VERSION 5.8 ;
BUSBITCHARS "[]" ;
DIVIDERCHAR "/" ;
UNITS
    DATABASE MICRONS 1000 ;
END UNITS

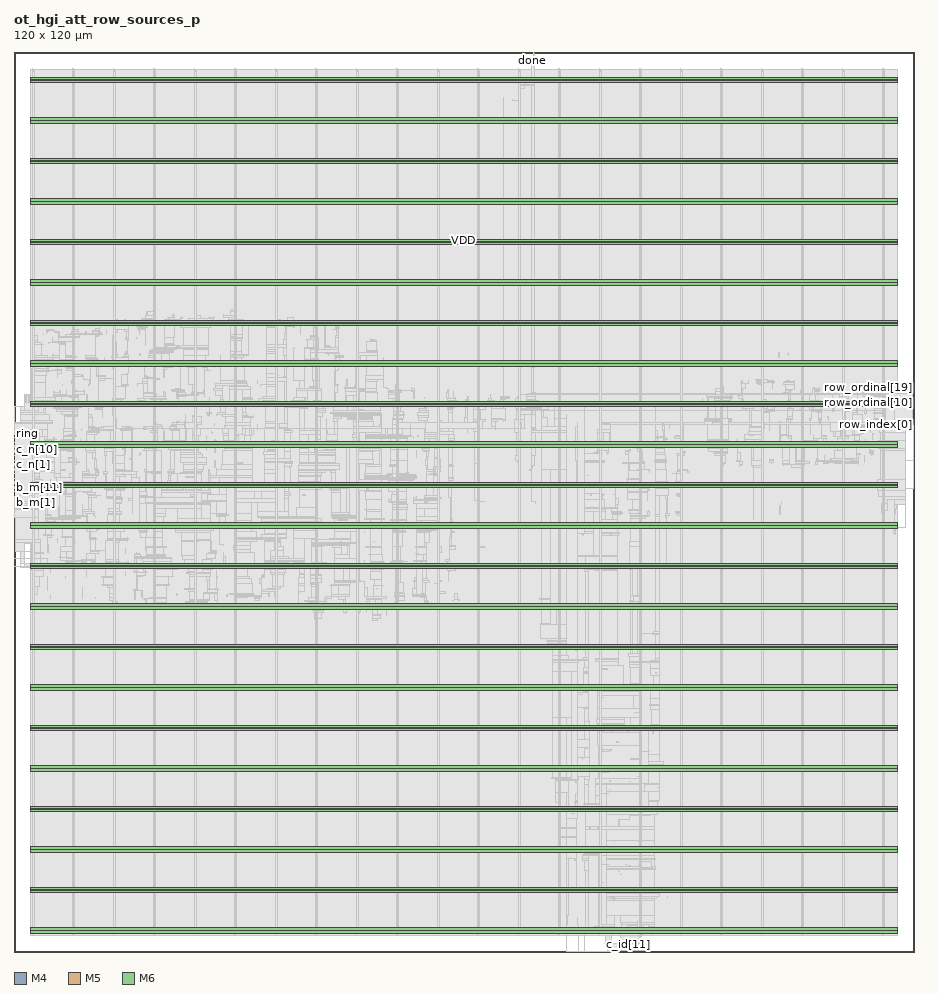
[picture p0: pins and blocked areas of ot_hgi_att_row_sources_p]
MACRO ot_hgi_att_row_sources_p
  FOREIGN ot_hgi_att_row_sources_p 0 0 ;
  CLASS BLOCK ;
  SIZE 120 BY 120 ;
  PIN b_m[0]
    DIRECTION INPUT ;
    USE SIGNAL ;
    PORT
      LAYER M4 ;
        RECT  0 60.912 0.084 60.936 ;
    END
  END b_m[0]
  PIN b_m[10]
    DIRECTION INPUT ;
    USE SIGNAL ;
    PORT
      LAYER M4 ;
        RECT  0 61.872 0.084 61.896 ;
    END
  END b_m[10]
  PIN b_m[11]
    DIRECTION INPUT ;
    USE SIGNAL ;
    PORT
      LAYER M4 ;
        RECT  0 61.968 0.084 61.992 ;
    END
  END b_m[11]
  PIN b_m[12]
    DIRECTION INPUT ;
    USE SIGNAL ;
    PORT
      LAYER M4 ;
        RECT  0 62.064 0.084 62.088 ;
    END
  END b_m[12]
  PIN b_m[13]
    DIRECTION INPUT ;
    USE SIGNAL ;
    PORT
      LAYER M4 ;
        RECT  0 62.16 0.084 62.184 ;
    END
  END b_m[13]
  PIN b_m[14]
    DIRECTION INPUT ;
    USE SIGNAL ;
    PORT
      LAYER M4 ;
        RECT  0 62.256 0.084 62.28 ;
    END
  END b_m[14]
  PIN b_m[15]
    DIRECTION INPUT ;
    USE SIGNAL ;
    PORT
      LAYER M4 ;
        RECT  0 62.352 0.084 62.376 ;
    END
  END b_m[15]
  PIN b_m[16]
    DIRECTION INPUT ;
    USE SIGNAL ;
    PORT
      LAYER M4 ;
        RECT  0 62.448 0.084 62.472 ;
    END
  END b_m[16]
  PIN b_m[17]
    DIRECTION INPUT ;
    USE SIGNAL ;
    PORT
      LAYER M4 ;
        RECT  0 62.544 0.084 62.568 ;
    END
  END b_m[17]
  PIN b_m[18]
    DIRECTION INPUT ;
    USE SIGNAL ;
    PORT
      LAYER M4 ;
        RECT  0 62.64 0.084 62.664 ;
    END
  END b_m[18]
  PIN b_m[19]
    DIRECTION INPUT ;
    USE SIGNAL ;
    PORT
      LAYER M4 ;
        RECT  0 62.736 0.084 62.76 ;
    END
  END b_m[19]
  PIN b_m[1]
    DIRECTION INPUT ;
    USE SIGNAL ;
    PORT
      LAYER M4 ;
        RECT  0 61.008 0.084 61.032 ;
    END
  END b_m[1]
  PIN b_m[20]
    DIRECTION INPUT ;
    USE SIGNAL ;
    PORT
      LAYER M4 ;
        RECT  0 62.832 0.084 62.856 ;
    END
  END b_m[20]
  PIN b_m[2]
    DIRECTION INPUT ;
    USE SIGNAL ;
    PORT
      LAYER M4 ;
        RECT  0 61.104 0.084 61.128 ;
    END
  END b_m[2]
  PIN b_m[3]
    DIRECTION INPUT ;
    USE SIGNAL ;
    PORT
      LAYER M4 ;
        RECT  0 61.2 0.084 61.224 ;
    END
  END b_m[3]
  PIN b_m[4]
    DIRECTION INPUT ;
    USE SIGNAL ;
    PORT
      LAYER M4 ;
        RECT  0 61.296 0.084 61.32 ;
    END
  END b_m[4]
  PIN b_m[5]
    DIRECTION INPUT ;
    USE SIGNAL ;
    PORT
      LAYER M4 ;
        RECT  0 61.392 0.084 61.416 ;
    END
  END b_m[5]
  PIN b_m[6]
    DIRECTION INPUT ;
    USE SIGNAL ;
    PORT
      LAYER M4 ;
        RECT  0 61.488 0.084 61.512 ;
    END
  END b_m[6]
  PIN b_m[7]
    DIRECTION INPUT ;
    USE SIGNAL ;
    PORT
      LAYER M4 ;
        RECT  0 61.584 0.084 61.608 ;
    END
  END b_m[7]
  PIN b_m[8]
    DIRECTION INPUT ;
    USE SIGNAL ;
    PORT
      LAYER M4 ;
        RECT  0 61.68 0.084 61.704 ;
    END
  END b_m[8]
  PIN b_m[9]
    DIRECTION INPUT ;
    USE SIGNAL ;
    PORT
      LAYER M4 ;
        RECT  0 61.776 0.084 61.8 ;
    END
  END b_m[9]
  PIN b_n[0]
    DIRECTION INPUT ;
    USE SIGNAL ;
    PORT
      LAYER M4 ;
        RECT  0 62.928 0.084 62.952 ;
    END
  END b_n[0]
  PIN b_n[10]
    DIRECTION INPUT ;
    USE SIGNAL ;
    PORT
      LAYER M4 ;
        RECT  0 63.888 0.084 63.912 ;
    END
  END b_n[10]
  PIN b_n[11]
    DIRECTION INPUT ;
    USE SIGNAL ;
    PORT
      LAYER M4 ;
        RECT  0 63.984 0.084 64.008 ;
    END
  END b_n[11]
  PIN b_n[12]
    DIRECTION INPUT ;
    USE SIGNAL ;
    PORT
      LAYER M4 ;
        RECT  0 64.08 0.084 64.104 ;
    END
  END b_n[12]
  PIN b_n[13]
    DIRECTION INPUT ;
    USE SIGNAL ;
    PORT
      LAYER M4 ;
        RECT  0 64.176 0.084 64.2 ;
    END
  END b_n[13]
  PIN b_n[14]
    DIRECTION INPUT ;
    USE SIGNAL ;
    PORT
      LAYER M4 ;
        RECT  0 64.272 0.084 64.296 ;
    END
  END b_n[14]
  PIN b_n[15]
    DIRECTION INPUT ;
    USE SIGNAL ;
    PORT
      LAYER M4 ;
        RECT  0 64.368 0.084 64.392 ;
    END
  END b_n[15]
  PIN b_n[16]
    DIRECTION INPUT ;
    USE SIGNAL ;
    PORT
      LAYER M4 ;
        RECT  0 64.464 0.084 64.488 ;
    END
  END b_n[16]
  PIN b_n[17]
    DIRECTION INPUT ;
    USE SIGNAL ;
    PORT
      LAYER M4 ;
        RECT  0 64.56 0.084 64.584 ;
    END
  END b_n[17]
  PIN b_n[18]
    DIRECTION INPUT ;
    USE SIGNAL ;
    PORT
      LAYER M4 ;
        RECT  0 64.656 0.084 64.68 ;
    END
  END b_n[18]
  PIN b_n[19]
    DIRECTION INPUT ;
    USE SIGNAL ;
    PORT
      LAYER M4 ;
        RECT  0 64.752 0.084 64.776 ;
    END
  END b_n[19]
  PIN b_n[1]
    DIRECTION INPUT ;
    USE SIGNAL ;
    PORT
      LAYER M4 ;
        RECT  0 63.024 0.084 63.048 ;
    END
  END b_n[1]
  PIN b_n[20]
    DIRECTION INPUT ;
    USE SIGNAL ;
    PORT
      LAYER M4 ;
        RECT  0 64.848 0.084 64.872 ;
    END
  END b_n[20]
  PIN b_n[2]
    DIRECTION INPUT ;
    USE SIGNAL ;
    PORT
      LAYER M4 ;
        RECT  0 63.12 0.084 63.144 ;
    END
  END b_n[2]
  PIN b_n[3]
    DIRECTION INPUT ;
    USE SIGNAL ;
    PORT
      LAYER M4 ;
        RECT  0 63.216 0.084 63.24 ;
    END
  END b_n[3]
  PIN b_n[4]
    DIRECTION INPUT ;
    USE SIGNAL ;
    PORT
      LAYER M4 ;
        RECT  0 63.312 0.084 63.336 ;
    END
  END b_n[4]
  PIN b_n[5]
    DIRECTION INPUT ;
    USE SIGNAL ;
    PORT
      LAYER M4 ;
        RECT  0 63.408 0.084 63.432 ;
    END
  END b_n[5]
  PIN b_n[6]
    DIRECTION INPUT ;
    USE SIGNAL ;
    PORT
      LAYER M4 ;
        RECT  0 63.504 0.084 63.528 ;
    END
  END b_n[6]
  PIN b_n[7]
    DIRECTION INPUT ;
    USE SIGNAL ;
    PORT
      LAYER M4 ;
        RECT  0 63.6 0.084 63.624 ;
    END
  END b_n[7]
  PIN b_n[8]
    DIRECTION INPUT ;
    USE SIGNAL ;
    PORT
      LAYER M4 ;
        RECT  0 63.696 0.084 63.72 ;
    END
  END b_n[8]
  PIN b_n[9]
    DIRECTION INPUT ;
    USE SIGNAL ;
    PORT
      LAYER M4 ;
        RECT  0 63.792 0.084 63.816 ;
    END
  END b_n[9]
  PIN busy
    DIRECTION OUTPUT ;
    USE SIGNAL ;
    PORT
      LAYER M5 ;
        RECT  68.976 119.916 69 120 ;
    END
  END busy
  PIN c_id[0]
    DIRECTION INPUT ;
    USE SIGNAL ;
    PORT
      LAYER M5 ;
        RECT  80.88 0 80.904 0.084 ;
    END
  END c_id[0]
  PIN c_id[10]
    DIRECTION INPUT ;
    USE SIGNAL ;
    PORT
      LAYER M5 ;
        RECT  81.84 0 81.864 0.084 ;
    END
  END c_id[10]
  PIN c_id[11]
    DIRECTION INPUT ;
    USE SIGNAL ;
    PORT
      LAYER M5 ;
        RECT  81.936 0 81.96 0.084 ;
    END
  END c_id[11]
  PIN c_id[12]
    DIRECTION INPUT ;
    USE SIGNAL ;
    PORT
      LAYER M5 ;
        RECT  82.032 0 82.056 0.084 ;
    END
  END c_id[12]
  PIN c_id[13]
    DIRECTION INPUT ;
    USE SIGNAL ;
    PORT
      LAYER M5 ;
        RECT  82.128 0 82.152 0.084 ;
    END
  END c_id[13]
  PIN c_id[14]
    DIRECTION INPUT ;
    USE SIGNAL ;
    PORT
      LAYER M5 ;
        RECT  82.224 0 82.248 0.084 ;
    END
  END c_id[14]
  PIN c_id[15]
    DIRECTION INPUT ;
    USE SIGNAL ;
    PORT
      LAYER M5 ;
        RECT  82.32 0 82.344 0.084 ;
    END
  END c_id[15]
  PIN c_id[16]
    DIRECTION INPUT ;
    USE SIGNAL ;
    PORT
      LAYER M5 ;
        RECT  82.416 0 82.44 0.084 ;
    END
  END c_id[16]
  PIN c_id[17]
    DIRECTION INPUT ;
    USE SIGNAL ;
    PORT
      LAYER M5 ;
        RECT  82.512 0 82.536 0.084 ;
    END
  END c_id[17]
  PIN c_id[18]
    DIRECTION INPUT ;
    USE SIGNAL ;
    PORT
      LAYER M5 ;
        RECT  82.608 0 82.632 0.084 ;
    END
  END c_id[18]
  PIN c_id[19]
    DIRECTION INPUT ;
    USE SIGNAL ;
    PORT
      LAYER M5 ;
        RECT  82.704 0 82.728 0.084 ;
    END
  END c_id[19]
  PIN c_id[1]
    DIRECTION INPUT ;
    USE SIGNAL ;
    PORT
      LAYER M5 ;
        RECT  80.976 0 81 0.084 ;
    END
  END c_id[1]
  PIN c_id[20]
    DIRECTION INPUT ;
    USE SIGNAL ;
    PORT
      LAYER M5 ;
        RECT  82.8 0 82.824 0.084 ;
    END
  END c_id[20]
  PIN c_id[21]
    DIRECTION INPUT ;
    USE SIGNAL ;
    PORT
      LAYER M5 ;
        RECT  82.896 0 82.92 0.084 ;
    END
  END c_id[21]
  PIN c_id[22]
    DIRECTION INPUT ;
    USE SIGNAL ;
    PORT
      LAYER M5 ;
        RECT  82.992 0 83.016 0.084 ;
    END
  END c_id[22]
  PIN c_id[23]
    DIRECTION INPUT ;
    USE SIGNAL ;
    PORT
      LAYER M5 ;
        RECT  83.088 0 83.112 0.084 ;
    END
  END c_id[23]
  PIN c_id[24]
    DIRECTION INPUT ;
    USE SIGNAL ;
    PORT
      LAYER M5 ;
        RECT  83.184 0 83.208 0.084 ;
    END
  END c_id[24]
  PIN c_id[25]
    DIRECTION INPUT ;
    USE SIGNAL ;
    PORT
      LAYER M5 ;
        RECT  83.28 0 83.304 0.084 ;
    END
  END c_id[25]
  PIN c_id[26]
    DIRECTION INPUT ;
    USE SIGNAL ;
    PORT
      LAYER M5 ;
        RECT  83.376 0 83.4 0.084 ;
    END
  END c_id[26]
  PIN c_id[27]
    DIRECTION INPUT ;
    USE SIGNAL ;
    PORT
      LAYER M5 ;
        RECT  83.472 0 83.496 0.084 ;
    END
  END c_id[27]
  PIN c_id[28]
    DIRECTION INPUT ;
    USE SIGNAL ;
    PORT
      LAYER M5 ;
        RECT  83.568 0 83.592 0.084 ;
    END
  END c_id[28]
  PIN c_id[29]
    DIRECTION INPUT ;
    USE SIGNAL ;
    PORT
      LAYER M5 ;
        RECT  83.664 0 83.688 0.084 ;
    END
  END c_id[29]
  PIN c_id[2]
    DIRECTION INPUT ;
    USE SIGNAL ;
    PORT
      LAYER M5 ;
        RECT  81.072 0 81.096 0.084 ;
    END
  END c_id[2]
  PIN c_id[30]
    DIRECTION INPUT ;
    USE SIGNAL ;
    PORT
      LAYER M5 ;
        RECT  83.76 0 83.784 0.084 ;
    END
  END c_id[30]
  PIN c_id[31]
    DIRECTION INPUT ;
    USE SIGNAL ;
    PORT
      LAYER M5 ;
        RECT  83.856 0 83.88 0.084 ;
    END
  END c_id[31]
  PIN c_id[3]
    DIRECTION INPUT ;
    USE SIGNAL ;
    PORT
      LAYER M5 ;
        RECT  81.168 0 81.192 0.084 ;
    END
  END c_id[3]
  PIN c_id[4]
    DIRECTION INPUT ;
    USE SIGNAL ;
    PORT
      LAYER M5 ;
        RECT  81.264 0 81.288 0.084 ;
    END
  END c_id[4]
  PIN c_id[5]
    DIRECTION INPUT ;
    USE SIGNAL ;
    PORT
      LAYER M5 ;
        RECT  81.36 0 81.384 0.084 ;
    END
  END c_id[5]
  PIN c_id[6]
    DIRECTION INPUT ;
    USE SIGNAL ;
    PORT
      LAYER M5 ;
        RECT  81.456 0 81.48 0.084 ;
    END
  END c_id[6]
  PIN c_id[7]
    DIRECTION INPUT ;
    USE SIGNAL ;
    PORT
      LAYER M5 ;
        RECT  81.552 0 81.576 0.084 ;
    END
  END c_id[7]
  PIN c_id[8]
    DIRECTION INPUT ;
    USE SIGNAL ;
    PORT
      LAYER M5 ;
        RECT  81.648 0 81.672 0.084 ;
    END
  END c_id[8]
  PIN c_id[9]
    DIRECTION INPUT ;
    USE SIGNAL ;
    PORT
      LAYER M5 ;
        RECT  81.744 0 81.768 0.084 ;
    END
  END c_id[9]
  PIN c_id_r
    DIRECTION OUTPUT ;
    USE SIGNAL ;
    PORT
      LAYER M5 ;
        RECT  83.952 0 83.976 0.084 ;
    END
  END c_id_r
  PIN c_id_v
    DIRECTION INPUT ;
    USE SIGNAL ;
    PORT
      LAYER M5 ;
        RECT  84.048 0 84.072 0.084 ;
    END
  END c_id_v
  PIN c_n[0]
    DIRECTION INPUT ;
    USE SIGNAL ;
    PORT
      LAYER M4 ;
        RECT  0 64.944 0.084 64.968 ;
    END
  END c_n[0]
  PIN c_n[10]
    DIRECTION INPUT ;
    USE SIGNAL ;
    PORT
      LAYER M4 ;
        RECT  0 65.904 0.084 65.928 ;
    END
  END c_n[10]
  PIN c_n[11]
    DIRECTION INPUT ;
    USE SIGNAL ;
    PORT
      LAYER M4 ;
        RECT  0 66 0.084 66.024 ;
    END
  END c_n[11]
  PIN c_n[12]
    DIRECTION INPUT ;
    USE SIGNAL ;
    PORT
      LAYER M4 ;
        RECT  0 66.096 0.084 66.12 ;
    END
  END c_n[12]
  PIN c_n[13]
    DIRECTION INPUT ;
    USE SIGNAL ;
    PORT
      LAYER M4 ;
        RECT  0 66.192 0.084 66.216 ;
    END
  END c_n[13]
  PIN c_n[14]
    DIRECTION INPUT ;
    USE SIGNAL ;
    PORT
      LAYER M4 ;
        RECT  0 66.288 0.084 66.312 ;
    END
  END c_n[14]
  PIN c_n[15]
    DIRECTION INPUT ;
    USE SIGNAL ;
    PORT
      LAYER M4 ;
        RECT  0 66.384 0.084 66.408 ;
    END
  END c_n[15]
  PIN c_n[16]
    DIRECTION INPUT ;
    USE SIGNAL ;
    PORT
      LAYER M4 ;
        RECT  0 66.48 0.084 66.504 ;
    END
  END c_n[16]
  PIN c_n[17]
    DIRECTION INPUT ;
    USE SIGNAL ;
    PORT
      LAYER M4 ;
        RECT  0 66.576 0.084 66.6 ;
    END
  END c_n[17]
  PIN c_n[18]
    DIRECTION INPUT ;
    USE SIGNAL ;
    PORT
      LAYER M4 ;
        RECT  0 66.672 0.084 66.696 ;
    END
  END c_n[18]
  PIN c_n[19]
    DIRECTION INPUT ;
    USE SIGNAL ;
    PORT
      LAYER M4 ;
        RECT  0 66.768 0.084 66.792 ;
    END
  END c_n[19]
  PIN c_n[1]
    DIRECTION INPUT ;
    USE SIGNAL ;
    PORT
      LAYER M4 ;
        RECT  0 65.04 0.084 65.064 ;
    END
  END c_n[1]
  PIN c_n[20]
    DIRECTION INPUT ;
    USE SIGNAL ;
    PORT
      LAYER M4 ;
        RECT  0 66.864 0.084 66.888 ;
    END
  END c_n[20]
  PIN c_n[2]
    DIRECTION INPUT ;
    USE SIGNAL ;
    PORT
      LAYER M4 ;
        RECT  0 65.136 0.084 65.16 ;
    END
  END c_n[2]
  PIN c_n[3]
    DIRECTION INPUT ;
    USE SIGNAL ;
    PORT
      LAYER M4 ;
        RECT  0 65.232 0.084 65.256 ;
    END
  END c_n[3]
  PIN c_n[4]
    DIRECTION INPUT ;
    USE SIGNAL ;
    PORT
      LAYER M4 ;
        RECT  0 65.328 0.084 65.352 ;
    END
  END c_n[4]
  PIN c_n[5]
    DIRECTION INPUT ;
    USE SIGNAL ;
    PORT
      LAYER M4 ;
        RECT  0 65.424 0.084 65.448 ;
    END
  END c_n[5]
  PIN c_n[6]
    DIRECTION INPUT ;
    USE SIGNAL ;
    PORT
      LAYER M4 ;
        RECT  0 65.52 0.084 65.544 ;
    END
  END c_n[6]
  PIN c_n[7]
    DIRECTION INPUT ;
    USE SIGNAL ;
    PORT
      LAYER M4 ;
        RECT  0 65.616 0.084 65.64 ;
    END
  END c_n[7]
  PIN c_n[8]
    DIRECTION INPUT ;
    USE SIGNAL ;
    PORT
      LAYER M4 ;
        RECT  0 65.712 0.084 65.736 ;
    END
  END c_n[8]
  PIN c_n[9]
    DIRECTION INPUT ;
    USE SIGNAL ;
    PORT
      LAYER M4 ;
        RECT  0 65.808 0.084 65.832 ;
    END
  END c_n[9]
  PIN clk
    DIRECTION INPUT ;
    USE SIGNAL ;
    PORT
      LAYER M5 ;
        RECT  69.072 119.916 69.096 120 ;
    END
  END clk
  PIN cmd_r
    DIRECTION OUTPUT ;
    USE SIGNAL ;
    PORT
      LAYER M4 ;
        RECT  0 66.96 0.084 66.984 ;
    END
  END cmd_r
  PIN cmd_v
    DIRECTION INPUT ;
    USE SIGNAL ;
    PORT
      LAYER M4 ;
        RECT  0 67.056 0.084 67.08 ;
    END
  END cmd_v
  PIN done
    DIRECTION OUTPUT ;
    USE SIGNAL ;
    PORT
      LAYER M5 ;
        RECT  69.168 119.916 69.192 120 ;
    END
  END done
  PIN fault
    DIRECTION OUTPUT ;
    USE SIGNAL ;
    PORT
      LAYER M5 ;
        RECT  69.264 119.916 69.288 120 ;
    END
  END fault
  PIN pos1[0]
    DIRECTION INPUT ;
    USE SIGNAL ;
    PORT
      LAYER M4 ;
        RECT  0 67.152 0.084 67.176 ;
    END
  END pos1[0]
  PIN pos1[10]
    DIRECTION INPUT ;
    USE SIGNAL ;
    PORT
      LAYER M4 ;
        RECT  0 68.112 0.084 68.136 ;
    END
  END pos1[10]
  PIN pos1[11]
    DIRECTION INPUT ;
    USE SIGNAL ;
    PORT
      LAYER M4 ;
        RECT  0 68.208 0.084 68.232 ;
    END
  END pos1[11]
  PIN pos1[12]
    DIRECTION INPUT ;
    USE SIGNAL ;
    PORT
      LAYER M4 ;
        RECT  0 68.304 0.084 68.328 ;
    END
  END pos1[12]
  PIN pos1[13]
    DIRECTION INPUT ;
    USE SIGNAL ;
    PORT
      LAYER M4 ;
        RECT  0 68.4 0.084 68.424 ;
    END
  END pos1[13]
  PIN pos1[14]
    DIRECTION INPUT ;
    USE SIGNAL ;
    PORT
      LAYER M4 ;
        RECT  0 68.496 0.084 68.52 ;
    END
  END pos1[14]
  PIN pos1[15]
    DIRECTION INPUT ;
    USE SIGNAL ;
    PORT
      LAYER M4 ;
        RECT  0 68.592 0.084 68.616 ;
    END
  END pos1[15]
  PIN pos1[16]
    DIRECTION INPUT ;
    USE SIGNAL ;
    PORT
      LAYER M4 ;
        RECT  0 68.688 0.084 68.712 ;
    END
  END pos1[16]
  PIN pos1[17]
    DIRECTION INPUT ;
    USE SIGNAL ;
    PORT
      LAYER M4 ;
        RECT  0 68.784 0.084 68.808 ;
    END
  END pos1[17]
  PIN pos1[18]
    DIRECTION INPUT ;
    USE SIGNAL ;
    PORT
      LAYER M4 ;
        RECT  0 68.88 0.084 68.904 ;
    END
  END pos1[18]
  PIN pos1[19]
    DIRECTION INPUT ;
    USE SIGNAL ;
    PORT
      LAYER M4 ;
        RECT  0 68.976 0.084 69 ;
    END
  END pos1[19]
  PIN pos1[1]
    DIRECTION INPUT ;
    USE SIGNAL ;
    PORT
      LAYER M4 ;
        RECT  0 67.248 0.084 67.272 ;
    END
  END pos1[1]
  PIN pos1[20]
    DIRECTION INPUT ;
    USE SIGNAL ;
    PORT
      LAYER M4 ;
        RECT  0 69.072 0.084 69.096 ;
    END
  END pos1[20]
  PIN pos1[2]
    DIRECTION INPUT ;
    USE SIGNAL ;
    PORT
      LAYER M4 ;
        RECT  0 67.344 0.084 67.368 ;
    END
  END pos1[2]
  PIN pos1[3]
    DIRECTION INPUT ;
    USE SIGNAL ;
    PORT
      LAYER M4 ;
        RECT  0 67.44 0.084 67.464 ;
    END
  END pos1[3]
  PIN pos1[4]
    DIRECTION INPUT ;
    USE SIGNAL ;
    PORT
      LAYER M4 ;
        RECT  0 67.536 0.084 67.56 ;
    END
  END pos1[4]
  PIN pos1[5]
    DIRECTION INPUT ;
    USE SIGNAL ;
    PORT
      LAYER M4 ;
        RECT  0 67.632 0.084 67.656 ;
    END
  END pos1[5]
  PIN pos1[6]
    DIRECTION INPUT ;
    USE SIGNAL ;
    PORT
      LAYER M4 ;
        RECT  0 67.728 0.084 67.752 ;
    END
  END pos1[6]
  PIN pos1[7]
    DIRECTION INPUT ;
    USE SIGNAL ;
    PORT
      LAYER M4 ;
        RECT  0 67.824 0.084 67.848 ;
    END
  END pos1[7]
  PIN pos1[8]
    DIRECTION INPUT ;
    USE SIGNAL ;
    PORT
      LAYER M4 ;
        RECT  0 67.92 0.084 67.944 ;
    END
  END pos1[8]
  PIN pos1[9]
    DIRECTION INPUT ;
    USE SIGNAL ;
    PORT
      LAYER M4 ;
        RECT  0 68.016 0.084 68.04 ;
    END
  END pos1[9]
  PIN ring
    DIRECTION INPUT ;
    USE SIGNAL ;
    PORT
      LAYER M4 ;
        RECT  0 69.168 0.084 69.192 ;
    END
  END ring
  PIN row_index[0]
    DIRECTION OUTPUT ;
    USE SIGNAL ;
    PORT
      LAYER M4 ;
        RECT  119.916 70.32 120 70.344 ;
    END
  END row_index[0]
  PIN row_index[10]
    DIRECTION OUTPUT ;
    USE SIGNAL ;
    PORT
      LAYER M4 ;
        RECT  119.916 71.28 120 71.304 ;
    END
  END row_index[10]
  PIN row_index[11]
    DIRECTION OUTPUT ;
    USE SIGNAL ;
    PORT
      LAYER M4 ;
        RECT  119.916 71.376 120 71.4 ;
    END
  END row_index[11]
  PIN row_index[12]
    DIRECTION OUTPUT ;
    USE SIGNAL ;
    PORT
      LAYER M4 ;
        RECT  119.916 71.472 120 71.496 ;
    END
  END row_index[12]
  PIN row_index[13]
    DIRECTION OUTPUT ;
    USE SIGNAL ;
    PORT
      LAYER M4 ;
        RECT  119.916 71.568 120 71.592 ;
    END
  END row_index[13]
  PIN row_index[14]
    DIRECTION OUTPUT ;
    USE SIGNAL ;
    PORT
      LAYER M4 ;
        RECT  119.916 71.664 120 71.688 ;
    END
  END row_index[14]
  PIN row_index[15]
    DIRECTION OUTPUT ;
    USE SIGNAL ;
    PORT
      LAYER M4 ;
        RECT  119.916 71.76 120 71.784 ;
    END
  END row_index[15]
  PIN row_index[16]
    DIRECTION OUTPUT ;
    USE SIGNAL ;
    PORT
      LAYER M4 ;
        RECT  119.916 71.856 120 71.88 ;
    END
  END row_index[16]
  PIN row_index[17]
    DIRECTION OUTPUT ;
    USE SIGNAL ;
    PORT
      LAYER M4 ;
        RECT  119.916 71.952 120 71.976 ;
    END
  END row_index[17]
  PIN row_index[18]
    DIRECTION OUTPUT ;
    USE SIGNAL ;
    PORT
      LAYER M4 ;
        RECT  119.916 72.048 120 72.072 ;
    END
  END row_index[18]
  PIN row_index[19]
    DIRECTION OUTPUT ;
    USE SIGNAL ;
    PORT
      LAYER M4 ;
        RECT  119.916 72.144 120 72.168 ;
    END
  END row_index[19]
  PIN row_index[1]
    DIRECTION OUTPUT ;
    USE SIGNAL ;
    PORT
      LAYER M4 ;
        RECT  119.916 70.416 120 70.44 ;
    END
  END row_index[1]
  PIN row_index[2]
    DIRECTION OUTPUT ;
    USE SIGNAL ;
    PORT
      LAYER M4 ;
        RECT  119.916 70.512 120 70.536 ;
    END
  END row_index[2]
  PIN row_index[3]
    DIRECTION OUTPUT ;
    USE SIGNAL ;
    PORT
      LAYER M4 ;
        RECT  119.916 70.608 120 70.632 ;
    END
  END row_index[3]
  PIN row_index[4]
    DIRECTION OUTPUT ;
    USE SIGNAL ;
    PORT
      LAYER M4 ;
        RECT  119.916 70.704 120 70.728 ;
    END
  END row_index[4]
  PIN row_index[5]
    DIRECTION OUTPUT ;
    USE SIGNAL ;
    PORT
      LAYER M4 ;
        RECT  119.916 70.8 120 70.824 ;
    END
  END row_index[5]
  PIN row_index[6]
    DIRECTION OUTPUT ;
    USE SIGNAL ;
    PORT
      LAYER M4 ;
        RECT  119.916 70.896 120 70.92 ;
    END
  END row_index[6]
  PIN row_index[7]
    DIRECTION OUTPUT ;
    USE SIGNAL ;
    PORT
      LAYER M4 ;
        RECT  119.916 70.992 120 71.016 ;
    END
  END row_index[7]
  PIN row_index[8]
    DIRECTION OUTPUT ;
    USE SIGNAL ;
    PORT
      LAYER M4 ;
        RECT  119.916 71.088 120 71.112 ;
    END
  END row_index[8]
  PIN row_index[9]
    DIRECTION OUTPUT ;
    USE SIGNAL ;
    PORT
      LAYER M4 ;
        RECT  119.916 71.184 120 71.208 ;
    END
  END row_index[9]
  PIN row_last
    DIRECTION OUTPUT ;
    USE SIGNAL ;
    PORT
      LAYER M4 ;
        RECT  119.916 72.24 120 72.264 ;
    END
  END row_last
  PIN row_ordinal[0]
    DIRECTION OUTPUT ;
    USE SIGNAL ;
    PORT
      LAYER M4 ;
        RECT  119.916 72.336 120 72.36 ;
    END
  END row_ordinal[0]
  PIN row_ordinal[10]
    DIRECTION OUTPUT ;
    USE SIGNAL ;
    PORT
      LAYER M4 ;
        RECT  119.916 73.296 120 73.32 ;
    END
  END row_ordinal[10]
  PIN row_ordinal[11]
    DIRECTION OUTPUT ;
    USE SIGNAL ;
    PORT
      LAYER M4 ;
        RECT  119.916 73.392 120 73.416 ;
    END
  END row_ordinal[11]
  PIN row_ordinal[12]
    DIRECTION OUTPUT ;
    USE SIGNAL ;
    PORT
      LAYER M4 ;
        RECT  119.916 73.488 120 73.512 ;
    END
  END row_ordinal[12]
  PIN row_ordinal[13]
    DIRECTION OUTPUT ;
    USE SIGNAL ;
    PORT
      LAYER M4 ;
        RECT  119.916 73.584 120 73.608 ;
    END
  END row_ordinal[13]
  PIN row_ordinal[14]
    DIRECTION OUTPUT ;
    USE SIGNAL ;
    PORT
      LAYER M4 ;
        RECT  119.916 73.68 120 73.704 ;
    END
  END row_ordinal[14]
  PIN row_ordinal[15]
    DIRECTION OUTPUT ;
    USE SIGNAL ;
    PORT
      LAYER M4 ;
        RECT  119.916 73.776 120 73.8 ;
    END
  END row_ordinal[15]
  PIN row_ordinal[16]
    DIRECTION OUTPUT ;
    USE SIGNAL ;
    PORT
      LAYER M4 ;
        RECT  119.916 73.872 120 73.896 ;
    END
  END row_ordinal[16]
  PIN row_ordinal[17]
    DIRECTION OUTPUT ;
    USE SIGNAL ;
    PORT
      LAYER M4 ;
        RECT  119.916 73.968 120 73.992 ;
    END
  END row_ordinal[17]
  PIN row_ordinal[18]
    DIRECTION OUTPUT ;
    USE SIGNAL ;
    PORT
      LAYER M4 ;
        RECT  119.916 74.064 120 74.088 ;
    END
  END row_ordinal[18]
  PIN row_ordinal[19]
    DIRECTION OUTPUT ;
    USE SIGNAL ;
    PORT
      LAYER M4 ;
        RECT  119.916 74.16 120 74.184 ;
    END
  END row_ordinal[19]
  PIN row_ordinal[1]
    DIRECTION OUTPUT ;
    USE SIGNAL ;
    PORT
      LAYER M4 ;
        RECT  119.916 72.432 120 72.456 ;
    END
  END row_ordinal[1]
  PIN row_ordinal[20]
    DIRECTION OUTPUT ;
    USE SIGNAL ;
    PORT
      LAYER M4 ;
        RECT  119.916 74.256 120 74.28 ;
    END
  END row_ordinal[20]
  PIN row_ordinal[2]
    DIRECTION OUTPUT ;
    USE SIGNAL ;
    PORT
      LAYER M4 ;
        RECT  119.916 72.528 120 72.552 ;
    END
  END row_ordinal[2]
  PIN row_ordinal[3]
    DIRECTION OUTPUT ;
    USE SIGNAL ;
    PORT
      LAYER M4 ;
        RECT  119.916 72.624 120 72.648 ;
    END
  END row_ordinal[3]
  PIN row_ordinal[4]
    DIRECTION OUTPUT ;
    USE SIGNAL ;
    PORT
      LAYER M4 ;
        RECT  119.916 72.72 120 72.744 ;
    END
  END row_ordinal[4]
  PIN row_ordinal[5]
    DIRECTION OUTPUT ;
    USE SIGNAL ;
    PORT
      LAYER M4 ;
        RECT  119.916 72.816 120 72.84 ;
    END
  END row_ordinal[5]
  PIN row_ordinal[6]
    DIRECTION OUTPUT ;
    USE SIGNAL ;
    PORT
      LAYER M4 ;
        RECT  119.916 72.912 120 72.936 ;
    END
  END row_ordinal[6]
  PIN row_ordinal[7]
    DIRECTION OUTPUT ;
    USE SIGNAL ;
    PORT
      LAYER M4 ;
        RECT  119.916 73.008 120 73.032 ;
    END
  END row_ordinal[7]
  PIN row_ordinal[8]
    DIRECTION OUTPUT ;
    USE SIGNAL ;
    PORT
      LAYER M4 ;
        RECT  119.916 73.104 120 73.128 ;
    END
  END row_ordinal[8]
  PIN row_ordinal[9]
    DIRECTION OUTPUT ;
    USE SIGNAL ;
    PORT
      LAYER M4 ;
        RECT  119.916 73.2 120 73.224 ;
    END
  END row_ordinal[9]
  PIN row_r
    DIRECTION INPUT ;
    USE SIGNAL ;
    PORT
      LAYER M4 ;
        RECT  119.916 74.352 120 74.376 ;
    END
  END row_r
  PIN row_source
    DIRECTION OUTPUT ;
    USE SIGNAL ;
    PORT
      LAYER M4 ;
        RECT  119.916 74.448 120 74.472 ;
    END
  END row_source
  PIN row_v
    DIRECTION OUTPUT ;
    USE SIGNAL ;
    PORT
      LAYER M4 ;
        RECT  119.916 74.544 120 74.568 ;
    END
  END row_v
  PIN rst_n
    DIRECTION INPUT ;
    USE SIGNAL ;
    PORT
      LAYER M5 ;
        RECT  69.36 119.916 69.384 120 ;
    END
  END rst_n
  PIN VDD
    DIRECTION INOUT ;
    USE POWER ;
    PORT
      LAYER M6 ;
        RECT  2.16 116.313 117.828 116.601 ;
        RECT  2.16 110.913 117.828 111.201 ;
        RECT  2.16 105.513 117.828 105.801 ;
        RECT  2.16 100.113 117.828 100.401 ;
        RECT  2.16 94.713 117.828 95.001 ;
        RECT  2.16 89.313 117.828 89.601 ;
        RECT  2.16 83.913 117.828 84.201 ;
        RECT  2.16 78.513 117.828 78.801 ;
        RECT  2.16 73.113 117.828 73.401 ;
        RECT  2.16 67.713 117.828 68.001 ;
        RECT  2.16 62.313 117.828 62.601 ;
        RECT  2.16 56.913 117.828 57.201 ;
        RECT  2.16 51.513 117.828 51.801 ;
        RECT  2.16 46.113 117.828 46.401 ;
        RECT  2.16 40.713 117.828 41.001 ;
        RECT  2.16 35.313 117.828 35.601 ;
        RECT  2.16 29.913 117.828 30.201 ;
        RECT  2.16 24.513 117.828 24.801 ;
        RECT  2.16 19.113 117.828 19.401 ;
        RECT  2.16 13.713 117.828 14.001 ;
        RECT  2.16 8.313 117.828 8.601 ;
        RECT  2.16 2.913 117.828 3.201 ;
    END
  END VDD
  PIN VSS
    DIRECTION INOUT ;
    USE GROUND ;
    PORT
      LAYER M6 ;
        RECT  2.16 115.929 117.828 116.217 ;
        RECT  2.16 110.529 117.828 110.817 ;
        RECT  2.16 105.129 117.828 105.417 ;
        RECT  2.16 99.729 117.828 100.017 ;
        RECT  2.16 94.329 117.828 94.617 ;
        RECT  2.16 88.929 117.828 89.217 ;
        RECT  2.16 83.529 117.828 83.817 ;
        RECT  2.16 78.129 117.828 78.417 ;
        RECT  2.16 72.729 117.828 73.017 ;
        RECT  2.16 67.329 117.828 67.617 ;
        RECT  2.16 61.929 117.828 62.217 ;
        RECT  2.16 56.529 117.828 56.817 ;
        RECT  2.16 51.129 117.828 51.417 ;
        RECT  2.16 45.729 117.828 46.017 ;
        RECT  2.16 40.329 117.828 40.617 ;
        RECT  2.16 34.929 117.828 35.217 ;
        RECT  2.16 29.529 117.828 29.817 ;
        RECT  2.16 24.129 117.828 24.417 ;
        RECT  2.16 18.729 117.828 19.017 ;
        RECT  2.16 13.329 117.828 13.617 ;
        RECT  2.16 7.929 117.828 8.217 ;
        RECT  2.16 2.529 117.828 2.817 ;
    END
  END VSS
  OBS
    LAYER RVTN ;
     RECT  2.16 2.16 117.828 2.295 ;
     RECT  2.16 2.565 117.828 2.835 ;
     RECT  2.16 3.105 117.828 3.375 ;
     RECT  2.16 3.645 117.828 3.915 ;
     RECT  2.16 4.185 117.828 4.455 ;
     RECT  2.16 4.725 117.828 4.995 ;
     RECT  2.16 5.265 117.828 5.535 ;
     RECT  2.16 5.805 117.828 6.075 ;
     RECT  2.16 6.345 117.828 6.615 ;
     RECT  2.16 6.885 117.828 7.155 ;
     RECT  2.16 7.425 117.828 7.695 ;
     RECT  2.16 7.965 117.828 8.235 ;
     RECT  2.16 8.505 117.828 8.775 ;
     RECT  2.16 9.045 117.828 9.315 ;
     RECT  2.16 9.585 117.828 9.855 ;
     RECT  2.16 10.125 117.828 10.395 ;
     RECT  2.16 10.665 117.828 10.935 ;
     RECT  2.16 11.205 117.828 11.475 ;
     RECT  2.16 11.745 117.828 12.015 ;
     RECT  2.16 12.285 117.828 12.555 ;
     RECT  2.16 12.825 117.828 13.095 ;
     RECT  2.16 13.365 117.828 13.635 ;
     RECT  2.16 13.905 117.828 14.175 ;
     RECT  2.16 14.445 117.828 14.715 ;
     RECT  2.16 14.985 117.828 15.255 ;
     RECT  2.16 15.525 117.828 15.795 ;
     RECT  2.16 16.065 117.828 16.335 ;
     RECT  2.16 16.605 117.828 16.875 ;
     RECT  2.16 17.145 117.828 17.415 ;
     RECT  2.16 17.685 117.828 17.955 ;
     RECT  2.16 18.225 117.828 18.495 ;
     RECT  2.16 18.765 117.828 19.035 ;
     RECT  2.16 19.305 117.828 19.575 ;
     RECT  2.16 19.845 117.828 20.115 ;
     RECT  2.16 20.385 117.828 20.655 ;
     RECT  2.16 20.925 117.828 21.195 ;
     RECT  2.16 21.465 117.828 21.735 ;
     RECT  2.16 22.005 117.828 22.275 ;
     RECT  2.16 22.545 117.828 22.815 ;
     RECT  2.16 23.085 117.828 23.355 ;
     RECT  2.16 23.625 117.828 23.895 ;
     RECT  2.16 24.165 117.828 24.435 ;
     RECT  2.16 24.705 117.828 24.975 ;
     RECT  2.16 25.245 117.828 25.515 ;
     RECT  2.16 25.785 117.828 26.055 ;
     RECT  2.16 26.325 117.828 26.595 ;
     RECT  2.16 26.865 117.828 27.135 ;
     RECT  2.16 27.405 117.828 27.675 ;
     RECT  2.16 27.945 117.828 28.215 ;
     RECT  2.16 28.485 117.828 28.755 ;
     RECT  2.16 29.025 117.828 29.295 ;
     RECT  2.16 29.565 117.828 29.835 ;
     RECT  2.16 30.105 117.828 30.375 ;
     RECT  2.16 30.645 117.828 30.915 ;
     RECT  2.16 31.185 117.828 31.455 ;
     RECT  2.16 31.725 117.828 31.995 ;
     RECT  2.16 32.265 117.828 32.535 ;
     RECT  2.16 32.805 117.828 33.075 ;
     RECT  2.16 33.345 117.828 33.615 ;
     RECT  2.16 33.885 117.828 34.155 ;
     RECT  2.16 34.425 117.828 34.695 ;
     RECT  2.16 34.965 117.828 35.235 ;
     RECT  2.16 35.505 117.828 35.775 ;
     RECT  2.16 36.045 117.828 36.315 ;
     RECT  2.16 36.585 117.828 36.855 ;
     RECT  2.16 37.125 117.828 37.395 ;
     RECT  2.16 37.665 117.828 37.935 ;
     RECT  2.16 38.205 117.828 38.475 ;
     RECT  2.16 38.745 117.828 39.015 ;
     RECT  2.16 39.285 117.828 39.555 ;
     RECT  2.16 39.825 117.828 40.095 ;
     RECT  2.16 40.365 117.828 40.635 ;
     RECT  2.16 40.905 117.828 41.175 ;
     RECT  2.16 41.445 117.828 41.715 ;
     RECT  2.16 41.985 117.828 42.255 ;
     RECT  2.16 42.525 117.828 42.795 ;
     RECT  2.16 43.065 117.828 43.335 ;
     RECT  2.16 43.605 117.828 43.875 ;
     RECT  2.16 44.145 117.828 44.415 ;
     RECT  2.16 44.685 117.828 44.955 ;
     RECT  2.16 45.225 117.828 45.495 ;
     RECT  2.16 45.765 117.828 46.035 ;
     RECT  2.16 46.305 117.828 46.575 ;
     RECT  2.16 46.845 117.828 47.115 ;
     RECT  2.16 47.385 117.828 47.655 ;
     RECT  2.16 47.925 117.828 48.195 ;
     RECT  2.16 48.465 117.828 48.735 ;
     RECT  2.16 49.005 117.828 49.275 ;
     RECT  2.16 49.545 117.828 49.815 ;
     RECT  2.16 50.085 117.828 50.355 ;
     RECT  2.16 50.625 117.828 50.895 ;
     RECT  2.16 51.165 117.828 51.435 ;
     RECT  2.16 51.705 117.828 51.975 ;
     RECT  2.16 52.245 117.828 52.515 ;
     RECT  2.16 52.785 117.828 53.055 ;
     RECT  2.16 53.325 117.828 53.595 ;
     RECT  2.16 53.865 117.828 54.135 ;
     RECT  2.16 54.405 117.828 54.675 ;
     RECT  2.16 54.945 117.828 55.215 ;
     RECT  2.16 55.485 117.828 55.755 ;
     RECT  2.16 56.025 117.828 56.295 ;
     RECT  2.16 56.565 117.828 56.835 ;
     RECT  2.16 57.105 117.828 57.375 ;
     RECT  2.16 57.645 117.828 57.915 ;
     RECT  2.16 58.185 117.828 58.455 ;
     RECT  2.16 58.725 117.828 58.995 ;
     RECT  2.16 59.265 117.828 59.535 ;
     RECT  2.16 59.805 117.828 60.075 ;
     RECT  2.16 60.345 117.828 60.615 ;
     RECT  2.16 60.885 117.828 61.155 ;
     RECT  2.16 61.425 117.828 61.695 ;
     RECT  2.16 61.965 117.828 62.235 ;
     RECT  2.16 62.505 117.828 62.775 ;
     RECT  2.16 63.045 117.828 63.315 ;
     RECT  2.16 63.585 117.828 63.855 ;
     RECT  2.16 64.125 117.828 64.395 ;
     RECT  2.16 64.665 117.828 64.935 ;
     RECT  2.16 65.205 117.828 65.475 ;
     RECT  2.16 65.745 117.828 66.015 ;
     RECT  2.16 66.285 117.828 66.555 ;
     RECT  2.16 66.825 117.828 67.095 ;
     RECT  2.16 67.365 117.828 67.635 ;
     RECT  2.16 67.905 117.828 68.175 ;
     RECT  2.16 68.445 117.828 68.715 ;
     RECT  2.16 68.985 117.828 69.255 ;
     RECT  2.16 69.525 117.828 69.795 ;
     RECT  2.16 70.065 117.828 70.335 ;
     RECT  2.16 70.605 117.828 70.875 ;
     RECT  2.16 71.145 117.828 71.415 ;
     RECT  2.16 71.685 117.828 71.955 ;
     RECT  2.16 72.225 117.828 72.495 ;
     RECT  2.16 72.765 117.828 73.035 ;
     RECT  2.16 73.305 117.828 73.575 ;
     RECT  2.16 73.845 117.828 74.115 ;
     RECT  2.16 74.385 117.828 74.655 ;
     RECT  2.16 74.925 117.828 75.195 ;
     RECT  2.16 75.465 117.828 75.735 ;
     RECT  2.16 76.005 117.828 76.275 ;
     RECT  2.16 76.545 117.828 76.815 ;
     RECT  2.16 77.085 117.828 77.355 ;
     RECT  2.16 77.625 117.828 77.895 ;
     RECT  2.16 78.165 117.828 78.435 ;
     RECT  2.16 78.705 117.828 78.975 ;
     RECT  2.16 79.245 117.828 79.515 ;
     RECT  2.16 79.785 117.828 80.055 ;
     RECT  2.16 80.325 117.828 80.595 ;
     RECT  2.16 80.865 117.828 81.135 ;
     RECT  2.16 81.405 117.828 81.675 ;
     RECT  2.16 81.945 117.828 82.215 ;
     RECT  2.16 82.485 117.828 82.755 ;
     RECT  2.16 83.025 117.828 83.295 ;
     RECT  2.16 83.565 117.828 83.835 ;
     RECT  2.16 84.105 117.828 84.375 ;
     RECT  2.16 84.645 117.828 84.915 ;
     RECT  2.16 85.185 117.828 85.455 ;
     RECT  2.16 85.725 117.828 85.995 ;
     RECT  2.16 86.265 117.828 86.535 ;
     RECT  2.16 86.805 117.828 87.075 ;
     RECT  2.16 87.345 117.828 87.615 ;
     RECT  2.16 87.885 117.828 88.155 ;
     RECT  2.16 88.425 117.828 88.695 ;
     RECT  2.16 88.965 117.828 89.235 ;
     RECT  2.16 89.505 117.828 89.775 ;
     RECT  2.16 90.045 117.828 90.315 ;
     RECT  2.16 90.585 117.828 90.855 ;
     RECT  2.16 91.125 117.828 91.395 ;
     RECT  2.16 91.665 117.828 91.935 ;
     RECT  2.16 92.205 117.828 92.475 ;
     RECT  2.16 92.745 117.828 93.015 ;
     RECT  2.16 93.285 117.828 93.555 ;
     RECT  2.16 93.825 117.828 94.095 ;
     RECT  2.16 94.365 117.828 94.635 ;
     RECT  2.16 94.905 117.828 95.175 ;
     RECT  2.16 95.445 117.828 95.715 ;
     RECT  2.16 95.985 117.828 96.255 ;
     RECT  2.16 96.525 117.828 96.795 ;
     RECT  2.16 97.065 117.828 97.335 ;
     RECT  2.16 97.605 117.828 97.875 ;
     RECT  2.16 98.145 117.828 98.415 ;
     RECT  2.16 98.685 117.828 98.955 ;
     RECT  2.16 99.225 117.828 99.495 ;
     RECT  2.16 99.765 117.828 100.035 ;
     RECT  2.16 100.305 117.828 100.575 ;
     RECT  2.16 100.845 117.828 101.115 ;
     RECT  2.16 101.385 117.828 101.655 ;
     RECT  2.16 101.925 117.828 102.195 ;
     RECT  2.16 102.465 117.828 102.735 ;
     RECT  2.16 103.005 117.828 103.275 ;
     RECT  2.16 103.545 117.828 103.815 ;
     RECT  2.16 104.085 117.828 104.355 ;
     RECT  2.16 104.625 117.828 104.895 ;
     RECT  2.16 105.165 117.828 105.435 ;
     RECT  2.16 105.705 117.828 105.975 ;
     RECT  2.16 106.245 117.828 106.515 ;
     RECT  2.16 106.785 117.828 107.055 ;
     RECT  2.16 107.325 117.828 107.595 ;
     RECT  2.16 107.865 117.828 108.135 ;
     RECT  2.16 108.405 117.828 108.675 ;
     RECT  2.16 108.945 117.828 109.215 ;
     RECT  2.16 109.485 117.828 109.755 ;
     RECT  2.16 110.025 117.828 110.295 ;
     RECT  2.16 110.565 117.828 110.835 ;
     RECT  2.16 111.105 117.828 111.375 ;
     RECT  2.16 111.645 117.828 111.915 ;
     RECT  2.16 112.185 117.828 112.455 ;
     RECT  2.16 112.725 117.828 112.995 ;
     RECT  2.16 113.265 117.828 113.535 ;
     RECT  2.16 113.805 117.828 114.075 ;
     RECT  2.16 114.345 117.828 114.615 ;
     RECT  2.16 114.885 117.828 115.155 ;
     RECT  2.16 115.425 117.828 115.695 ;
     RECT  2.16 115.965 117.828 116.235 ;
     RECT  2.16 116.505 117.828 116.775 ;
     RECT  2.16 117.045 117.828 117.315 ;
     RECT  2.16 117.585 117.828 117.72 ;
    LAYER RVTP ;
     RECT  2.16 2.295 117.828 2.565 ;
     RECT  2.16 2.835 117.828 3.105 ;
     RECT  2.16 3.375 117.828 3.645 ;
     RECT  2.16 3.915 117.828 4.185 ;
     RECT  2.16 4.455 117.828 4.725 ;
     RECT  2.16 4.995 117.828 5.265 ;
     RECT  2.16 5.535 117.828 5.805 ;
     RECT  2.16 6.075 117.828 6.345 ;
     RECT  2.16 6.615 117.828 6.885 ;
     RECT  2.16 7.155 117.828 7.425 ;
     RECT  2.16 7.695 117.828 7.965 ;
     RECT  2.16 8.235 117.828 8.505 ;
     RECT  2.16 8.775 117.828 9.045 ;
     RECT  2.16 9.315 117.828 9.585 ;
     RECT  2.16 9.855 117.828 10.125 ;
     RECT  2.16 10.395 117.828 10.665 ;
     RECT  2.16 10.935 117.828 11.205 ;
     RECT  2.16 11.475 117.828 11.745 ;
     RECT  2.16 12.015 117.828 12.285 ;
     RECT  2.16 12.555 117.828 12.825 ;
     RECT  2.16 13.095 117.828 13.365 ;
     RECT  2.16 13.635 117.828 13.905 ;
     RECT  2.16 14.175 117.828 14.445 ;
     RECT  2.16 14.715 117.828 14.985 ;
     RECT  2.16 15.255 117.828 15.525 ;
     RECT  2.16 15.795 117.828 16.065 ;
     RECT  2.16 16.335 117.828 16.605 ;
     RECT  2.16 16.875 117.828 17.145 ;
     RECT  2.16 17.415 117.828 17.685 ;
     RECT  2.16 17.955 117.828 18.225 ;
     RECT  2.16 18.495 117.828 18.765 ;
     RECT  2.16 19.035 117.828 19.305 ;
     RECT  2.16 19.575 117.828 19.845 ;
     RECT  2.16 20.115 117.828 20.385 ;
     RECT  2.16 20.655 117.828 20.925 ;
     RECT  2.16 21.195 117.828 21.465 ;
     RECT  2.16 21.735 117.828 22.005 ;
     RECT  2.16 22.275 117.828 22.545 ;
     RECT  2.16 22.815 117.828 23.085 ;
     RECT  2.16 23.355 117.828 23.625 ;
     RECT  2.16 23.895 117.828 24.165 ;
     RECT  2.16 24.435 117.828 24.705 ;
     RECT  2.16 24.975 117.828 25.245 ;
     RECT  2.16 25.515 117.828 25.785 ;
     RECT  2.16 26.055 117.828 26.325 ;
     RECT  2.16 26.595 117.828 26.865 ;
     RECT  2.16 27.135 117.828 27.405 ;
     RECT  2.16 27.675 117.828 27.945 ;
     RECT  2.16 28.215 117.828 28.485 ;
     RECT  2.16 28.755 117.828 29.025 ;
     RECT  2.16 29.295 117.828 29.565 ;
     RECT  2.16 29.835 117.828 30.105 ;
     RECT  2.16 30.375 117.828 30.645 ;
     RECT  2.16 30.915 117.828 31.185 ;
     RECT  2.16 31.455 117.828 31.725 ;
     RECT  2.16 31.995 117.828 32.265 ;
     RECT  2.16 32.535 117.828 32.805 ;
     RECT  2.16 33.075 117.828 33.345 ;
     RECT  2.16 33.615 117.828 33.885 ;
     RECT  2.16 34.155 117.828 34.425 ;
     RECT  2.16 34.695 117.828 34.965 ;
     RECT  2.16 35.235 117.828 35.505 ;
     RECT  2.16 35.775 117.828 36.045 ;
     RECT  2.16 36.315 117.828 36.585 ;
     RECT  2.16 36.855 117.828 37.125 ;
     RECT  2.16 37.395 117.828 37.665 ;
     RECT  2.16 37.935 117.828 38.205 ;
     RECT  2.16 38.475 117.828 38.745 ;
     RECT  2.16 39.015 117.828 39.285 ;
     RECT  2.16 39.555 117.828 39.825 ;
     RECT  2.16 40.095 117.828 40.365 ;
     RECT  2.16 40.635 117.828 40.905 ;
     RECT  2.16 41.175 117.828 41.445 ;
     RECT  2.16 41.715 117.828 41.985 ;
     RECT  2.16 42.255 117.828 42.525 ;
     RECT  2.16 42.795 117.828 43.065 ;
     RECT  2.16 43.335 117.828 43.605 ;
     RECT  2.16 43.875 117.828 44.145 ;
     RECT  2.16 44.415 117.828 44.685 ;
     RECT  2.16 44.955 117.828 45.225 ;
     RECT  2.16 45.495 117.828 45.765 ;
     RECT  2.16 46.035 117.828 46.305 ;
     RECT  2.16 46.575 117.828 46.845 ;
     RECT  2.16 47.115 117.828 47.385 ;
     RECT  2.16 47.655 117.828 47.925 ;
     RECT  2.16 48.195 117.828 48.465 ;
     RECT  2.16 48.735 117.828 49.005 ;
     RECT  2.16 49.275 117.828 49.545 ;
     RECT  2.16 49.815 117.828 50.085 ;
     RECT  2.16 50.355 117.828 50.625 ;
     RECT  2.16 50.895 117.828 51.165 ;
     RECT  2.16 51.435 117.828 51.705 ;
     RECT  2.16 51.975 117.828 52.245 ;
     RECT  2.16 52.515 117.828 52.785 ;
     RECT  2.16 53.055 117.828 53.325 ;
     RECT  2.16 53.595 117.828 53.865 ;
     RECT  2.16 54.135 117.828 54.405 ;
     RECT  2.16 54.675 117.828 54.945 ;
     RECT  2.16 55.215 117.828 55.485 ;
     RECT  2.16 55.755 117.828 56.025 ;
     RECT  2.16 56.295 117.828 56.565 ;
     RECT  2.16 56.835 117.828 57.105 ;
     RECT  2.16 57.375 117.828 57.645 ;
     RECT  2.16 57.915 117.828 58.185 ;
     RECT  2.16 58.455 117.828 58.725 ;
     RECT  2.16 58.995 117.828 59.265 ;
     RECT  2.16 59.535 117.828 59.805 ;
     RECT  2.16 60.075 117.828 60.345 ;
     RECT  2.16 60.615 117.828 60.885 ;
     RECT  2.16 61.155 117.828 61.425 ;
     RECT  2.16 61.695 117.828 61.965 ;
     RECT  2.16 62.235 117.828 62.505 ;
     RECT  2.16 62.775 117.828 63.045 ;
     RECT  2.16 63.315 117.828 63.585 ;
     RECT  2.16 63.855 117.828 64.125 ;
     RECT  2.16 64.395 117.828 64.665 ;
     RECT  2.16 64.935 117.828 65.205 ;
     RECT  2.16 65.475 117.828 65.745 ;
     RECT  2.16 66.015 117.828 66.285 ;
     RECT  2.16 66.555 117.828 66.825 ;
     RECT  2.16 67.095 117.828 67.365 ;
     RECT  2.16 67.635 117.828 67.905 ;
     RECT  2.16 68.175 117.828 68.445 ;
     RECT  2.16 68.715 117.828 68.985 ;
     RECT  2.16 69.255 117.828 69.525 ;
     RECT  2.16 69.795 117.828 70.065 ;
     RECT  2.16 70.335 117.828 70.605 ;
     RECT  2.16 70.875 117.828 71.145 ;
     RECT  2.16 71.415 117.828 71.685 ;
     RECT  2.16 71.955 117.828 72.225 ;
     RECT  2.16 72.495 117.828 72.765 ;
     RECT  2.16 73.035 117.828 73.305 ;
     RECT  2.16 73.575 117.828 73.845 ;
     RECT  2.16 74.115 117.828 74.385 ;
     RECT  2.16 74.655 117.828 74.925 ;
     RECT  2.16 75.195 117.828 75.465 ;
     RECT  2.16 75.735 117.828 76.005 ;
     RECT  2.16 76.275 117.828 76.545 ;
     RECT  2.16 76.815 117.828 77.085 ;
     RECT  2.16 77.355 117.828 77.625 ;
     RECT  2.16 77.895 117.828 78.165 ;
     RECT  2.16 78.435 117.828 78.705 ;
     RECT  2.16 78.975 117.828 79.245 ;
     RECT  2.16 79.515 117.828 79.785 ;
     RECT  2.16 80.055 117.828 80.325 ;
     RECT  2.16 80.595 117.828 80.865 ;
     RECT  2.16 81.135 117.828 81.405 ;
     RECT  2.16 81.675 117.828 81.945 ;
     RECT  2.16 82.215 117.828 82.485 ;
     RECT  2.16 82.755 117.828 83.025 ;
     RECT  2.16 83.295 117.828 83.565 ;
     RECT  2.16 83.835 117.828 84.105 ;
     RECT  2.16 84.375 117.828 84.645 ;
     RECT  2.16 84.915 117.828 85.185 ;
     RECT  2.16 85.455 117.828 85.725 ;
     RECT  2.16 85.995 117.828 86.265 ;
     RECT  2.16 86.535 117.828 86.805 ;
     RECT  2.16 87.075 117.828 87.345 ;
     RECT  2.16 87.615 117.828 87.885 ;
     RECT  2.16 88.155 117.828 88.425 ;
     RECT  2.16 88.695 117.828 88.965 ;
     RECT  2.16 89.235 117.828 89.505 ;
     RECT  2.16 89.775 117.828 90.045 ;
     RECT  2.16 90.315 117.828 90.585 ;
     RECT  2.16 90.855 117.828 91.125 ;
     RECT  2.16 91.395 117.828 91.665 ;
     RECT  2.16 91.935 117.828 92.205 ;
     RECT  2.16 92.475 117.828 92.745 ;
     RECT  2.16 93.015 117.828 93.285 ;
     RECT  2.16 93.555 117.828 93.825 ;
     RECT  2.16 94.095 117.828 94.365 ;
     RECT  2.16 94.635 117.828 94.905 ;
     RECT  2.16 95.175 117.828 95.445 ;
     RECT  2.16 95.715 117.828 95.985 ;
     RECT  2.16 96.255 117.828 96.525 ;
     RECT  2.16 96.795 117.828 97.065 ;
     RECT  2.16 97.335 117.828 97.605 ;
     RECT  2.16 97.875 117.828 98.145 ;
     RECT  2.16 98.415 117.828 98.685 ;
     RECT  2.16 98.955 117.828 99.225 ;
     RECT  2.16 99.495 117.828 99.765 ;
     RECT  2.16 100.035 117.828 100.305 ;
     RECT  2.16 100.575 117.828 100.845 ;
     RECT  2.16 101.115 117.828 101.385 ;
     RECT  2.16 101.655 117.828 101.925 ;
     RECT  2.16 102.195 117.828 102.465 ;
     RECT  2.16 102.735 117.828 103.005 ;
     RECT  2.16 103.275 117.828 103.545 ;
     RECT  2.16 103.815 117.828 104.085 ;
     RECT  2.16 104.355 117.828 104.625 ;
     RECT  2.16 104.895 117.828 105.165 ;
     RECT  2.16 105.435 117.828 105.705 ;
     RECT  2.16 105.975 117.828 106.245 ;
     RECT  2.16 106.515 117.828 106.785 ;
     RECT  2.16 107.055 117.828 107.325 ;
     RECT  2.16 107.595 117.828 107.865 ;
     RECT  2.16 108.135 117.828 108.405 ;
     RECT  2.16 108.675 117.828 108.945 ;
     RECT  2.16 109.215 117.828 109.485 ;
     RECT  2.16 109.755 117.828 110.025 ;
     RECT  2.16 110.295 117.828 110.565 ;
     RECT  2.16 110.835 117.828 111.105 ;
     RECT  2.16 111.375 117.828 111.645 ;
     RECT  2.16 111.915 117.828 112.185 ;
     RECT  2.16 112.455 117.828 112.725 ;
     RECT  2.16 112.995 117.828 113.265 ;
     RECT  2.16 113.535 117.828 113.805 ;
     RECT  2.16 114.075 117.828 114.345 ;
     RECT  2.16 114.615 117.828 114.885 ;
     RECT  2.16 115.155 117.828 115.425 ;
     RECT  2.16 115.695 117.828 115.965 ;
     RECT  2.16 116.235 117.828 116.505 ;
     RECT  2.16 116.775 117.828 117.045 ;
     RECT  2.16 117.315 117.828 117.585 ;
    LAYER M1 ;
     RECT  2.16 2.151 117.828 117.729 ;
    LAYER M2 ;
     RECT  0.067 63.486 0.167 63.504 ;
     RECT  0.067 66.636 0.167 66.654 ;
     RECT  0.103 57.96 0.175 57.978 ;
     RECT  0.103 70.344 0.175 70.362 ;
     RECT  0.175 57.69 0.247 57.978 ;
     RECT  0.067 59.04 0.247 59.058 ;
     RECT  0.571 64.602 0.607 64.62 ;
     RECT  0.607 64.602 0.643 64.89 ;
     RECT  0.067 72.702 0.823 72.72 ;
     RECT  0.247 69.462 0.859 69.48 ;
     RECT  0.175 70.344 0.859 70.56 ;
     RECT  0.823 72.162 0.895 72.72 ;
     RECT  0.859 69.462 1.111 70.56 ;
     RECT  0.247 57.69 1.147 59.058 ;
     RECT  0.031 60.12 1.147 60.138 ;
     RECT  0.031 62.712 1.147 62.73 ;
     RECT  0.643 64.602 1.147 65.43 ;
     RECT  1.111 69.264 1.147 70.56 ;
     RECT  0.823 51.21 1.399 51.228 ;
     RECT  1.435 73.512 1.471 73.53 ;
     RECT  1.399 74.322 1.471 74.34 ;
     RECT  0.895 71.892 1.615 72.72 ;
     RECT  1.471 73.512 1.615 74.34 ;
     RECT  1.147 62.442 1.687 65.43 ;
     RECT  1.759 60.93 1.795 60.948 ;
     RECT  1.147 57.69 1.831 60.138 ;
     RECT  1.795 60.93 1.831 61.218 ;
     RECT  1.831 57.69 1.867 61.218 ;
     RECT  0.859 54.45 1.975 54.468 ;
     RECT  1.615 71.892 1.975 74.34 ;
     RECT  1.975 54.45 2.011 54.594 ;
     RECT  1.975 71.622 2.047 74.34 ;
     RECT  1.399 51.21 2.16 51.768 ;
     RECT  0.139 53.37 2.16 53.388 ;
     RECT  2.011 54.45 2.16 55.008 ;
     RECT  1.867 57.69 2.16 61.488 ;
     RECT  1.687 62.442 2.16 66.078 ;
     RECT  1.255 67.302 2.16 67.32 ;
     RECT  1.147 68.652 2.16 70.56 ;
     RECT  2.047 71.352 2.16 74.34 ;
     RECT  73.615 0.036 84.047 0.054 ;
     RECT  2.16 2.151 117.828 117.729 ;
     RECT  117.828 59.616 118.283 60.174 ;
     RECT  118.283 60.156 118.319 60.174 ;
     RECT  117.828 63.126 118.391 63.144 ;
     RECT  117.828 66.456 118.427 68.166 ;
     RECT  118.427 66.456 118.463 66.474 ;
     RECT  118.427 67.644 118.499 68.166 ;
     RECT  117.828 72.774 118.607 74.304 ;
     RECT  117.828 56.646 118.859 56.664 ;
     RECT  118.499 68.148 118.895 68.166 ;
     RECT  118.607 72.936 119.111 74.304 ;
     RECT  119.111 72.936 119.147 74.214 ;
     RECT  117.828 70.416 119.183 70.974 ;
     RECT  119.147 73.116 119.831 74.214 ;
     RECT  119.183 70.416 119.867 70.794 ;
     RECT  119.831 73.386 119.867 74.214 ;
     RECT  119.867 73.386 119.903 73.404 ;
     RECT  119.867 74.196 119.903 74.214 ;
     RECT  117.828 65.52 119.939 65.538 ;
     RECT  119.867 70.614 119.939 70.794 ;
     RECT  117.828 61.776 119.975 61.794 ;
     RECT  119.939 70.614 119.975 70.632 ;
    LAYER M3 ;
     RECT  84.024 0.031 84.042 0.043 ;
     RECT  83.952 0.043 84.042 0.125 ;
     RECT  82.584 0.091 83.034 0.139 ;
     RECT  83.952 0.125 83.97 0.173 ;
     RECT  82.476 0.139 83.034 0.187 ;
     RECT  80.928 0.139 80.946 0.427 ;
     RECT  82.044 0.187 83.034 0.427 ;
     RECT  79.668 0.523 79.686 1.051 ;
     RECT  79.128 1.051 79.686 1.099 ;
     RECT  80.928 0.427 83.034 1.147 ;
     RECT  80.928 1.147 83.322 1.195 ;
     RECT  78.804 1.099 79.686 2.143 ;
     RECT  80.928 1.195 83.574 2.251 ;
     RECT  2.415 2.143 2.505 2.413 ;
     RECT  7.815 2.143 7.905 2.413 ;
     RECT  13.215 2.143 13.305 2.413 ;
     RECT  18.615 2.143 18.705 2.413 ;
     RECT  24.015 2.143 24.105 2.413 ;
     RECT  29.415 2.143 29.505 2.413 ;
     RECT  34.815 2.143 34.905 2.413 ;
     RECT  40.215 2.143 40.305 2.413 ;
     RECT  45.615 2.143 45.705 2.413 ;
     RECT  51.015 2.143 51.105 2.413 ;
     RECT  56.415 2.143 56.505 2.413 ;
     RECT  61.815 2.143 61.905 2.413 ;
     RECT  67.215 2.143 67.305 2.413 ;
     RECT  72.615 2.143 72.705 2.413 ;
     RECT  88.815 2.143 88.905 2.413 ;
     RECT  94.215 2.143 94.305 2.413 ;
     RECT  99.615 2.143 99.705 2.413 ;
     RECT  105.015 2.143 105.105 2.413 ;
     RECT  110.415 2.143 110.505 2.413 ;
     RECT  115.815 2.143 115.905 2.413 ;
     RECT  78.015 2.143 79.686 2.731 ;
     RECT  80.928 2.251 83.754 2.831 ;
     RECT  76.068 0.091 76.086 3.001 ;
     RECT  81.036 2.831 83.754 3.019 ;
     RECT  76.068 3.001 76.662 3.065 ;
     RECT  78.015 2.731 80.082 3.181 ;
     RECT  85.032 2.263 85.05 3.181 ;
     RECT  77.4 3.181 80.082 3.335 ;
     RECT  84.708 3.181 85.05 3.343 ;
     RECT  84.636 3.343 85.05 3.379 ;
     RECT  73.62 0.031 73.638 3.569 ;
     RECT  75.204 0.043 75.222 3.569 ;
     RECT  77.904 3.335 80.082 3.605 ;
     RECT  81.036 3.019 83.898 3.721 ;
     RECT  84.636 3.379 85.338 3.721 ;
     RECT  81.036 3.721 85.338 3.991 ;
     RECT  73.728 3.721 73.746 4.621 ;
     RECT  75.096 3.685 75.114 4.649 ;
     RECT  73.62 4.621 73.746 4.801 ;
     RECT  79.02 3.605 80.082 4.891 ;
     RECT  80.82 3.991 85.338 4.891 ;
     RECT  79.02 4.891 85.338 6.853 ;
     RECT  79.02 6.853 85.446 7.087 ;
     RECT  87.12 7.231 87.138 7.349 ;
     RECT  79.02 7.087 85.698 7.465 ;
     RECT  79.02 7.465 86.022 7.805 ;
     RECT  79.02 7.805 85.626 7.889 ;
     RECT  76.176 3.065 76.662 10.831 ;
     RECT  79.02 7.889 85.446 10.939 ;
     RECT  79.02 10.939 85.482 11.011 ;
     RECT  79.02 11.011 85.554 11.129 ;
     RECT  79.02 11.129 85.482 11.399 ;
     RECT  76.104 10.831 76.662 12.181 ;
     RECT  75.024 8.131 75.042 12.217 ;
     RECT  74.736 12.217 75.042 12.361 ;
     RECT  79.02 11.399 85.446 12.361 ;
     RECT  75.816 12.181 76.662 12.479 ;
     RECT  79.02 12.361 85.554 12.479 ;
     RECT  73.62 4.801 73.926 12.487 ;
     RECT  74.7 12.361 75.042 12.487 ;
     RECT  77.904 3.605 78.297 12.829 ;
     RECT  79.02 12.479 85.446 12.829 ;
     RECT  75.852 12.479 76.662 12.901 ;
     RECT  77.904 12.829 85.446 12.901 ;
     RECT  75.852 12.901 85.446 12.929 ;
     RECT  75.852 12.929 78.297 12.941 ;
     RECT  76.104 12.941 78.297 13.127 ;
     RECT  79.02 12.929 85.446 14.819 ;
     RECT  72.615 2.413 72.897 15.295 ;
     RECT  73.62 12.487 75.042 15.295 ;
     RECT  72.615 15.295 75.042 15.341 ;
     RECT  76.176 13.127 78.297 16.375 ;
     RECT  79.02 14.819 85.338 16.375 ;
     RECT  72.615 15.341 72.897 16.501 ;
     RECT  73.62 15.341 75.042 16.501 ;
     RECT  72.615 16.501 75.042 16.541 ;
     RECT  76.176 16.375 85.338 16.799 ;
     RECT  73.62 16.541 75.042 17.851 ;
     RECT  79.02 16.799 85.338 18.301 ;
     RECT  79.02 18.301 85.806 18.689 ;
     RECT  84.492 18.689 85.806 18.725 ;
     RECT  76.176 16.799 78.297 18.769 ;
     RECT  73.62 17.851 75.15 18.797 ;
     RECT  74.772 18.797 75.15 18.833 ;
     RECT  84.564 18.725 85.806 18.833 ;
     RECT  76.068 18.769 78.297 19.651 ;
     RECT  76.032 19.651 78.297 19.709 ;
     RECT  76.068 19.709 78.297 19.805 ;
     RECT  74.916 18.833 75.15 19.885 ;
     RECT  72.615 16.541 72.897 19.921 ;
     RECT  74.772 19.885 75.15 20.039 ;
     RECT  84.636 18.833 85.806 20.119 ;
     RECT  74.916 20.039 75.15 20.191 ;
     RECT  84.636 20.119 85.878 20.191 ;
     RECT  77.472 19.805 78.297 20.885 ;
     RECT  74.916 20.191 75.186 21.191 ;
     RECT  72.216 19.921 72.897 21.235 ;
     RECT  73.62 18.797 73.926 21.235 ;
     RECT  79.02 18.689 83.697 21.361 ;
     RECT  79.02 21.361 83.79 21.397 ;
     RECT  84.636 20.191 86.058 21.397 ;
     RECT  76.068 19.805 76.626 22.271 ;
     RECT  77.508 20.885 78.297 22.351 ;
     RECT  79.02 21.397 86.058 22.351 ;
     RECT  77.508 22.351 86.058 22.505 ;
     RECT  75.168 21.191 75.186 22.549 ;
     RECT  74.844 22.549 75.186 22.819 ;
     RECT  72.216 21.235 73.926 22.891 ;
     RECT  74.664 22.819 75.186 22.891 ;
     RECT  76.104 22.271 76.626 22.981 ;
     RECT  72.216 22.891 75.186 23.009 ;
     RECT  75.168 23.009 75.186 23.017 ;
     RECT  72.216 23.009 74.394 23.083 ;
     RECT  77.508 22.505 83.697 23.117 ;
     RECT  71.64 23.083 74.394 23.279 ;
     RECT  71.64 23.279 72.897 23.315 ;
     RECT  75.168 23.017 75.222 23.359 ;
     RECT  76.104 22.981 76.734 23.359 ;
     RECT  84.636 22.505 86.058 25.051 ;
     RECT  84.636 25.051 86.634 25.349 ;
     RECT  75.168 23.359 76.734 25.889 ;
     RECT  84.636 25.349 86.094 26.321 ;
     RECT  75.168 25.889 75.186 27.211 ;
     RECT  76.032 25.889 76.734 27.211 ;
     RECT  77.904 23.117 83.697 27.481 ;
     RECT  75.168 27.211 76.734 28.301 ;
     RECT  77.796 27.481 83.697 29.327 ;
     RECT  84.636 26.321 86.058 29.597 ;
     RECT  79.776 29.327 83.697 29.759 ;
     RECT  82.152 29.759 83.697 29.939 ;
     RECT  84.852 29.597 86.058 30.065 ;
     RECT  77.796 29.327 78.642 30.271 ;
     RECT  79.776 29.759 81.378 30.271 ;
     RECT  84.924 30.065 86.058 30.335 ;
     RECT  77.796 30.271 81.378 30.451 ;
     RECT  76.068 28.301 76.734 30.749 ;
     RECT  77.688 30.451 81.378 30.989 ;
     RECT  71.784 23.315 72.897 31.225 ;
     RECT  73.62 23.279 74.394 31.225 ;
     RECT  77.796 30.989 81.378 31.261 ;
     RECT  82.188 29.939 83.697 31.261 ;
     RECT  84.96 30.335 86.058 32.341 ;
     RECT  77.796 31.261 83.697 32.459 ;
     RECT  76.068 30.749 76.626 32.503 ;
     RECT  75.168 28.301 75.186 32.539 ;
     RECT  75.96 32.503 76.626 32.539 ;
     RECT  84.852 32.341 86.058 32.845 ;
     RECT  84.78 32.845 86.058 32.999 ;
     RECT  84.852 32.999 86.058 33.053 ;
     RECT  84.888 33.053 86.058 33.845 ;
     RECT  77.796 32.459 82.566 34.231 ;
     RECT  83.34 32.459 83.697 34.231 ;
     RECT  75.168 32.539 76.626 34.655 ;
     RECT  77.796 34.231 83.697 34.763 ;
     RECT  75.924 34.655 76.626 34.799 ;
     RECT  77.976 34.763 83.697 34.889 ;
     RECT  84.924 33.845 86.058 35.231 ;
     RECT  78.015 34.889 83.697 35.429 ;
     RECT  82.08 35.429 83.697 35.699 ;
     RECT  82.152 35.699 83.697 35.771 ;
     RECT  85.32 35.231 86.058 36.823 ;
     RECT  85.176 36.823 86.058 36.859 ;
     RECT  75.96 34.799 76.626 37.157 ;
     RECT  75.96 37.157 76.554 37.327 ;
     RECT  75.924 37.327 76.554 37.427 ;
     RECT  71.784 31.225 74.394 37.429 ;
     RECT  75.168 34.655 75.186 37.429 ;
     RECT  84.924 36.859 86.058 37.741 ;
     RECT  75.996 37.427 76.554 37.895 ;
     RECT  82.188 35.771 83.697 37.939 ;
     RECT  78.015 35.429 81.306 38.201 ;
     RECT  82.08 37.939 83.697 38.273 ;
     RECT  71.784 37.429 75.186 38.551 ;
     RECT  82.116 38.273 83.697 38.551 ;
     RECT  84.924 37.741 86.094 38.551 ;
     RECT  78.015 38.201 80.658 38.749 ;
     RECT  82.116 38.551 86.094 38.777 ;
     RECT  71.784 38.551 75.222 38.821 ;
     RECT  76.104 37.895 76.554 38.821 ;
     RECT  84.924 38.777 86.094 38.849 ;
     RECT  71.784 38.821 76.554 38.939 ;
     RECT  77.58 38.749 80.658 38.947 ;
     RECT  75.096 38.939 76.554 39.047 ;
     RECT  77.472 38.947 80.658 39.083 ;
     RECT  85.536 38.849 86.094 39.091 ;
     RECT  75.096 39.047 75.186 39.209 ;
     RECT  75.996 39.047 76.554 39.245 ;
     RECT  76.176 39.245 76.554 39.281 ;
     RECT  82.116 38.777 83.697 39.361 ;
     RECT  71.784 38.939 73.926 39.587 ;
     RECT  81.972 39.361 83.697 39.821 ;
     RECT  82.188 39.821 83.697 39.857 ;
     RECT  75.168 39.209 75.186 40.171 ;
     RECT  74.916 40.171 75.186 40.289 ;
     RECT  78.015 39.083 80.622 40.289 ;
     RECT  71.784 39.587 73.638 40.333 ;
     RECT  74.988 40.289 75.186 40.361 ;
     RECT  71.784 40.333 73.998 40.559 ;
     RECT  71.784 40.559 73.638 40.567 ;
     RECT  71.532 40.567 73.638 40.675 ;
     RECT  71.46 40.675 73.638 41.071 ;
     RECT  71.172 41.071 73.638 41.377 ;
     RECT  71.1 41.377 73.638 41.521 ;
     RECT  70.992 41.521 73.638 41.791 ;
     RECT  85.536 39.091 86.13 42.379 ;
     RECT  85.248 42.379 86.13 42.421 ;
     RECT  84.744 42.421 86.13 42.461 ;
     RECT  85.248 42.461 86.13 42.719 ;
     RECT  70.236 41.791 73.638 43.637 ;
     RECT  70.236 43.637 71.55 43.853 ;
     RECT  40.215 2.413 40.497 44.347 ;
     RECT  40.032 44.347 40.497 44.419 ;
     RECT  47.844 44.221 48.51 44.455 ;
     RECT  47.844 44.455 48.906 44.879 ;
     RECT  47.844 44.879 48.762 45.023 ;
     RECT  45.615 2.413 45.897 45.157 ;
     RECT  40.032 44.419 41.022 45.265 ;
     RECT  44.208 45.157 44.226 45.265 ;
     RECT  39.924 45.265 41.022 45.301 ;
     RECT  44.208 45.265 44.37 45.301 ;
     RECT  45.615 45.157 45.99 45.301 ;
     RECT  45.615 45.301 46.098 45.427 ;
     RECT  39.924 45.301 41.238 45.571 ;
     RECT  47.844 45.023 48.474 45.959 ;
     RECT  70.344 43.853 71.55 45.959 ;
     RECT  39.852 45.571 41.238 46.003 ;
     RECT  48.168 45.959 48.474 46.003 ;
     RECT  45.615 45.427 46.206 46.075 ;
     RECT  46.944 45.301 46.962 46.075 ;
     RECT  39.852 46.003 41.634 46.201 ;
     RECT  43.992 45.301 44.37 46.201 ;
     RECT  51.015 2.413 51.297 46.201 ;
     RECT  39.492 46.201 41.634 46.229 ;
     RECT  39.492 46.229 40.59 46.237 ;
     RECT  48.168 46.003 48.51 46.237 ;
     RECT  43.992 46.201 44.442 46.253 ;
     RECT  39.42 46.237 40.59 46.309 ;
     RECT  43.992 46.253 44.262 46.337 ;
     RECT  45.615 46.075 46.962 46.337 ;
     RECT  49.68 44.851 49.698 46.337 ;
     RECT  41.328 46.229 41.634 46.345 ;
     RECT  43.992 46.337 44.154 46.345 ;
     RECT  17.532 46.345 17.55 46.381 ;
     RECT  18.615 2.413 18.897 46.381 ;
     RECT  24.015 2.413 24.297 46.381 ;
     RECT  50.832 46.201 51.297 46.381 ;
     RECT  46.728 46.337 46.962 46.409 ;
     RECT  72.36 43.637 73.638 46.409 ;
     RECT  13.215 2.413 13.497 46.471 ;
     RECT  28.512 46.381 28.53 46.499 ;
     RECT  46.8 46.409 46.962 46.499 ;
     RECT  23.112 46.345 23.13 46.507 ;
     RECT  48.168 46.237 48.546 46.507 ;
     RECT  50.724 46.381 51.297 46.535 ;
     RECT  55.656 46.381 55.674 46.535 ;
     RECT  22.824 46.507 23.13 46.543 ;
     RECT  23.904 46.381 24.297 46.543 ;
     RECT  25.632 46.381 25.65 46.543 ;
     RECT  54.792 46.543 54.81 46.579 ;
     RECT  13.104 46.471 13.497 46.615 ;
     RECT  22.824 46.543 24.297 46.615 ;
     RECT  54.792 46.579 54.882 46.615 ;
     RECT  18.615 46.381 20.286 46.651 ;
     RECT  22.824 46.615 24.354 46.651 ;
     RECT  25.632 46.543 25.686 46.651 ;
     RECT  54.756 46.615 54.882 46.651 ;
     RECT  22.824 46.651 25.794 46.679 ;
     RECT  39.204 46.309 40.59 46.741 ;
     RECT  46.944 46.499 46.962 46.741 ;
     RECT  13.104 46.615 13.806 46.769 ;
     RECT  41.328 46.345 41.706 46.769 ;
     RECT  54.756 46.651 55.278 46.769 ;
     RECT  82.188 39.857 82.422 46.795 ;
     RECT  83.196 39.857 83.697 46.795 ;
     RECT  54.756 46.769 55.134 46.829 ;
     RECT  38.772 46.741 40.59 46.841 ;
     RECT  32.508 46.813 32.526 46.849 ;
     RECT  13.104 46.769 13.554 46.885 ;
     RECT  23.364 46.679 25.794 46.885 ;
     RECT  32.256 46.849 32.526 46.885 ;
     RECT  27.144 46.615 27.162 46.921 ;
     RECT  50.832 46.535 51.297 46.921 ;
     RECT  58.5 46.885 58.518 46.925 ;
     RECT  45.615 46.337 45.954 46.949 ;
     RECT  59.328 46.921 59.346 46.973 ;
     RECT  17.532 46.381 17.694 47.011 ;
     RECT  70.344 45.959 71.514 47.035 ;
     RECT  23.364 46.885 26.01 47.039 ;
     RECT  43.92 46.345 44.154 47.047 ;
     RECT  46.944 46.741 47.394 47.047 ;
     RECT  48.168 46.507 48.942 47.047 ;
     RECT  70.128 47.035 71.514 47.075 ;
     RECT  17.46 47.011 17.694 47.083 ;
     RECT  18.615 46.651 20.358 47.083 ;
     RECT  41.436 46.769 41.706 47.111 ;
     RECT  17.316 47.083 20.358 47.119 ;
     RECT  46.944 47.047 48.942 47.119 ;
     RECT  32.256 46.885 32.742 47.155 ;
     RECT  41.508 47.111 41.706 47.155 ;
     RECT  17.136 47.119 20.358 47.183 ;
     RECT  41.508 47.155 42.318 47.183 ;
     RECT  18.036 47.183 20.358 47.219 ;
     RECT  39.276 46.841 40.59 47.219 ;
     RECT  32.04 47.155 32.742 47.281 ;
     RECT  54.756 46.829 55.062 47.281 ;
     RECT  10.836 47.155 10.854 47.309 ;
     RECT  12.708 46.885 13.554 47.309 ;
     RECT  18.144 47.219 20.358 47.309 ;
     RECT  29.415 2.413 29.697 47.317 ;
     RECT  54.396 47.281 55.062 47.317 ;
     RECT  46.944 47.119 49.626 47.345 ;
     RECT  54.216 47.317 55.062 47.353 ;
     RECT  46.944 47.345 48.942 47.381 ;
     RECT  17.136 47.183 17.154 47.389 ;
     RECT  32.04 47.281 32.958 47.389 ;
     RECT  43.308 47.047 44.154 47.389 ;
     RECT  50.832 46.921 52.038 47.389 ;
     RECT  50.796 47.389 52.038 47.419 ;
     RECT  41.58 47.183 42.318 47.425 ;
     RECT  43.308 47.389 44.73 47.425 ;
     RECT  46.944 47.381 47.106 47.425 ;
     RECT  53.172 47.353 53.19 47.425 ;
     RECT  54.036 47.353 55.062 47.425 ;
     RECT  41.58 47.425 44.73 47.453 ;
     RECT  29.415 47.317 31.158 47.461 ;
     RECT  31.896 47.389 32.958 47.461 ;
     RECT  34.815 2.413 35.097 47.461 ;
     RECT  50.724 47.419 52.038 47.489 ;
     RECT  53.172 47.425 55.062 47.489 ;
     RECT  82.188 46.795 83.697 47.489 ;
     RECT  4.824 47.155 4.842 47.579 ;
     RECT  29.415 47.461 32.958 47.579 ;
     RECT  28.368 47.389 28.494 47.651 ;
     RECT  53.172 47.489 54.846 47.651 ;
     RECT  29.415 47.579 32.058 47.687 ;
     RECT  42.3 47.453 44.73 47.687 ;
     RECT  2.415 2.413 2.697 47.695 ;
     RECT  29.415 47.687 31.95 47.695 ;
     RECT  21.708 47.551 21.726 47.731 ;
     RECT  54.36 47.651 54.846 47.741 ;
     RECT  21.672 47.731 21.726 47.789 ;
     RECT  25.236 47.039 26.01 47.821 ;
     RECT  26.748 46.921 27.162 47.821 ;
     RECT  21.708 47.789 21.726 47.849 ;
     RECT  28.692 47.695 31.95 47.849 ;
     RECT  50.796 47.489 52.038 47.849 ;
     RECT  59.04 47.803 59.058 47.849 ;
     RECT  16.128 47.011 16.146 47.851 ;
     RECT  32.94 47.579 32.958 47.857 ;
     RECT  33.984 47.425 34.002 47.857 ;
     RECT  50.796 47.849 51.894 47.885 ;
     RECT  37.872 46.237 37.89 47.929 ;
     RECT  25.236 47.821 27.162 47.957 ;
     RECT  16.056 47.851 16.146 48.001 ;
     RECT  32.94 47.857 34.002 48.001 ;
     RECT  34.776 47.461 35.097 48.001 ;
     RECT  37.872 47.929 38.034 48.091 ;
     RECT  23.364 47.039 24.39 48.118 ;
     RECT  57.492 47.803 57.51 48.125 ;
     RECT  16.056 48.001 16.254 48.163 ;
     RECT  16.992 47.389 17.154 48.163 ;
     RECT  15.984 48.163 17.154 48.199 ;
     RECT  15.912 48.199 17.154 48.227 ;
     RECT  25.74 47.957 27.162 48.271 ;
     RECT  23.328 48.118 24.39 48.361 ;
     RECT  15.912 48.227 16.47 48.389 ;
     RECT  25.74 48.271 27.342 48.389 ;
     RECT  32.94 48.001 35.097 48.389 ;
     RECT  33.84 48.389 35.097 48.433 ;
     RECT  22.788 48.361 24.39 48.461 ;
     RECT  26.784 48.389 27.162 48.461 ;
     RECT  33.84 48.433 35.478 48.461 ;
     RECT  53.172 47.651 53.622 48.461 ;
     RECT  27.036 48.461 27.162 48.533 ;
     RECT  12.708 47.309 13.497 48.631 ;
     RECT  9.144 47.083 9.162 48.659 ;
     RECT  46.764 47.425 47.106 48.659 ;
     RECT  2.415 47.695 3.114 48.775 ;
     RECT  34.416 48.461 35.478 48.775 ;
     RECT  39.6 47.219 40.59 48.775 ;
     RECT  12.456 48.631 13.554 48.811 ;
     RECT  18.615 47.309 20.358 48.811 ;
     RECT  37.872 48.091 38.718 48.811 ;
     RECT  42.3 47.687 42.318 48.811 ;
     RECT  47.916 47.381 48.942 48.811 ;
     RECT  47.916 48.811 49.266 48.839 ;
     RECT  42.084 48.811 42.318 48.901 ;
     RECT  43.308 47.687 44.73 48.901 ;
     RECT  11.736 48.811 13.554 48.929 ;
     RECT  37.872 48.811 38.79 48.929 ;
     RECT  42.084 48.901 44.73 48.929 ;
     RECT  48.096 48.839 49.266 48.929 ;
     RECT  18.615 48.811 20.718 48.965 ;
     RECT  42.3 48.929 44.73 48.965 ;
     RECT  11.736 48.929 13.497 48.989 ;
     RECT  39.6 48.775 40.662 49.009 ;
     RECT  42.624 48.965 44.73 49.037 ;
     RECT  42.696 49.037 44.73 49.045 ;
     RECT  56.415 2.413 56.697 49.147 ;
     RECT  32.94 48.389 32.958 49.171 ;
     RECT  29.415 47.849 31.806 49.199 ;
     RECT  37.872 48.929 38.718 49.199 ;
     RECT  56.052 49.147 56.697 49.199 ;
     RECT  50.904 47.885 51.894 49.235 ;
     RECT  39.528 49.009 40.662 49.279 ;
     RECT  42.696 49.045 44.838 49.279 ;
     RECT  45.615 46.949 45.897 49.279 ;
     RECT  54.468 47.741 54.846 49.279 ;
     RECT  54.468 49.279 55.278 49.315 ;
     RECT  42.696 49.279 45.897 49.351 ;
     RECT  46.764 48.659 46.782 49.351 ;
     RECT  53.46 48.461 53.622 49.351 ;
     RECT  56.415 49.199 56.697 49.351 ;
     RECT  42.696 49.351 46.782 49.379 ;
     RECT  42.696 49.379 46.206 49.469 ;
     RECT  54.468 49.315 55.422 49.469 ;
     RECT  54.468 49.469 55.278 49.541 ;
     RECT  53.28 49.351 53.622 49.577 ;
     RECT  56.415 49.351 57.006 49.577 ;
     RECT  25.74 48.389 26.01 49.585 ;
     RECT  48.096 48.929 48.942 49.621 ;
     RECT  39.528 49.279 41.058 49.747 ;
     RECT  32.76 49.171 32.958 49.775 ;
     RECT  54.468 49.541 55.17 49.811 ;
     RECT  29.415 49.199 31.698 49.847 ;
     RECT  37.98 49.199 38.718 49.883 ;
     RECT  11.916 48.989 13.497 49.891 ;
     RECT  27.036 48.533 27.054 49.891 ;
     RECT  32.94 49.775 32.958 49.891 ;
     RECT  53.388 49.577 53.622 49.901 ;
     RECT  4.5 48.235 4.518 50.009 ;
     RECT  27.036 49.891 27.126 50.009 ;
     RECT  16.272 48.389 16.47 50.017 ;
     RECT  23.364 48.461 24.39 50.017 ;
     RECT  25.704 49.585 26.01 50.017 ;
     RECT  11.664 49.891 13.497 50.045 ;
     RECT  29.415 49.847 31.374 50.045 ;
     RECT  23.364 50.017 26.01 50.053 ;
     RECT  2.415 48.775 3.438 50.089 ;
     RECT  18.615 48.965 20.538 50.089 ;
     RECT  21.312 50.017 21.33 50.089 ;
     RECT  32.94 49.891 33.354 50.089 ;
     RECT  6.84 49.819 6.858 50.117 ;
     RECT  18.615 50.089 21.33 50.117 ;
     RECT  23.364 50.053 26.154 50.125 ;
     RECT  39.492 49.747 41.058 50.153 ;
     RECT  16.272 50.017 17.118 50.161 ;
     RECT  32.94 50.089 33.426 50.189 ;
     RECT  33.192 50.189 33.426 50.279 ;
     RECT  39.564 50.153 41.058 50.279 ;
     RECT  34.416 48.775 35.91 50.287 ;
     RECT  38.016 49.883 38.718 50.323 ;
     RECT  34.416 50.287 36.126 50.395 ;
     RECT  23.364 50.125 26.226 50.431 ;
     RECT  38.016 50.323 38.754 50.459 ;
     RECT  16.272 50.161 17.586 50.549 ;
     RECT  16.272 50.549 16.47 50.557 ;
     RECT  34.164 50.395 36.126 50.557 ;
     RECT  17.208 50.549 17.586 50.593 ;
     RECT  23.004 50.431 26.226 50.621 ;
     RECT  16.128 50.557 16.47 50.665 ;
     RECT  17.208 50.593 17.622 50.693 ;
     RECT  14.832 50.161 14.85 50.729 ;
     RECT  16.056 50.665 16.47 50.729 ;
     RECT  17.208 50.693 17.586 50.729 ;
     RECT  23.184 50.621 24.297 50.729 ;
     RECT  47.52 49.621 48.942 50.791 ;
     RECT  57.924 49.351 57.942 50.791 ;
     RECT  76.248 39.281 76.554 50.791 ;
     RECT  9.684 50.089 9.702 50.819 ;
     RECT  27.036 50.009 27.054 50.819 ;
     RECT  57.924 50.791 58.122 50.827 ;
     RECT  78.015 40.289 80.442 50.827 ;
     RECT  2.415 50.089 3.978 50.863 ;
     RECT  57.924 50.827 58.806 50.899 ;
     RECT  33.372 50.279 33.426 50.935 ;
     RECT  34.164 50.557 36.162 50.935 ;
     RECT  76.068 50.791 76.554 50.935 ;
     RECT  18.615 50.117 21.15 50.971 ;
     RECT  25.092 50.621 26.226 50.971 ;
     RECT  76.068 50.935 76.662 50.971 ;
     RECT  77.508 50.827 80.442 50.971 ;
     RECT  47.52 50.791 49.014 51.061 ;
     RECT  82.188 47.489 82.422 51.061 ;
     RECT  2.376 50.863 3.978 51.089 ;
     RECT  18.615 50.971 21.69 51.089 ;
     RECT  57.816 50.899 58.806 51.089 ;
     RECT  75.168 40.361 75.186 51.097 ;
     RECT  82.08 51.061 82.422 51.133 ;
     RECT  83.196 47.489 83.697 51.133 ;
     RECT  27.972 51.061 27.99 51.205 ;
     RECT  50.904 49.235 51.57 51.205 ;
     RECT  58.716 51.089 58.806 51.233 ;
     RECT  76.068 50.971 80.442 51.245 ;
     RECT  74.736 51.097 75.186 51.269 ;
     RECT  12.24 50.045 13.497 51.307 ;
     RECT  4.824 50.629 4.842 51.359 ;
     RECT  42.696 49.469 43.938 51.367 ;
     RECT  44.712 49.469 46.026 51.367 ;
     RECT  27.828 51.205 27.99 51.431 ;
     RECT  32.22 51.331 32.238 51.431 ;
     RECT  4.428 51.403 4.626 51.44 ;
     RECT  47.52 51.061 49.23 51.475 ;
     RECT  18.615 51.089 21.438 51.503 ;
     RECT  12.24 51.307 14.166 51.511 ;
     RECT  17.208 50.729 17.478 51.511 ;
     RECT  23.256 50.729 24.297 51.511 ;
     RECT  27.972 51.431 27.99 51.511 ;
     RECT  38.016 50.459 38.718 51.511 ;
     RECT  47.52 51.475 49.302 51.511 ;
     RECT  33.372 50.935 36.162 51.539 ;
     RECT  17.208 51.511 17.55 51.601 ;
     RECT  18.615 51.503 21.258 51.601 ;
     RECT  29.415 50.045 31.158 51.601 ;
     RECT  31.932 51.511 32.022 51.601 ;
     RECT  47.52 51.511 49.446 51.601 ;
     RECT  22.788 51.511 24.297 51.628 ;
     RECT  2.376 51.089 3.69 51.629 ;
     RECT  25.092 50.971 26.406 51.629 ;
     RECT  42.696 51.367 46.026 51.637 ;
     RECT  46.836 51.601 49.446 51.637 ;
     RECT  17.208 51.601 21.258 51.665 ;
     RECT  17.208 51.665 21.114 51.701 ;
     RECT  9.468 51.595 9.486 51.709 ;
     RECT  39.564 50.279 40.662 51.709 ;
     RECT  39.564 51.709 40.698 51.736 ;
     RECT  38.016 51.511 38.79 51.737 ;
     RECT  42.588 51.637 46.026 51.737 ;
     RECT  0.828 51.205 0.846 51.745 ;
     RECT  54.468 49.811 54.99 51.745 ;
     RECT  46.764 51.637 49.446 51.773 ;
     RECT  9.468 51.709 9.738 51.781 ;
     RECT  22.752 51.628 24.297 51.781 ;
     RECT  39.564 51.736 40.806 51.781 ;
     RECT  41.616 51.709 41.634 51.781 ;
     RECT  39.564 51.781 41.634 51.809 ;
     RECT  12.24 51.511 14.31 51.871 ;
     RECT  33.408 51.539 36.162 51.871 ;
     RECT  57.816 51.089 57.834 51.871 ;
     RECT  12.24 51.871 14.886 51.899 ;
     RECT  39.6 51.809 41.634 51.899 ;
     RECT  47.52 51.773 49.446 51.899 ;
     RECT  9.144 51.781 9.738 51.907 ;
     RECT  10.836 51.709 10.854 51.907 ;
     RECT  14.868 51.899 14.886 51.907 ;
     RECT  6.84 51.709 6.858 51.943 ;
     RECT  7.815 2.413 8.097 51.943 ;
     RECT  9.144 51.907 10.854 51.943 ;
     RECT  38.016 51.737 38.718 51.943 ;
     RECT  12.24 51.899 14.13 51.971 ;
     RECT  14.868 51.907 15.21 51.971 ;
     RECT  50.22 51.205 51.57 51.979 ;
     RECT  12.24 51.971 14.058 52.007 ;
     RECT  15.192 51.971 15.21 52.007 ;
     RECT  47.52 51.899 49.23 52.007 ;
     RECT  6.84 51.943 8.097 52.015 ;
     RECT  9 51.943 10.89 52.015 ;
     RECT  33.408 51.871 36.558 52.015 ;
     RECT  37.332 51.943 38.718 52.015 ;
     RECT  50.22 51.979 51.858 52.015 ;
     RECT  54.396 51.745 54.99 52.015 ;
     RECT  57.78 51.871 57.834 52.015 ;
     RECT  50.22 52.015 52.326 52.043 ;
     RECT  17.208 51.701 21.006 52.051 ;
     RECT  53.604 49.901 53.622 52.051 ;
     RECT  54.396 52.015 55.026 52.051 ;
     RECT  57.78 52.015 58.086 52.051 ;
     RECT  50.436 52.043 52.326 52.061 ;
     RECT  6.84 52.015 10.89 52.141 ;
     RECT  6.84 52.141 10.926 52.169 ;
     RECT  33.408 52.015 38.718 52.169 ;
     RECT  50.436 52.061 51.858 52.169 ;
     RECT  53.244 52.051 55.026 52.169 ;
     RECT  6.84 52.169 8.097 52.171 ;
     RECT  46.764 51.773 46.782 52.241 ;
     RECT  53.244 52.169 53.658 52.241 ;
     RECT  22.68 51.781 24.297 52.285 ;
     RECT  12.24 52.007 13.95 52.313 ;
     RECT  57.528 52.051 58.086 52.313 ;
     RECT  9 52.169 10.926 52.349 ;
     RECT  25.092 51.629 26.334 52.349 ;
     RECT  4.428 51.44 4.446 52.439 ;
     RECT  34.236 52.169 38.718 52.439 ;
     RECT  42.696 51.737 46.026 52.439 ;
     RECT  4.248 52.447 4.266 52.493 ;
     RECT  16.056 50.729 16.398 52.507 ;
     RECT  17.172 52.051 21.006 52.507 ;
     RECT  25.668 52.349 26.334 52.507 ;
     RECT  6.192 52.171 8.097 52.555 ;
     RECT  6.12 52.555 8.097 52.583 ;
     RECT  16.056 52.507 21.006 52.583 ;
     RECT  16.056 52.583 20.322 52.619 ;
     RECT  6.12 52.583 6.246 52.709 ;
     RECT  27.972 51.511 28.134 52.709 ;
     RECT  34.236 52.439 36.594 52.709 ;
     RECT  16.056 52.619 20.25 52.781 ;
     RECT  75.168 51.269 75.186 52.789 ;
     RECT  76.14 51.245 80.442 52.789 ;
     RECT  75.168 52.789 80.442 52.817 ;
     RECT  22.5 52.285 24.297 52.825 ;
     RECT  17.676 52.781 20.25 52.889 ;
     RECT  17.676 52.889 20.214 52.979 ;
     RECT  16.056 52.781 16.902 53.015 ;
     RECT  18.432 52.979 19.998 53.015 ;
     RECT  42.696 52.439 44.73 53.021 ;
     RECT  53.604 52.241 53.658 53.023 ;
     RECT  54.54 52.169 54.99 53.023 ;
     RECT  47.52 52.007 49.086 53.051 ;
     RECT  9.648 52.349 10.926 53.083 ;
     RECT  16.236 53.015 16.758 53.123 ;
     RECT  2.376 51.629 3.51 53.131 ;
     RECT  25.668 52.507 26.874 53.131 ;
     RECT  9.648 53.083 11.25 53.159 ;
     RECT  25.668 53.131 26.946 53.159 ;
     RECT  2.376 53.131 3.906 53.249 ;
     RECT  14.832 53.095 14.922 53.249 ;
     RECT  16.38 53.123 16.398 53.249 ;
     RECT  29.415 51.601 32.022 53.249 ;
     RECT  25.992 53.159 26.946 53.285 ;
     RECT  27.972 52.709 27.99 53.321 ;
     RECT  56.415 49.577 56.697 53.329 ;
     RECT  0.828 51.745 1.422 53.365 ;
     RECT  26.208 53.285 26.946 53.365 ;
     RECT  6.228 52.709 6.246 53.401 ;
     RECT  7.056 52.583 8.097 53.401 ;
     RECT  10.188 53.159 11.25 53.401 ;
     RECT  10.188 53.401 11.394 53.491 ;
     RECT  12.24 52.313 12.258 53.491 ;
     RECT  10.188 53.491 12.258 53.519 ;
     RECT  26.208 53.365 27.018 53.519 ;
     RECT  34.236 52.709 35.946 53.519 ;
     RECT  17.676 52.979 17.694 53.527 ;
     RECT  10.188 53.519 10.926 53.555 ;
     RECT  11.772 53.519 12.258 53.591 ;
     RECT  29.415 53.249 31.554 53.635 ;
     RECT  58.068 52.313 58.086 53.635 ;
     RECT  58.068 53.635 58.482 53.671 ;
     RECT  14.904 53.249 14.922 53.789 ;
     RECT  17.532 53.527 17.694 53.869 ;
     RECT  18.615 53.015 19.998 53.869 ;
     RECT  47.52 53.051 49.014 53.869 ;
     RECT  53.604 53.023 54.99 53.869 ;
     RECT  17.532 53.869 19.998 53.905 ;
     RECT  42.696 53.021 43.722 53.905 ;
     RECT  53.532 53.869 54.99 53.905 ;
     RECT  61.815 2.413 62.097 53.941 ;
     RECT  6.228 53.401 8.097 54.059 ;
     RECT  17.532 53.905 20.286 54.059 ;
     RECT  34.776 53.519 35.946 54.059 ;
     RECT  46.872 53.869 49.014 54.059 ;
     RECT  53.532 53.905 55.062 54.059 ;
     RECT  61.815 53.941 62.694 54.059 ;
     RECT  56.415 53.329 57.042 54.095 ;
     RECT  82.08 51.133 83.697 54.095 ;
     RECT  39.6 51.899 41.058 54.103 ;
     RECT  50.436 52.169 51.57 54.103 ;
     RECT  34.776 54.059 35.802 54.131 ;
     RECT  53.604 54.059 55.062 54.131 ;
     RECT  58.068 53.671 58.878 54.131 ;
     RECT  42.408 53.905 43.722 54.139 ;
     RECT  39.6 54.103 41.13 54.175 ;
     RECT  42.12 54.139 43.722 54.175 ;
     RECT  29.304 53.635 31.554 54.203 ;
     RECT  58.068 54.131 58.806 54.203 ;
     RECT  39.6 54.175 43.722 54.211 ;
     RECT  44.46 53.021 44.73 54.211 ;
     RECT  4.5 53.293 4.626 54.329 ;
     RECT  27.9 54.175 27.918 54.337 ;
     RECT  39.6 54.211 44.73 54.337 ;
     RECT  27.432 54.337 27.918 54.365 ;
     RECT  39.6 54.337 44.766 54.481 ;
     RECT  45.615 52.439 46.026 54.481 ;
     RECT  0.144 53.365 1.422 54.571 ;
     RECT  2.376 53.249 3.51 54.571 ;
     RECT  54.72 54.131 55.062 54.571 ;
     RECT  34.776 54.131 35.55 54.607 ;
     RECT  39.6 54.481 46.026 54.635 ;
     RECT  13.215 52.313 13.95 54.643 ;
     RECT  29.415 54.203 31.554 54.679 ;
     RECT  33.408 52.169 33.426 54.679 ;
     RECT  82.116 54.095 83.697 54.707 ;
     RECT  53.604 54.131 53.694 54.743 ;
     RECT  22.284 52.825 24.297 54.751 ;
     RECT  29.415 54.679 31.662 54.751 ;
     RECT  33.408 54.679 33.93 54.751 ;
     RECT  34.668 54.607 35.55 54.751 ;
     RECT  15.084 54.715 15.102 54.841 ;
     RECT  22.284 54.751 24.534 54.841 ;
     RECT  26.208 53.519 26.37 54.841 ;
     RECT  22.284 54.841 26.37 54.869 ;
     RECT  12.24 53.591 12.258 54.877 ;
     RECT  13.215 54.643 14.022 54.877 ;
     RECT  14.796 54.841 15.102 54.877 ;
     RECT  12.24 54.877 15.102 54.905 ;
     RECT  33.408 54.751 35.55 54.913 ;
     RECT  10.224 53.555 10.926 54.949 ;
     RECT  39.6 54.635 44.802 54.977 ;
     RECT  12.492 54.905 15.102 54.985 ;
     RECT  29.415 54.751 32.346 55.021 ;
     RECT  33.336 54.913 35.55 55.021 ;
     RECT  0.144 54.571 3.51 55.049 ;
     RECT  39.6 54.977 41.202 55.049 ;
     RECT  10.116 54.949 10.962 55.111 ;
     RECT  29.415 55.021 35.55 55.111 ;
     RECT  5.796 54.571 5.814 55.139 ;
     RECT  12.492 54.985 15.21 55.139 ;
     RECT  42.12 54.977 44.802 55.139 ;
     RECT  37.332 52.439 38.718 55.147 ;
     RECT  39.6 55.049 40.497 55.147 ;
     RECT  10.008 55.111 10.962 55.175 ;
     RECT  29.415 55.111 36.27 55.211 ;
     RECT  10.008 55.175 10.89 55.247 ;
     RECT  17.532 54.059 19.746 55.255 ;
     RECT  15.084 55.139 15.102 55.283 ;
     RECT  58.068 54.203 58.374 55.283 ;
     RECT  4.5 54.329 4.518 55.291 ;
     RECT  6.804 54.059 8.097 55.291 ;
     RECT  16.812 55.255 19.746 55.319 ;
     RECT  6.336 55.291 8.097 55.409 ;
     RECT  4.5 55.291 4.95 55.525 ;
     RECT  4.5 55.525 5.238 55.561 ;
     RECT  78.015 52.817 80.442 55.561 ;
     RECT  3.96 55.561 5.238 55.565 ;
     RECT  3.96 55.565 4.95 55.679 ;
     RECT  33.048 55.211 36.27 55.679 ;
     RECT  78.015 55.561 80.622 55.759 ;
     RECT  75.168 52.817 77.238 55.823 ;
     RECT  33.336 55.679 36.27 55.831 ;
     RECT  117.468 55.687 117.486 55.831 ;
     RECT  75.96 55.823 77.238 55.859 ;
     RECT  22.284 54.869 26.226 55.921 ;
     RECT  50.436 54.103 51.75 55.921 ;
     RECT  78.015 55.759 80.694 55.949 ;
     RECT  21.924 55.921 26.226 55.957 ;
     RECT  53.64 54.743 53.694 55.957 ;
     RECT  54.72 54.571 55.458 55.957 ;
     RECT  58.176 55.283 58.374 55.957 ;
     RECT  78.015 55.949 80.55 55.985 ;
     RECT  16.812 55.319 17.658 55.993 ;
     RECT  76.032 55.859 77.238 56.021 ;
     RECT  42.732 55.139 44.802 56.029 ;
     RECT  45.615 54.635 46.026 56.029 ;
     RECT  50.436 55.921 52.218 56.029 ;
     RECT  53.64 55.957 55.458 56.029 ;
     RECT  46.764 55.921 46.782 56.057 ;
     RECT  58.176 55.957 58.734 56.057 ;
     RECT  10.008 55.247 10.242 56.065 ;
     RECT  16.74 55.993 17.658 56.065 ;
     RECT  29.415 55.211 32.274 56.093 ;
     RECT  50.436 56.029 52.254 56.093 ;
     RECT  10.008 56.065 10.962 56.101 ;
     RECT  12.492 55.139 14.166 56.101 ;
     RECT  16.74 56.065 17.802 56.101 ;
     RECT  9.72 56.101 10.962 56.129 ;
     RECT  53.604 56.029 55.638 56.191 ;
     RECT  56.415 54.095 56.697 56.191 ;
     RECT  16.668 56.101 17.802 56.219 ;
     RECT  50.436 56.093 52.218 56.219 ;
     RECT  16.668 56.219 17.658 56.227 ;
     RECT  21.528 55.957 26.226 56.227 ;
     RECT  117.324 55.831 117.486 56.255 ;
     RECT  37.332 55.147 40.497 56.263 ;
     RECT  53.604 56.191 56.697 56.327 ;
     RECT  10.944 56.129 10.962 56.371 ;
     RECT  10.944 56.371 11.322 56.399 ;
     RECT  11.304 56.399 11.322 56.429 ;
     RECT  53.604 56.327 53.694 56.489 ;
     RECT  117.432 56.255 117.486 56.525 ;
     RECT  12.492 56.101 14.67 56.569 ;
     RECT  18.615 55.319 19.746 56.569 ;
     RECT  16.596 56.227 17.658 56.597 ;
     RECT  27.432 54.365 27.45 56.641 ;
     RECT  37.26 56.263 40.497 56.731 ;
     RECT  9.72 56.129 10.134 56.759 ;
     RECT  12.492 56.569 14.85 56.831 ;
     RECT  12.492 56.831 14.598 56.867 ;
     RECT  18.615 56.569 19.818 57.001 ;
     RECT  21.528 56.227 26.622 57.001 ;
     RECT  50.436 56.219 51.75 57.001 ;
     RECT  12.492 56.867 14.526 57.029 ;
     RECT  21.096 57.001 26.622 57.064 ;
     RECT  27.36 56.641 27.45 57.064 ;
     RECT  21.096 57.064 27.45 57.101 ;
     RECT  54.684 56.327 56.697 57.145 ;
     RECT  21.096 57.101 26.622 57.173 ;
     RECT  27.36 57.101 27.45 57.181 ;
     RECT  28.224 56.875 28.242 57.181 ;
     RECT  58.176 56.057 58.374 57.181 ;
     RECT  21.096 57.173 26.226 57.209 ;
     RECT  50.436 57.001 51.822 57.271 ;
     RECT  16.74 56.597 17.658 57.299 ;
     RECT  21.564 57.209 26.226 57.299 ;
     RECT  4.176 55.679 4.95 57.451 ;
     RECT  33.336 55.831 36.378 57.451 ;
     RECT  37.26 56.731 41.058 57.451 ;
     RECT  58.176 57.181 58.41 57.451 ;
     RECT  50.436 57.271 52.398 57.541 ;
     RECT  53.604 56.489 53.622 57.541 ;
     RECT  54.36 57.145 56.697 57.541 ;
     RECT  29.415 56.093 31.626 57.577 ;
     RECT  58.176 57.451 58.446 57.641 ;
     RECT  47.52 54.059 49.014 57.649 ;
     RECT  50.184 57.541 52.398 57.677 ;
     RECT  78.015 55.985 80.442 57.713 ;
     RECT  4.176 57.451 5.562 57.721 ;
     RECT  6.444 55.409 8.097 57.721 ;
     RECT  46.764 57.649 49.014 57.721 ;
     RECT  32.976 57.451 41.058 57.749 ;
     RECT  4.176 57.721 8.19 57.811 ;
     RECT  42.732 56.029 46.026 57.811 ;
     RECT  82.26 54.707 83.697 57.811 ;
     RECT  21.78 57.299 26.226 57.839 ;
     RECT  46.764 57.721 49.338 57.839 ;
     RECT  32.976 57.749 40.497 57.883 ;
     RECT  42.408 57.811 46.026 57.919 ;
     RECT  0.144 55.049 3.222 57.955 ;
     RECT  4.176 57.811 8.838 57.983 ;
     RECT  86.976 51.133 86.994 57.991 ;
     RECT  53.604 57.541 56.697 58.019 ;
     RECT  85.536 42.719 86.13 58.081 ;
     RECT  5.868 57.983 8.838 58.109 ;
     RECT  10.8 57.991 10.818 58.109 ;
     RECT  32.472 57.883 40.497 58.109 ;
     RECT  9.72 56.759 9.738 58.117 ;
     RECT  18.615 57.001 19.89 58.117 ;
     RECT  27.36 57.181 28.242 58.117 ;
     RECT  42.372 57.919 46.026 58.117 ;
     RECT  82.26 57.811 84.222 58.117 ;
     RECT  5.868 58.109 8.262 58.145 ;
     RECT  82.26 58.117 84.618 58.154 ;
     RECT  42.372 58.117 46.098 58.157 ;
     RECT  42.372 58.157 46.026 58.181 ;
     RECT  84.456 58.154 84.618 58.189 ;
     RECT  88.815 2.413 89.097 58.189 ;
     RECT  86.904 57.991 86.994 58.219 ;
     RECT  4.176 57.983 4.95 58.253 ;
     RECT  27.036 58.117 28.242 58.261 ;
     RECT  12.492 57.029 14.094 58.351 ;
     RECT  79.776 57.713 80.442 58.351 ;
     RECT  115.815 2.413 116.097 58.351 ;
     RECT  4.176 58.253 4.842 58.379 ;
     RECT  12.492 58.351 14.274 58.379 ;
     RECT  27.036 58.261 28.638 58.379 ;
     RECT  42.372 58.181 44.802 58.379 ;
     RECT  85.5 58.081 86.13 58.379 ;
     RECT  86.904 58.219 87.426 58.415 ;
     RECT  26.208 57.839 26.226 58.423 ;
     RECT  27.036 58.379 28.35 58.423 ;
     RECT  82.26 58.154 83.697 58.459 ;
     RECT  29.415 57.577 31.698 58.487 ;
     RECT  88.416 58.189 89.097 58.507 ;
     RECT  26.208 58.423 28.35 58.523 ;
     RECT  9.144 58.117 9.738 58.531 ;
     RECT  10.548 58.261 10.782 58.531 ;
     RECT  12.6 58.379 14.274 58.531 ;
     RECT  18.615 58.117 20.178 58.531 ;
     RECT  79.776 58.351 80.874 58.531 ;
     RECT  117.432 56.525 117.45 58.531 ;
     RECT  115.74 58.351 116.097 58.621 ;
     RECT  42.372 58.379 44.73 58.649 ;
     RECT  79.668 58.531 81.162 58.649 ;
     RECT  9.144 58.531 10.782 58.685 ;
     RECT  32.472 58.109 36.594 58.685 ;
     RECT  84.456 58.189 84.726 58.685 ;
     RECT  88.236 58.507 89.097 58.685 ;
     RECT  79.668 58.649 80.982 58.691 ;
     RECT  76.068 56.021 77.238 58.693 ;
     RECT  78.015 57.713 78.858 58.693 ;
     RECT  12.6 58.531 14.346 58.721 ;
     RECT  47.016 57.839 49.014 58.721 ;
     RECT  84.564 58.685 84.726 58.721 ;
     RECT  9.144 58.685 10.602 58.757 ;
     RECT  9.144 58.757 10.458 58.793 ;
     RECT  82.08 58.459 83.697 58.801 ;
     RECT  84.564 58.721 84.582 58.829 ;
     RECT  6.84 58.145 8.262 58.919 ;
     RECT  115.704 58.621 116.097 58.927 ;
     RECT  81.936 58.801 83.697 58.955 ;
     RECT  47.016 58.721 48.942 58.963 ;
     RECT  7.815 58.919 8.262 58.991 ;
     RECT  9.144 58.793 10.35 58.991 ;
     RECT  9.144 58.991 10.314 59.027 ;
     RECT  82.152 58.955 83.697 59.027 ;
     RECT  0.108 57.955 3.222 59.035 ;
     RECT  50.436 57.677 52.398 59.035 ;
     RECT  46.764 58.963 48.942 59.063 ;
     RECT  0.072 59.035 3.222 59.071 ;
     RECT  76.068 58.693 78.858 59.071 ;
     RECT  79.668 58.691 80.442 59.071 ;
     RECT  117.432 58.531 117.486 59.071 ;
     RECT  6.84 58.919 6.93 59.099 ;
     RECT  7.815 58.991 8.19 59.099 ;
     RECT  18.615 58.531 20.214 59.161 ;
     RECT  21.78 57.839 25.038 59.161 ;
     RECT  53.604 58.019 53.622 59.161 ;
     RECT  54.72 58.019 56.697 59.161 ;
     RECT  12.6 58.721 14.094 59.189 ;
     RECT  37.62 58.109 40.497 59.225 ;
     RECT  76.068 59.071 80.442 59.225 ;
     RECT  50.436 59.035 52.506 59.261 ;
     RECT  50.436 59.261 52.47 59.333 ;
     RECT  4.176 58.379 4.518 59.459 ;
     RECT  5.94 58.145 6.102 59.459 ;
     RECT  102.132 58.387 102.15 59.495 ;
     RECT  26.208 58.523 26.226 59.539 ;
     RECT  0.072 59.071 3.366 59.575 ;
     RECT  18.615 59.161 25.038 59.611 ;
     RECT  26.028 59.539 26.226 59.611 ;
     RECT  80.208 59.225 80.442 59.611 ;
     RECT  117.432 59.071 117.702 59.611 ;
     RECT  118.836 56.641 118.854 59.611 ;
     RECT  9.144 59.027 9.162 59.729 ;
     RECT  50.436 59.333 52.434 59.729 ;
     RECT  16.74 57.299 17.622 59.737 ;
     RECT  18.615 59.611 26.226 59.737 ;
     RECT  115.704 58.927 116.514 59.765 ;
     RECT  16.74 59.737 26.226 59.801 ;
     RECT  0.072 59.575 3.438 59.809 ;
     RECT  53.604 59.161 56.697 59.809 ;
     RECT  13.215 59.189 14.094 59.851 ;
     RECT  17.496 59.801 26.226 59.909 ;
     RECT  29.415 58.487 31.662 59.971 ;
     RECT  32.472 58.685 35.097 59.971 ;
     RECT  50.436 59.729 52.398 59.971 ;
     RECT  50.112 59.971 52.398 60.007 ;
     RECT  61.815 54.059 62.097 60.007 ;
     RECT  69.516 59.809 69.534 60.007 ;
     RECT  68.976 60.007 69.534 60.035 ;
     RECT  102.348 59.611 102.366 60.035 ;
     RECT  61.815 60.007 62.73 60.107 ;
     RECT  0.072 59.809 3.474 60.115 ;
     RECT  25.02 59.909 26.226 60.115 ;
     RECT  27.036 58.523 28.35 60.115 ;
     RECT  25.02 60.115 28.35 60.143 ;
     RECT  15.84 58.531 15.858 60.151 ;
     RECT  53.244 59.809 56.697 60.151 ;
     RECT  61.815 60.107 62.097 60.151 ;
     RECT  53.244 60.151 56.754 60.269 ;
     RECT  49.896 60.007 52.398 60.305 ;
     RECT  47.016 59.063 48.942 60.313 ;
     RECT  54.72 60.269 56.754 60.313 ;
     RECT  82.404 59.027 83.697 60.313 ;
     RECT  76.068 59.225 78.786 60.341 ;
     RECT  13.215 59.851 14.31 60.349 ;
     RECT  50.112 60.305 52.398 60.377 ;
     RECT  115.815 59.765 116.514 60.385 ;
     RECT  117.432 59.611 118.854 60.385 ;
     RECT  15.228 60.151 15.858 60.413 ;
     RECT  29.415 59.971 35.097 60.413 ;
     RECT  80.208 59.611 80.55 60.413 ;
     RECT  13.215 60.349 14.454 60.421 ;
     RECT  36.036 58.685 36.594 60.421 ;
     RECT  86.976 58.415 87.138 60.421 ;
     RECT  54.72 60.313 56.79 60.511 ;
     RECT  12.492 60.421 14.454 60.539 ;
     RECT  16.74 59.801 16.758 60.583 ;
     RECT  17.496 59.909 24.297 60.583 ;
     RECT  53.244 60.269 53.622 60.611 ;
     RECT  58.176 57.641 58.374 60.611 ;
     RECT  9.936 59.027 10.314 60.619 ;
     RECT  16.74 60.583 24.297 60.647 ;
     RECT  54.72 60.511 57.006 60.647 ;
     RECT  12.492 60.539 14.202 60.655 ;
     RECT  58.176 60.611 58.302 60.655 ;
     RECT  12.384 60.655 14.202 60.683 ;
     RECT  6.84 59.099 6.894 60.691 ;
     RECT  7.815 59.099 8.154 60.691 ;
     RECT  88.815 58.685 89.097 60.691 ;
     RECT  16.74 60.647 18.897 60.719 ;
     RECT  53.604 60.611 53.622 60.719 ;
     RECT  115.815 60.385 118.854 60.781 ;
     RECT  16.74 60.719 17.802 60.809 ;
     RECT  54.72 60.647 56.754 60.809 ;
     RECT  9.936 60.619 10.962 60.817 ;
     RECT  54.972 60.809 56.754 60.845 ;
     RECT  36.036 60.421 36.666 60.853 ;
     RECT  18.612 60.719 18.897 60.881 ;
     RECT  88.416 60.691 89.097 60.889 ;
     RECT  9.936 60.817 11.502 60.893 ;
     RECT  9.936 60.893 10.962 60.917 ;
     RECT  85.536 58.379 86.13 60.925 ;
     RECT  86.904 60.421 87.138 60.925 ;
     RECT  9.936 60.917 10.926 60.953 ;
     RECT  25.848 60.143 28.35 60.953 ;
     RECT  80.208 60.413 80.226 60.955 ;
     RECT  6.084 59.459 6.102 60.961 ;
     RECT  6.84 60.691 8.154 60.961 ;
     RECT  88.38 60.889 89.097 60.961 ;
     RECT  79.92 60.955 80.226 60.995 ;
     RECT  9.936 60.953 10.818 61.051 ;
     RECT  0.036 60.115 3.474 61.079 ;
     RECT  6.084 60.961 8.154 61.079 ;
     RECT  25.848 60.953 26.334 61.079 ;
     RECT  36.036 60.853 36.846 61.079 ;
     RECT  76.068 60.341 78.462 61.079 ;
     RECT  6.084 61.079 6.966 61.087 ;
     RECT  7.776 61.079 8.154 61.115 ;
     RECT  88.272 60.961 89.097 61.115 ;
     RECT  7.815 61.115 8.154 61.189 ;
     RECT  25.02 60.143 25.038 61.195 ;
     RECT  25.848 61.079 26.226 61.195 ;
     RECT  4.5 59.459 4.518 61.231 ;
     RECT  9.756 61.051 10.818 61.231 ;
     RECT  19.656 60.647 24.297 61.231 ;
     RECT  25.02 61.195 26.226 61.231 ;
     RECT  42.372 58.649 43.506 61.231 ;
     RECT  81.756 60.313 83.697 61.231 ;
     RECT  84.492 60.241 84.51 61.231 ;
     RECT  9.684 61.231 10.818 61.259 ;
     RECT  4.5 61.231 4.77 61.321 ;
     RECT  5.724 61.087 6.966 61.321 ;
     RECT  9.684 61.259 10.314 61.321 ;
     RECT  0.036 61.079 2.826 61.349 ;
     RECT  36.036 61.079 36.738 61.349 ;
     RECT  81.756 61.231 84.51 61.385 ;
     RECT  16.74 60.809 17.622 61.421 ;
     RECT  84.492 61.385 84.51 61.421 ;
     RECT  7.815 61.189 8.298 61.429 ;
     RECT  9.288 61.321 10.314 61.429 ;
     RECT  29.415 60.413 32.13 61.429 ;
     RECT  46.908 60.313 48.942 61.429 ;
     RECT  4.5 61.321 6.966 61.457 ;
     RECT  29.415 61.429 32.238 61.465 ;
     RECT  32.976 60.413 35.097 61.465 ;
     RECT  50.4 60.377 52.398 61.465 ;
     RECT  42.372 61.231 43.542 61.501 ;
     RECT  19.656 61.231 26.226 61.517 ;
     RECT  25.848 61.517 26.226 61.529 ;
     RECT  12.384 60.683 14.166 61.591 ;
     RECT  45.615 58.181 46.026 61.591 ;
     RECT  46.764 61.429 48.942 61.591 ;
     RECT  115.308 60.781 118.854 61.591 ;
     RECT  84.528 61.501 84.726 61.619 ;
     RECT  38.016 59.225 40.497 61.627 ;
     RECT  42.228 61.501 43.542 61.627 ;
     RECT  19.656 61.517 25.038 61.655 ;
     RECT  12.384 61.591 14.742 61.699 ;
     RECT  12.132 61.699 14.742 61.771 ;
     RECT  42.12 61.627 43.542 61.771 ;
     RECT  44.316 58.649 44.73 61.771 ;
     RECT  85.536 60.925 87.282 61.771 ;
     RECT  84.528 61.619 84.546 61.805 ;
     RECT  6.84 61.457 6.966 61.889 ;
     RECT  42.12 61.771 44.73 61.889 ;
     RECT  42.12 61.889 43.506 61.897 ;
     RECT  12.132 61.771 14.814 61.925 ;
     RECT  85.5 61.771 87.282 61.925 ;
     RECT  12.204 61.925 14.814 61.961 ;
     RECT  12.204 61.961 12.474 61.997 ;
     RECT  29.415 61.465 35.097 61.997 ;
     RECT  7.815 61.429 10.314 62.005 ;
     RECT  13.215 61.961 14.814 62.033 ;
     RECT  41.976 61.897 43.506 62.033 ;
     RECT  49.896 61.465 52.398 62.041 ;
     RECT  75.168 55.823 75.186 62.041 ;
     RECT  20.484 61.655 25.038 62.069 ;
     RECT  29.415 61.997 32.238 62.069 ;
     RECT  41.976 62.033 42.822 62.069 ;
     RECT  25.956 61.529 26.226 62.131 ;
     RECT  27.432 60.953 28.35 62.131 ;
     RECT  4.5 61.457 5.814 62.167 ;
     RECT  16.74 61.421 16.758 62.167 ;
     RECT  38.016 61.627 41.022 62.195 ;
     RECT  80.208 60.995 80.226 62.195 ;
     RECT  15.84 60.413 15.858 62.203 ;
     RECT  25.956 62.131 28.674 62.231 ;
     RECT  4.248 62.167 5.814 62.275 ;
     RECT  15.84 62.203 15.966 62.275 ;
     RECT  16.74 62.167 16.794 62.275 ;
     RECT  18.615 60.881 18.897 62.275 ;
     RECT  19.656 61.655 19.674 62.275 ;
     RECT  15.624 62.275 16.794 62.303 ;
     RECT  27.36 62.231 28.674 62.311 ;
     RECT  29.415 62.069 31.806 62.311 ;
     RECT  36.036 61.349 36.666 62.311 ;
     RECT  88.815 61.115 89.097 62.311 ;
     RECT  42.012 62.069 42.822 62.339 ;
     RECT  15.624 62.303 16.758 62.401 ;
     RECT  3.78 62.275 5.814 62.429 ;
     RECT  13.215 62.033 14.094 62.429 ;
     RECT  32.976 61.997 35.097 62.429 ;
     RECT  36.036 62.311 36.99 62.429 ;
     RECT  15.408 62.401 16.758 62.501 ;
     RECT  0.036 61.349 2.697 62.545 ;
     RECT  3.78 62.429 3.798 62.545 ;
     RECT  7.815 62.005 10.89 62.545 ;
     RECT  6.84 61.889 6.894 62.581 ;
     RECT  88.344 62.311 89.097 62.581 ;
     RECT  7.74 62.545 10.89 62.609 ;
     RECT  85.536 61.925 87.282 62.669 ;
     RECT  5.724 62.429 5.814 62.671 ;
     RECT  6.768 62.581 6.894 62.671 ;
     RECT  38.016 62.195 40.878 62.671 ;
     RECT  0.036 62.545 3.798 62.735 ;
     RECT  88.2 62.581 89.097 62.735 ;
     RECT  5.724 62.671 6.894 62.779 ;
     RECT  7.74 62.609 8.097 62.779 ;
     RECT  20.484 62.069 20.862 62.807 ;
     RECT  49.896 62.041 52.722 62.851 ;
     RECT  57.888 60.655 58.302 62.851 ;
     RECT  49.896 62.851 53.226 62.941 ;
     RECT  81.756 61.385 83.697 62.941 ;
     RECT  0.072 62.735 3.798 62.969 ;
     RECT  45.615 61.591 48.942 62.969 ;
     RECT  46.764 62.969 48.942 62.977 ;
     RECT  49.896 62.941 53.37 62.977 ;
     RECT  4.86 62.429 4.878 63.005 ;
     RECT  115.164 61.591 118.854 63.005 ;
     RECT  81.612 62.941 83.697 63.041 ;
     RECT  0.072 62.969 3.402 63.053 ;
     RECT  81.756 63.041 83.697 63.077 ;
     RECT  57.888 62.851 58.554 63.085 ;
     RECT  46.764 62.977 53.37 63.121 ;
     RECT  1.152 63.053 3.402 63.149 ;
     RECT  5.724 62.779 8.097 63.239 ;
     RECT  15.624 62.501 16.758 63.275 ;
     RECT  57.888 63.085 58.59 63.275 ;
     RECT  9.072 62.609 10.89 63.283 ;
     RECT  46.764 63.121 53.622 63.283 ;
     RECT  5.724 63.239 6.246 63.319 ;
     RECT  9.072 63.283 10.926 63.319 ;
     RECT  25.956 62.231 26.226 63.319 ;
     RECT  27.36 62.311 31.806 63.319 ;
     RECT  1.98 63.149 3.402 63.341 ;
     RECT  46.764 63.283 53.658 63.341 ;
     RECT  13.215 62.429 14.058 63.391 ;
     RECT  14.868 63.211 14.886 63.391 ;
     RECT  37.98 62.671 40.878 63.391 ;
     RECT  2.052 63.341 3.402 63.437 ;
     RECT  9.072 63.319 10.962 63.481 ;
     RECT  37.944 63.391 40.878 63.481 ;
     RECT  0.072 63.053 0.234 63.509 ;
     RECT  25.956 63.319 31.806 63.509 ;
     RECT  9.072 63.481 11.25 63.545 ;
     RECT  46.764 63.341 53.622 63.545 ;
     RECT  55.98 60.845 56.754 63.553 ;
     RECT  9.108 63.545 11.25 63.581 ;
     RECT  46.764 63.545 53.55 63.581 ;
     RECT  20.628 62.807 20.862 63.589 ;
     RECT  9.144 63.581 11.25 63.617 ;
     RECT  49.716 63.581 53.55 63.617 ;
     RECT  12.204 61.997 12.366 63.625 ;
     RECT  52.308 63.617 53.334 63.653 ;
     RECT  13.215 63.391 14.886 63.661 ;
     RECT  15.624 63.275 16.398 63.661 ;
     RECT  54.972 60.845 54.99 63.661 ;
     RECT  55.872 63.553 56.754 63.661 ;
     RECT  49.716 63.617 51.462 63.689 ;
     RECT  18.615 62.275 19.674 63.751 ;
     RECT  20.628 63.589 21.006 63.751 ;
     RECT  21.78 62.069 25.038 63.751 ;
     RECT  7.416 63.239 8.097 63.779 ;
     RECT  9.144 63.617 10.062 63.779 ;
     RECT  49.788 63.689 51.462 63.815 ;
     RECT  2.415 63.437 3.402 63.821 ;
     RECT  5.4 63.319 6.246 63.821 ;
     RECT  52.308 63.653 52.65 63.821 ;
     RECT  50.436 63.815 51.462 63.824 ;
     RECT  20.628 63.751 25.038 63.851 ;
     RECT  25.956 63.509 26.226 63.851 ;
     RECT  46.764 63.581 48.942 63.851 ;
     RECT  11.988 63.625 12.366 63.859 ;
     RECT  20.628 63.851 21.366 63.859 ;
     RECT  33.372 62.429 35.097 63.859 ;
     RECT  0.144 63.509 0.234 63.883 ;
     RECT  1.152 63.149 1.17 63.883 ;
     RECT  17.568 61.421 17.622 63.883 ;
     RECT  18.36 63.751 19.674 63.883 ;
     RECT  52.308 63.821 52.614 63.887 ;
     RECT  37.944 63.481 40.95 63.895 ;
     RECT  42.336 62.339 42.822 63.895 ;
     RECT  52.308 63.887 52.47 63.923 ;
     RECT  5.4 63.821 5.418 63.931 ;
     RECT  20.556 63.859 21.366 63.931 ;
     RECT  22.212 63.851 25.038 63.959 ;
     RECT  54.972 63.661 56.754 64.021 ;
     RECT  9.144 63.779 10.026 64.049 ;
     RECT  11.988 63.859 12.438 64.049 ;
     RECT  13.215 63.661 16.398 64.057 ;
     RECT  22.572 63.959 25.038 64.057 ;
     RECT  88.308 62.735 89.097 64.085 ;
     RECT  89.856 63.931 89.874 64.085 ;
     RECT  13.215 64.057 16.47 64.109 ;
     RECT  9.144 64.049 9.954 64.121 ;
     RECT  12.204 64.049 12.366 64.121 ;
     RECT  13.215 64.109 16.326 64.121 ;
     RECT  17.568 63.883 19.674 64.121 ;
     RECT  20.484 63.931 21.366 64.121 ;
     RECT  88.344 64.085 89.097 64.121 ;
     RECT  17.568 64.121 17.622 64.129 ;
     RECT  22.572 64.057 25.074 64.129 ;
     RECT  20.664 64.121 21.366 64.13 ;
     RECT  13.215 64.121 15.858 64.157 ;
     RECT  81.972 63.077 83.697 64.157 ;
     RECT  10.836 63.617 11.25 64.165 ;
     RECT  37.944 63.895 41.49 64.165 ;
     RECT  42.264 63.895 42.822 64.165 ;
     RECT  4.86 63.931 5.418 64.193 ;
     RECT  84.744 63.931 84.762 64.193 ;
     RECT  6.192 63.821 6.246 64.201 ;
     RECT  68.976 60.035 68.994 64.201 ;
     RECT  88.452 64.121 89.097 64.201 ;
     RECT  33.372 63.859 35.154 64.291 ;
     RECT  37.944 64.165 42.822 64.291 ;
     RECT  83.124 64.157 83.697 64.291 ;
     RECT  84.564 64.201 84.69 64.291 ;
     RECT  10.836 64.165 11.286 64.319 ;
     RECT  25.956 63.851 26.046 64.319 ;
     RECT  83.124 64.291 84.69 64.319 ;
     RECT  85.536 62.669 86.994 64.319 ;
     RECT  88.452 64.201 89.802 64.319 ;
     RECT  70.344 47.075 71.514 64.327 ;
     RECT  72.615 46.409 73.638 64.327 ;
     RECT  0.144 63.883 1.17 64.355 ;
     RECT  13.215 64.157 14.886 64.355 ;
     RECT  17.424 64.129 17.622 64.355 ;
     RECT  26.964 63.509 31.806 64.355 ;
     RECT  54.972 64.021 56.826 64.355 ;
     RECT  68.796 64.201 68.994 64.355 ;
     RECT  83.376 64.319 84.582 64.355 ;
     RECT  88.452 64.319 89.73 64.355 ;
     RECT  22.572 64.129 25.146 64.357 ;
     RECT  10.836 64.319 11.178 64.36 ;
     RECT  6.192 64.201 6.822 64.391 ;
     RECT  9.648 64.121 9.954 64.391 ;
     RECT  13.215 64.355 14.814 64.391 ;
     RECT  20.7 64.13 21.366 64.391 ;
     RECT  25.956 64.319 25.974 64.391 ;
     RECT  33.372 64.291 35.226 64.391 ;
     RECT  10.764 64.36 11.178 64.397 ;
     RECT  55.944 64.355 56.826 64.397 ;
     RECT  10.764 64.397 11.07 64.463 ;
     RECT  68.976 64.355 68.994 64.471 ;
     RECT  26.964 64.355 26.982 64.499 ;
     RECT  68.976 64.471 69.174 64.499 ;
     RECT  98.568 57.613 98.586 64.597 ;
     RECT  2.415 63.821 3.042 64.603 ;
     RECT  4.068 64.027 4.086 64.603 ;
     RECT  2.415 64.603 4.086 64.651 ;
     RECT  36.036 62.429 36.918 64.669 ;
     RECT  55.98 64.397 56.826 64.669 ;
     RECT  46.8 63.851 48.942 64.705 ;
     RECT  55.98 64.669 56.934 64.733 ;
     RECT  2.304 64.651 4.086 64.741 ;
     RECT  50.436 63.824 51.297 64.741 ;
     RECT  57.888 63.275 58.518 64.741 ;
     RECT  98.568 64.597 98.658 64.741 ;
     RECT  99.615 2.413 99.897 64.741 ;
     RECT  104.256 64.597 104.274 64.741 ;
     RECT  105.015 2.413 105.297 64.741 ;
     RECT  56.016 64.733 56.934 64.769 ;
     RECT  2.268 64.741 4.086 64.781 ;
     RECT  2.304 64.781 4.086 64.831 ;
     RECT  50.076 64.741 51.297 64.831 ;
     RECT  98.424 64.741 99.897 64.831 ;
     RECT  0.144 64.355 0.666 64.843 ;
     RECT  57.888 64.741 58.554 64.859 ;
     RECT  69.048 64.499 69.174 64.867 ;
     RECT  96.768 64.741 96.786 64.867 ;
     RECT  104.256 64.741 105.297 64.867 ;
     RECT  104.256 64.867 105.426 64.891 ;
     RECT  37.944 64.291 43.398 64.895 ;
     RECT  54.972 64.355 55.17 64.903 ;
     RECT  94.215 2.413 94.497 64.903 ;
     RECT  104.184 64.891 105.426 64.93 ;
     RECT  22.572 64.357 25.218 64.939 ;
     RECT  57.888 64.859 58.518 64.967 ;
     RECT  102.564 64.867 102.582 64.975 ;
     RECT  102.528 64.975 102.582 64.987 ;
     RECT  104.148 64.93 105.426 64.987 ;
     RECT  27.72 64.355 31.806 65.003 ;
     RECT  50.004 64.831 51.297 65.003 ;
     RECT  7.74 63.779 8.097 65.011 ;
     RECT  96.768 64.867 96.93 65.011 ;
     RECT  102.456 64.987 102.582 65.011 ;
     RECT  103.464 64.987 105.426 65.011 ;
     RECT  106.92 64.975 106.938 65.011 ;
     RECT  110.415 2.413 110.697 65.011 ;
     RECT  103.392 65.011 105.426 65.021 ;
     RECT  46.8 64.705 49.014 65.039 ;
     RECT  102.456 65.011 102.654 65.039 ;
     RECT  103.392 65.021 103.482 65.039 ;
     RECT  36.036 64.669 37.026 65.101 ;
     RECT  45.615 62.969 46.026 65.101 ;
     RECT  46.8 65.039 47.934 65.101 ;
     RECT  61.416 60.151 62.097 65.101 ;
     RECT  81.972 64.157 82.062 65.101 ;
     RECT  83.376 64.355 84.114 65.101 ;
     RECT  94.215 64.903 94.59 65.101 ;
     RECT  110.415 65.011 110.79 65.101 ;
     RECT  112.608 65.011 112.626 65.101 ;
     RECT  38.016 64.895 43.398 65.129 ;
     RECT  0.108 64.843 0.666 65.131 ;
     RECT  81.504 65.101 84.114 65.137 ;
     RECT  13.215 64.391 14.706 65.173 ;
     RECT  102.528 65.039 102.654 65.173 ;
     RECT  103.392 65.039 103.41 65.173 ;
     RECT  104.256 65.021 105.426 65.173 ;
     RECT  108.576 65.101 108.594 65.173 ;
     RECT  109.44 65.101 110.79 65.173 ;
     RECT  112.284 65.101 112.626 65.173 ;
     RECT  38.016 65.129 42.822 65.201 ;
     RECT  6.192 64.391 6.21 65.209 ;
     RECT  7.74 65.011 8.298 65.209 ;
     RECT  33.372 64.391 35.19 65.209 ;
     RECT  36.036 65.101 37.17 65.209 ;
     RECT  85.536 64.319 86.85 65.209 ;
     RECT  100.98 65.083 100.998 65.209 ;
     RECT  2.304 64.831 4.302 65.237 ;
     RECT  81.108 65.137 84.114 65.237 ;
     RECT  109.44 65.173 112.626 65.237 ;
     RECT  5.4 64.193 5.418 65.245 ;
     RECT  22.572 64.939 25.686 65.245 ;
     RECT  67.215 2.413 67.497 65.245 ;
     RECT  107.892 65.173 108.594 65.245 ;
     RECT  109.44 65.237 112.554 65.245 ;
     RECT  81.972 65.237 84.114 65.273 ;
     RECT  94.215 65.101 94.878 65.273 ;
     RECT  4.068 65.237 4.302 65.281 ;
     RECT  5.256 65.245 5.418 65.281 ;
     RECT  6.192 65.209 6.93 65.281 ;
     RECT  7.74 65.209 8.694 65.281 ;
     RECT  76.068 61.079 78.297 65.281 ;
     RECT  100.728 65.209 100.998 65.281 ;
     RECT  6.192 65.281 8.694 65.309 ;
     RECT  106.92 65.011 107.082 65.371 ;
     RECT  107.892 65.245 112.554 65.371 ;
     RECT  33.372 65.209 37.17 65.399 ;
     RECT  76.068 65.281 78.75 65.399 ;
     RECT  96.768 65.011 97.074 65.399 ;
     RECT  104.256 65.173 106.074 65.399 ;
     RECT  106.92 65.371 112.554 65.399 ;
     RECT  4.068 65.281 5.418 65.435 ;
     RECT  7.308 65.309 8.622 65.435 ;
     RECT  83.415 65.273 84.114 65.435 ;
     RECT  85.356 65.209 86.958 65.435 ;
     RECT  107.064 65.399 112.554 65.435 ;
     RECT  96.768 65.399 96.858 65.443 ;
     RECT  26.784 64.597 26.802 65.471 ;
     RECT  76.068 65.399 78.678 65.471 ;
     RECT  85.464 65.435 86.958 65.471 ;
     RECT  107.064 65.435 110.754 65.471 ;
     RECT  111.492 65.435 112.554 65.471 ;
     RECT  98.316 64.831 99.897 65.507 ;
     RECT  67.068 65.245 67.497 65.515 ;
     RECT  74.988 62.041 75.186 65.515 ;
     RECT  119.952 61.771 119.97 65.515 ;
     RECT  85.5 65.471 86.958 65.543 ;
     RECT  96.372 65.443 96.858 65.543 ;
     RECT  98.316 65.507 98.658 65.543 ;
     RECT  104.256 65.399 105.426 65.543 ;
     RECT  108.864 65.471 110.754 65.543 ;
     RECT  50.184 65.003 51.297 65.551 ;
     RECT  52.416 63.923 52.47 65.551 ;
     RECT  100.728 65.281 101.25 65.551 ;
     RECT  102.528 65.173 103.41 65.579 ;
     RECT  107.064 65.471 108.018 65.579 ;
     RECT  15.732 64.157 15.858 65.659 ;
     RECT  10.764 64.463 10.998 65.669 ;
     RECT  45.615 65.101 47.934 65.669 ;
     RECT  85.536 65.543 86.958 65.669 ;
     RECT  100.692 65.551 101.25 65.669 ;
     RECT  107.064 65.579 107.226 65.669 ;
     RECT  54.9 64.903 55.17 65.705 ;
     RECT  100.692 65.669 100.71 65.705 ;
     RECT  0.108 65.131 0.882 65.707 ;
     RECT  2.304 65.237 3.078 65.707 ;
     RECT  6.192 65.309 6.246 65.741 ;
     RECT  56.016 64.769 56.826 65.741 ;
     RECT  107.064 65.669 107.19 65.741 ;
     RECT  108.9 65.543 110.697 65.741 ;
     RECT  111.6 65.471 112.554 65.741 ;
     RECT  99.615 65.507 99.897 65.749 ;
     RECT  10.764 65.669 10.89 65.785 ;
     RECT  7.308 65.435 8.334 65.813 ;
     RECT  98.388 65.543 98.658 65.813 ;
     RECT  33.372 65.399 36.846 65.849 ;
     RECT  4.284 65.435 5.418 65.939 ;
     RECT  7.308 65.813 8.097 65.939 ;
     RECT  22.248 65.245 25.686 65.939 ;
     RECT  56.016 65.741 56.79 65.939 ;
     RECT  15.624 65.659 15.858 65.975 ;
     RECT  56.088 65.939 56.79 65.975 ;
     RECT  0.108 65.707 3.078 66.091 ;
     RECT  54.972 65.705 55.17 66.091 ;
     RECT  94.215 65.273 94.806 66.139 ;
     RECT  40.215 65.201 42.822 66.181 ;
     RECT  93.744 66.139 94.806 66.181 ;
     RECT  13.104 65.173 14.706 66.209 ;
     RECT  12.204 64.121 12.222 66.217 ;
     RECT  16.668 66.181 16.686 66.217 ;
     RECT  88.452 64.355 89.097 66.217 ;
     RECT  14.508 66.209 14.706 66.245 ;
     RECT  66.816 65.515 67.497 66.245 ;
     RECT  108 65.579 108.018 66.245 ;
     RECT  113.436 65.281 113.454 66.245 ;
     RECT  14.58 66.245 14.706 66.253 ;
     RECT  69.048 64.867 69.426 66.253 ;
     RECT  22.248 65.939 25.074 66.281 ;
     RECT  85.536 65.669 86.85 66.281 ;
     RECT  38.016 65.201 39.222 66.289 ;
     RECT  40.176 66.181 42.822 66.289 ;
     RECT  14.58 66.253 14.742 66.317 ;
     RECT  0.108 66.091 3.186 66.325 ;
     RECT  16.668 66.217 16.758 66.325 ;
     RECT  81.972 65.273 81.99 66.325 ;
     RECT  14.724 66.317 14.742 66.361 ;
     RECT  33.372 65.849 35.097 66.361 ;
     RECT  112.284 65.741 112.554 66.361 ;
     RECT  114.3 66.253 114.318 66.361 ;
     RECT  88.452 66.217 89.37 66.427 ;
     RECT  79.164 66.361 79.182 66.451 ;
     RECT  114.3 66.361 114.606 66.451 ;
     RECT  14.724 66.361 14.886 66.479 ;
     RECT  16.668 66.325 16.83 66.479 ;
     RECT  88.344 66.427 89.37 66.479 ;
     RECT  112.284 66.361 112.914 66.479 ;
     RECT  76.068 65.471 78.297 66.515 ;
     RECT  112.284 66.479 112.554 66.515 ;
     RECT  93.348 66.181 94.806 66.523 ;
     RECT  16.812 66.479 16.83 66.551 ;
     RECT  22.248 66.281 24.822 66.551 ;
     RECT  96.48 65.543 96.858 66.551 ;
     RECT  93.348 66.523 95.13 66.559 ;
     RECT  9.648 64.391 9.666 66.619 ;
     RECT  10.404 65.785 10.89 66.619 ;
     RECT  38.016 66.289 42.822 66.623 ;
     RECT  77.22 66.515 78.297 66.623 ;
     RECT  0.108 66.325 3.33 66.631 ;
     RECT  79.164 66.451 79.254 66.631 ;
     RECT  88.815 66.479 89.37 66.631 ;
     RECT  114.012 66.451 114.606 66.631 ;
     RECT  22.248 66.551 24.678 66.659 ;
     RECT  85.536 66.281 86.778 66.659 ;
     RECT  81.468 66.325 81.99 66.715 ;
     RECT  4.284 65.939 5.274 66.721 ;
     RECT  7.74 65.939 8.097 66.721 ;
     RECT  54.972 66.091 55.314 66.721 ;
     RECT  81.468 66.715 82.026 66.721 ;
     RECT  93.276 66.559 95.13 66.721 ;
     RECT  36.036 65.849 36.846 66.749 ;
     RECT  83.415 65.435 83.826 66.749 ;
     RECT  88.815 66.631 89.514 66.749 ;
     RECT  114.012 66.631 114.642 66.749 ;
     RECT  6.228 65.741 6.246 66.757 ;
     RECT  12.024 66.217 12.294 66.757 ;
     RECT  13.104 66.209 13.497 66.757 ;
     RECT  83.415 66.749 83.697 66.757 ;
     RECT  33.3 66.361 35.097 66.785 ;
     RECT  77.652 66.623 78.297 66.785 ;
     RECT  88.815 66.749 89.298 66.785 ;
     RECT  45.615 65.669 47.862 66.793 ;
     RECT  92.952 66.721 95.13 66.793 ;
     RECT  18.615 64.121 19.674 66.821 ;
     RECT  40.032 66.623 42.822 66.821 ;
     RECT  81.468 66.721 82.062 66.821 ;
     RECT  114.12 66.749 114.642 66.821 ;
     RECT  0.072 66.631 3.33 66.829 ;
     RECT  4.284 66.721 5.346 66.829 ;
     RECT  27.864 65.003 31.806 66.829 ;
     RECT  45.615 66.793 48.006 66.829 ;
     RECT  48.744 65.039 49.014 66.829 ;
     RECT  54.648 66.721 55.314 66.829 ;
     RECT  17.604 64.355 17.622 66.856 ;
     RECT  9.648 66.619 10.89 66.857 ;
     RECT  6.192 66.757 6.246 66.865 ;
     RECT  7.128 66.721 8.097 66.865 ;
     RECT  9.648 66.857 10.782 66.865 ;
     RECT  18.615 66.821 19.386 66.893 ;
     RECT  27.864 66.829 31.842 66.893 ;
     RECT  53.604 65.947 53.622 66.893 ;
     RECT  17.604 66.856 17.658 66.901 ;
     RECT  20.844 64.391 21.366 66.901 ;
     RECT  22.248 66.659 24.57 66.901 ;
     RECT  54.648 66.829 55.386 66.901 ;
     RECT  77.796 66.785 78.297 66.901 ;
     RECT  79.02 66.631 79.254 66.901 ;
     RECT  81.9 66.821 82.062 66.901 ;
     RECT  115.596 63.005 118.854 66.901 ;
     RECT  81.9 66.901 82.206 66.929 ;
     RECT  109.44 65.741 110.697 66.929 ;
     RECT  17.568 66.901 17.874 66.941 ;
     RECT  17.568 66.941 17.802 67.019 ;
     RECT  50.184 65.551 52.47 67.019 ;
     RECT  82.008 66.929 82.206 67.019 ;
     RECT  0.072 66.829 5.346 67.051 ;
     RECT  6.192 66.865 8.097 67.051 ;
     RECT  41.22 66.821 42.822 67.055 ;
     RECT  82.008 67.019 82.026 67.055 ;
     RECT  114.12 66.821 114.138 67.055 ;
     RECT  14.724 66.479 14.85 67.063 ;
     RECT  17.568 67.019 17.658 67.063 ;
     RECT  20.844 66.901 24.57 67.063 ;
     RECT  0.072 67.051 8.097 67.091 ;
     RECT  14.472 67.063 14.85 67.091 ;
     RECT  28.008 66.893 31.842 67.091 ;
     RECT  38.016 66.623 39.222 67.091 ;
     RECT  83.124 66.757 83.697 67.099 ;
     RECT  17.352 67.063 17.658 67.133 ;
     RECT  115.488 66.901 118.854 67.135 ;
     RECT  17.352 67.133 17.622 67.136 ;
     RECT  17.424 67.136 17.622 67.163 ;
     RECT  45.615 66.829 49.014 67.163 ;
     RECT  54.468 66.901 55.386 67.171 ;
     RECT  83.052 67.099 83.697 67.171 ;
     RECT  92.592 66.793 95.13 67.171 ;
     RECT  12.024 66.757 13.497 67.199 ;
     RECT  56.124 65.975 56.79 67.199 ;
     RECT  85.536 66.659 86.67 67.199 ;
     RECT  54.324 67.171 55.386 67.229 ;
     RECT  98.388 65.813 98.622 67.243 ;
     RECT  99.615 65.749 99.954 67.243 ;
     RECT  17.604 67.163 17.622 67.289 ;
     RECT  98.388 67.243 99.954 67.289 ;
     RECT  102.456 65.785 102.474 67.297 ;
     RECT  77.796 66.901 79.254 67.325 ;
     RECT  82.98 67.171 83.697 67.325 ;
     RECT  98.388 67.289 98.694 67.369 ;
     RECT  96.48 66.551 96.498 67.405 ;
     RECT  102.456 67.297 102.546 67.405 ;
     RECT  103.392 65.579 103.41 67.405 ;
     RECT  99.615 67.289 99.954 67.435 ;
     RECT  28.044 67.091 31.842 67.441 ;
     RECT  102.456 67.405 103.41 67.441 ;
     RECT  14.472 67.091 14.814 67.469 ;
     RECT  99.615 67.435 100.026 67.475 ;
     RECT  90.684 67.291 90.702 67.483 ;
     RECT  90.324 67.483 90.702 67.517 ;
     RECT  44.316 61.889 44.73 67.531 ;
     RECT  45.615 67.163 46.026 67.531 ;
     RECT  102.456 67.441 103.482 67.531 ;
     RECT  104.256 65.543 104.274 67.531 ;
     RECT  105.015 65.543 105.426 67.531 ;
     RECT  9.54 66.865 10.782 67.559 ;
     RECT  28.044 67.441 31.878 67.559 ;
     RECT  101.988 67.531 104.274 67.559 ;
     RECT  12.636 67.199 13.497 67.595 ;
     RECT  28.044 67.559 31.518 67.595 ;
     RECT  44.316 67.531 46.026 67.595 ;
     RECT  105.015 67.531 106.11 67.603 ;
     RECT  107.172 65.741 107.19 67.603 ;
     RECT  25.668 66.829 25.686 67.669 ;
     RECT  12.888 67.595 13.497 67.675 ;
     RECT  18.615 66.893 19.062 67.675 ;
     RECT  25.668 67.669 26.01 67.675 ;
     RECT  26.784 66.559 26.802 67.675 ;
     RECT  40.032 66.821 40.497 67.675 ;
     RECT  29.415 67.595 31.518 67.703 ;
     RECT  44.712 67.595 46.026 67.703 ;
     RECT  85.536 67.199 85.842 67.703 ;
     RECT  101.988 67.559 102.618 67.703 ;
     RECT  103.464 67.559 104.274 67.703 ;
     RECT  9.684 67.559 10.782 67.711 ;
     RECT  11.628 67.603 11.718 67.711 ;
     RECT  96.48 67.405 96.57 67.711 ;
     RECT  90.324 67.517 90.63 67.723 ;
     RECT  96.336 67.711 96.57 67.739 ;
     RECT  102.096 67.703 102.618 67.739 ;
     RECT  103.644 67.703 103.914 67.739 ;
     RECT  88.815 66.785 89.097 67.771 ;
     RECT  108.324 67.639 108.342 67.801 ;
     RECT  9.684 67.711 11.718 67.829 ;
     RECT  12.888 67.675 13.554 67.829 ;
     RECT  25.668 67.675 26.802 67.829 ;
     RECT  90.252 67.723 90.63 67.829 ;
     RECT  38.016 67.091 39.078 67.837 ;
     RECT  39.816 67.675 40.497 67.837 ;
     RECT  97.776 67.369 98.694 67.837 ;
     RECT  9.684 67.829 11.43 67.865 ;
     RECT  102.096 67.739 102.222 67.865 ;
     RECT  26.784 67.829 26.802 67.873 ;
     RECT  36.108 66.749 36.846 67.909 ;
     RECT  6.192 67.091 8.097 67.945 ;
     RECT  0.072 67.091 5.346 67.981 ;
     RECT  41.616 67.055 42.822 67.981 ;
     RECT  112.284 66.515 112.302 67.981 ;
     RECT  38.016 67.837 40.497 68.009 ;
     RECT  26.784 67.873 26.874 68.011 ;
     RECT  0.072 67.981 5.418 68.099 ;
     RECT  20.628 67.063 24.57 68.099 ;
     RECT  41.616 67.981 43.326 68.099 ;
     RECT  20.628 68.099 23.022 68.107 ;
     RECT  6.156 67.945 8.097 68.135 ;
     RECT  115.308 67.135 118.854 68.135 ;
     RECT  115.596 68.135 118.854 68.143 ;
     RECT  105.015 67.603 107.19 68.144 ;
     RECT  19.908 68.107 23.022 68.171 ;
     RECT  26.784 68.011 27.018 68.171 ;
     RECT  92.52 67.171 95.13 68.179 ;
     RECT  6.192 68.135 8.097 68.207 ;
     RECT  28.044 67.595 28.674 68.215 ;
     RECT  112.104 67.981 112.302 68.215 ;
     RECT  20.916 68.171 22.086 68.243 ;
     RECT  41.616 68.099 43.182 68.243 ;
     RECT  57.888 64.967 58.482 68.251 ;
     RECT  112.104 68.215 112.734 68.251 ;
     RECT  6.336 68.207 8.097 68.279 ;
     RECT  96.336 67.739 96.354 68.279 ;
     RECT  40.215 68.009 40.497 68.341 ;
     RECT  92.52 68.179 95.202 68.341 ;
     RECT  86.616 67.199 86.67 68.347 ;
     RECT  8.856 68.251 8.874 68.369 ;
     RECT  22.824 68.171 23.022 68.369 ;
     RECT  26.784 68.171 26.802 68.369 ;
     RECT  113.508 68.251 113.526 68.369 ;
     RECT  97.38 67.837 98.694 68.377 ;
     RECT  99.615 67.475 99.897 68.377 ;
     RECT  0.072 68.099 5.346 68.381 ;
     RECT  86.616 68.347 87.138 68.405 ;
     RECT  85.572 67.703 85.842 68.413 ;
     RECT  54.756 67.229 55.386 68.449 ;
     RECT  56.124 67.199 56.697 68.449 ;
     RECT  57.888 68.251 58.698 68.485 ;
     RECT  106.596 68.144 107.19 68.485 ;
     RECT  107.928 67.801 108.342 68.485 ;
     RECT  106.596 68.485 108.342 68.513 ;
     RECT  46.8 67.163 49.014 68.521 ;
     RECT  50.256 67.019 52.47 68.521 ;
     RECT  88.815 67.771 89.298 68.521 ;
     RECT  103.644 67.739 103.662 68.521 ;
     RECT  109.836 66.929 110.697 68.521 ;
     RECT  5.256 68.381 5.346 68.549 ;
     RECT  45.216 67.703 46.026 68.611 ;
     RECT  46.8 68.521 52.47 68.611 ;
     RECT  85.572 68.413 85.878 68.611 ;
     RECT  86.616 68.405 86.85 68.611 ;
     RECT  85.572 68.611 86.85 68.639 ;
     RECT  85.572 68.639 86.778 68.675 ;
     RECT  88.092 68.521 89.298 68.675 ;
     RECT  53.244 68.521 53.262 68.711 ;
     RECT  109.836 68.521 111.33 68.711 ;
     RECT  0.072 68.381 4.518 68.717 ;
     RECT  46.8 68.611 52.506 68.719 ;
     RECT  6.66 68.279 8.097 68.791 ;
     RECT  54.756 68.449 56.697 68.791 ;
     RECT  102.132 67.865 102.222 68.791 ;
     RECT  103.248 68.521 103.662 68.791 ;
     RECT  107.604 68.513 108.342 68.791 ;
     RECT  46.8 68.719 53.01 68.819 ;
     RECT  86.544 68.675 86.778 68.819 ;
     RECT  88.236 68.675 89.298 68.819 ;
     RECT  106.596 68.513 106.614 68.819 ;
     RECT  23.76 68.099 24.57 68.881 ;
     RECT  102.132 68.791 102.33 68.881 ;
     RECT  103.176 68.791 103.662 68.881 ;
     RECT  110.304 68.711 111.33 68.881 ;
     RECT  112.068 68.251 112.734 68.881 ;
     RECT  6.66 68.791 8.334 68.909 ;
     RECT  25.668 67.829 25.686 68.909 ;
     RECT  52.884 68.819 53.01 68.909 ;
     RECT  53.856 68.791 53.874 68.909 ;
     RECT  102.132 68.881 103.662 68.909 ;
     RECT  107.604 68.791 108.378 68.909 ;
     RECT  110.304 68.881 112.734 68.909 ;
     RECT  107.604 68.909 108.234 68.915 ;
     RECT  27.936 68.215 28.674 68.917 ;
     RECT  29.415 67.703 29.97 68.917 ;
     RECT  30.708 67.703 31.518 68.917 ;
     RECT  46.8 68.819 51.786 68.945 ;
     RECT  110.304 68.909 110.862 68.945 ;
     RECT  23.76 68.881 24.75 68.957 ;
     RECT  52.884 68.909 52.902 68.957 ;
     RECT  30.708 68.917 31.59 68.971 ;
     RECT  45.072 68.611 46.026 68.981 ;
     RECT  57.888 68.485 58.734 68.981 ;
     RECT  111.744 68.909 112.734 68.989 ;
     RECT  41.616 68.243 43.074 69.017 ;
     RECT  49.68 68.945 49.698 69.017 ;
     RECT  111.744 68.989 113.022 69.017 ;
     RECT  38.016 68.009 39.33 69.025 ;
     RECT  40.215 68.341 40.878 69.025 ;
     RECT  54.756 68.791 56.754 69.025 ;
     RECT  57.888 68.981 58.554 69.025 ;
     RECT  97.38 68.377 99.897 69.053 ;
     RECT  102.132 68.909 103.302 69.053 ;
     RECT  9.684 67.865 10.782 69.061 ;
     RECT  54.756 69.025 58.554 69.061 ;
     RECT  114.408 68.341 114.426 69.061 ;
     RECT  27.936 68.917 29.97 69.115 ;
     RECT  112.896 69.017 113.022 69.163 ;
     RECT  114.408 69.061 114.606 69.179 ;
     RECT  27.864 69.115 29.97 69.187 ;
     RECT  27.756 69.187 29.97 69.211 ;
     RECT  30.708 68.971 31.878 69.211 ;
     RECT  26.424 69.151 26.442 69.223 ;
     RECT  27.756 69.211 31.878 69.245 ;
     RECT  22.824 68.369 22.95 69.251 ;
     RECT  26.28 69.223 26.442 69.251 ;
     RECT  18.615 67.675 19.098 69.259 ;
     RECT  27.864 69.245 31.878 69.287 ;
     RECT  36.036 67.909 36.846 69.295 ;
     RECT  27.864 69.287 31.734 69.323 ;
     RECT  9.684 69.061 11.106 69.331 ;
     RECT  45.216 68.981 46.026 69.331 ;
     RECT  46.8 68.945 48.942 69.331 ;
     RECT  66.96 66.245 67.497 69.331 ;
     RECT  69.048 66.253 69.498 69.331 ;
     RECT  70.344 64.327 73.638 69.331 ;
     RECT  77.796 67.325 78.57 69.331 ;
     RECT  79.452 67.441 79.47 69.331 ;
     RECT  112.896 69.163 113.238 69.331 ;
     RECT  115.596 68.143 118.89 69.331 ;
     RECT  54.72 69.061 58.554 69.359 ;
     RECT  61.344 65.101 62.097 69.421 ;
     RECT  109.26 68.791 109.494 69.448 ;
     RECT  6.66 68.909 8.226 69.449 ;
     RECT  9.684 69.331 11.358 69.449 ;
     RECT  19.908 68.171 20.034 69.449 ;
     RECT  26.28 69.251 26.37 69.449 ;
     RECT  54.72 69.359 57.042 69.449 ;
     RECT  97.956 69.053 99.897 69.449 ;
     RECT  41.616 69.017 41.814 69.485 ;
     RECT  109.152 69.448 109.494 69.485 ;
     RECT  114.156 69.331 114.174 69.485 ;
     RECT  86.544 68.819 86.67 69.493 ;
     RECT  27.864 69.323 31.626 69.521 ;
     RECT  36.036 69.295 37.134 69.521 ;
     RECT  69.048 69.331 73.638 69.521 ;
     RECT  85.572 68.675 85.734 69.521 ;
     RECT  14.472 67.469 14.49 69.529 ;
     RECT  21.096 68.243 22.086 69.529 ;
     RECT  12.888 67.829 13.497 69.565 ;
     RECT  14.472 69.529 14.922 69.565 ;
     RECT  15.732 65.975 15.858 69.565 ;
     RECT  18.252 69.259 19.098 69.593 ;
     RECT  38.016 69.025 40.878 69.593 ;
     RECT  54.72 69.449 55.566 69.593 ;
     RECT  85.572 69.521 85.698 69.593 ;
     RECT  9.972 69.449 11.358 69.595 ;
     RECT  12.492 69.565 13.497 69.595 ;
     RECT  0.072 68.717 3.762 69.601 ;
     RECT  4.5 68.717 4.518 69.601 ;
     RECT  20.808 69.529 22.086 69.601 ;
     RECT  77.796 69.331 79.47 69.629 ;
     RECT  14.22 69.565 15.858 69.691 ;
     RECT  28.044 69.521 31.626 69.719 ;
     RECT  36.036 69.521 36.846 69.719 ;
     RECT  69.048 69.521 69.606 69.719 ;
     RECT  109.44 69.485 109.458 69.719 ;
     RECT  17.244 69.691 17.262 69.727 ;
     RECT  18.504 69.593 19.098 69.739 ;
     RECT  9 69.493 9.018 69.755 ;
     RECT  19.908 69.449 19.926 69.755 ;
     RECT  33.372 66.785 35.097 69.755 ;
     RECT  111.744 69.017 112.014 69.755 ;
     RECT  69.048 69.719 69.498 69.763 ;
     RECT  112.896 69.331 113.382 69.763 ;
     RECT  114.12 69.601 114.138 69.763 ;
     RECT  66.708 69.331 67.497 69.787 ;
     RECT  6.66 69.449 8.097 69.791 ;
     RECT  9.972 69.595 13.497 69.799 ;
     RECT  14.22 69.691 15.966 69.799 ;
     RECT  9.972 69.799 15.966 69.827 ;
     RECT  69.012 69.763 69.498 69.835 ;
     RECT  39.96 69.593 40.878 69.863 ;
     RECT  33.588 69.755 35.097 69.871 ;
     RECT  36.036 69.719 36.486 69.871 ;
     RECT  111.78 69.755 112.014 69.871 ;
     RECT  112.896 69.763 114.138 69.871 ;
     RECT  9.972 69.827 13.662 69.899 ;
     RECT  14.436 69.827 15.786 69.899 ;
     RECT  98.028 69.449 99.897 69.899 ;
     RECT  18.504 69.739 19.134 69.917 ;
     RECT  18.615 69.917 19.134 69.961 ;
     RECT  14.436 69.899 15.534 69.989 ;
     RECT  57.888 69.359 58.554 69.989 ;
     RECT  68.94 69.835 69.498 69.989 ;
     RECT  88.815 68.819 89.298 69.989 ;
     RECT  64.152 69.601 64.17 69.997 ;
     RECT  11.736 69.899 13.662 70.013 ;
     RECT  18.615 69.961 19.782 70.013 ;
     RECT  11.736 70.013 11.862 70.025 ;
     RECT  14.508 69.989 15.534 70.025 ;
     RECT  17.244 69.727 17.658 70.025 ;
     RECT  74.916 65.515 75.186 70.025 ;
     RECT  111.78 69.871 114.138 70.025 ;
     RECT  115.416 69.331 118.89 70.033 ;
     RECT  11.736 70.025 11.754 70.061 ;
     RECT  14.976 70.025 15.534 70.061 ;
     RECT  17.388 70.025 17.658 70.061 ;
     RECT  57.888 69.989 58.446 70.061 ;
     RECT  98.028 69.899 98.874 70.061 ;
     RECT  64.152 69.997 64.242 70.069 ;
     RECT  9.972 69.899 10.782 70.097 ;
     RECT  12.852 70.013 13.662 70.097 ;
     RECT  14.976 70.061 15.498 70.097 ;
     RECT  18.615 70.013 19.71 70.097 ;
     RECT  20.736 69.601 22.086 70.097 ;
     RECT  70.344 69.521 73.638 70.097 ;
     RECT  45.216 69.331 48.942 70.105 ;
     RECT  45.216 70.105 49.014 70.133 ;
     RECT  21.024 70.097 22.086 70.141 ;
     RECT  22.932 69.251 22.95 70.141 ;
     RECT  86.472 69.493 86.67 70.171 ;
     RECT  26.712 70.141 26.73 70.231 ;
     RECT  28.044 69.719 31.482 70.259 ;
     RECT  86.436 70.171 86.67 70.259 ;
     RECT  98.028 70.061 98.73 70.259 ;
     RECT  111.78 70.025 113.454 70.259 ;
     RECT  21.024 70.141 22.95 70.295 ;
     RECT  86.436 70.259 86.454 70.295 ;
     RECT  98.028 70.259 98.478 70.295 ;
     RECT  23.76 68.957 24.462 70.303 ;
     RECT  50.436 68.945 51.786 70.303 ;
     RECT  92.52 68.341 95.238 70.303 ;
     RECT  18.615 70.097 19.638 70.367 ;
     RECT  26.712 70.231 26.766 70.367 ;
     RECT  32.508 69.691 32.526 70.367 ;
     RECT  48.672 70.133 49.014 70.367 ;
     RECT  21.132 70.295 22.95 70.375 ;
     RECT  92.52 70.303 95.346 70.375 ;
     RECT  78.015 69.629 79.47 70.397 ;
     RECT  48.924 70.367 49.014 70.403 ;
     RECT  87.444 69.763 87.462 70.411 ;
     RECT  115.164 70.033 118.89 70.411 ;
     RECT  119.916 65.515 119.97 70.411 ;
     RECT  26.748 70.367 26.766 70.439 ;
     RECT  33.588 69.871 36.486 70.445 ;
     RECT  0.072 69.601 4.518 70.501 ;
     RECT  18.615 70.367 18.954 70.529 ;
     RECT  60.48 69.223 60.498 70.529 ;
     RECT  78.015 70.397 78.75 70.541 ;
     RECT  21.132 70.375 23.022 70.555 ;
     RECT  23.76 70.303 25.038 70.555 ;
     RECT  0.072 70.501 5.166 70.565 ;
     RECT  28.188 70.259 31.482 70.565 ;
     RECT  61.236 69.421 62.097 70.573 ;
     RECT  21.132 70.555 25.038 70.589 ;
     RECT  21.132 70.589 22.086 70.601 ;
     RECT  22.824 70.589 25.038 70.601 ;
     RECT  75.168 70.025 75.186 70.637 ;
     RECT  119.844 70.411 119.97 70.637 ;
     RECT  60.264 70.537 60.426 70.645 ;
     RECT  21.672 70.601 22.086 70.673 ;
     RECT  33.588 70.445 35.097 70.681 ;
     RECT  42.732 69.017 43.074 70.681 ;
     RECT  61.236 70.573 62.514 70.681 ;
     RECT  92.52 70.375 95.706 70.681 ;
     RECT  119.844 70.637 119.934 70.681 ;
     RECT  21.672 70.673 21.69 70.685 ;
     RECT  45.216 70.133 47.898 70.709 ;
     RECT  102.132 69.053 102.15 70.709 ;
     RECT  63.684 70.069 64.242 70.771 ;
     RECT  22.824 70.601 23.022 70.799 ;
     RECT  87.336 70.411 87.462 70.799 ;
     RECT  119.772 70.681 119.934 70.799 ;
     RECT  54.72 69.593 55.17 70.807 ;
     RECT  0.828 70.565 5.166 70.835 ;
     RECT  54.216 70.807 55.17 70.879 ;
     RECT  92.376 70.681 95.706 70.879 ;
     RECT  107.604 68.915 107.622 70.879 ;
     RECT  56.415 69.449 57.042 70.907 ;
     RECT  65.304 70.681 65.322 70.915 ;
     RECT  92.34 70.879 95.706 70.915 ;
     RECT  106.2 68.953 106.218 70.915 ;
     RECT  50.4 70.303 51.786 70.943 ;
     RECT  66.708 69.787 68.13 70.943 ;
     RECT  114.588 70.411 118.89 70.943 ;
     RECT  45.216 70.709 47.79 70.951 ;
     RECT  63.684 70.771 64.422 70.951 ;
     RECT  65.304 70.915 65.574 70.951 ;
     RECT  107.28 70.879 107.622 70.951 ;
     RECT  114.696 70.943 118.89 70.951 ;
     RECT  119.772 70.799 119.898 70.951 ;
     RECT  61.236 70.681 62.91 70.979 ;
     RECT  92.196 70.915 95.706 71.035 ;
     RECT  102.96 69.053 103.302 71.041 ;
     RECT  13.215 70.097 13.662 71.069 ;
     RECT  62.892 70.979 62.91 71.069 ;
     RECT  92.052 71.035 95.706 71.069 ;
     RECT  106.092 70.915 106.218 71.069 ;
     RECT  107.28 70.951 107.694 71.069 ;
     RECT  108.612 70.879 108.63 71.069 ;
     RECT  42.66 70.681 43.074 71.077 ;
     RECT  44.532 70.951 47.79 71.077 ;
     RECT  50.508 70.943 51.786 71.077 ;
     RECT  50.508 71.077 51.894 71.105 ;
     RECT  92.052 71.069 92.538 71.105 ;
     RECT  102.96 71.041 103.734 71.105 ;
     RECT  93.492 71.069 95.202 71.117 ;
     RECT  114.696 70.951 119.898 71.117 ;
     RECT  72 70.097 73.638 71.141 ;
     RECT  42.66 71.077 43.326 71.149 ;
     RECT  106.2 71.069 106.218 71.149 ;
     RECT  41.616 69.485 41.634 71.177 ;
     RECT  106.2 71.149 106.29 71.177 ;
     RECT  60.12 70.645 60.426 71.213 ;
     RECT  70.344 70.097 71.082 71.213 ;
     RECT  92.34 71.105 92.538 71.213 ;
     RECT  44.496 71.077 47.79 71.221 ;
     RECT  53.964 70.879 55.17 71.221 ;
     RECT  108.576 71.149 108.594 71.221 ;
     RECT  9.972 70.097 10.422 71.249 ;
     RECT  30.42 70.565 31.482 71.311 ;
     RECT  23.76 70.601 25.038 71.339 ;
     RECT  30.42 71.311 31.914 71.339 ;
     RECT  103.068 71.105 103.734 71.339 ;
     RECT  6.732 69.791 8.097 71.347 ;
     RECT  40.215 69.863 40.878 71.347 ;
     RECT  42.66 71.149 43.686 71.347 ;
     RECT  44.46 71.221 47.79 71.347 ;
     RECT  108.468 71.221 108.594 71.375 ;
     RECT  23.76 71.339 24.462 71.411 ;
     RECT  28.188 70.565 29.697 71.455 ;
     RECT  23.76 71.411 24.297 71.483 ;
     RECT  30.42 71.339 31.086 71.483 ;
     RECT  26.028 71.383 26.046 71.491 ;
     RECT  42.66 71.347 47.79 71.491 ;
     RECT  48.924 70.403 48.942 71.491 ;
     RECT  50.544 71.105 51.894 71.491 ;
     RECT  53.964 71.221 55.278 71.491 ;
     RECT  6.732 71.347 8.478 71.519 ;
     RECT  31.896 71.339 31.914 71.519 ;
     RECT  13.215 71.069 13.497 71.581 ;
     RECT  53.928 71.491 55.278 71.581 ;
     RECT  0.828 70.835 4.734 71.609 ;
     RECT  27.792 71.455 29.697 71.609 ;
     RECT  50.544 71.491 52.038 71.609 ;
     RECT  73.62 71.141 73.638 71.609 ;
     RECT  27.036 71.491 27.054 71.617 ;
     RECT  27.792 71.609 28.206 71.617 ;
     RECT  25.776 71.491 26.046 71.645 ;
     RECT  27.036 71.617 28.206 71.645 ;
     RECT  6.732 71.519 8.406 71.653 ;
     RECT  9.972 71.249 10.278 71.681 ;
     RECT  25.992 71.645 26.046 71.681 ;
     RECT  42.66 71.491 48.942 71.689 ;
     RECT  22.824 70.799 22.842 71.717 ;
     RECT  111.78 70.259 113.094 71.717 ;
     RECT  67.032 70.943 68.13 71.725 ;
     RECT  69.012 69.989 69.498 71.725 ;
     RECT  26.028 71.681 26.046 71.761 ;
     RECT  114.696 71.117 119.862 71.761 ;
     RECT  42.66 71.689 49.05 71.789 ;
     RECT  42.66 71.789 48.834 71.845 ;
     RECT  26.028 71.761 26.298 71.879 ;
     RECT  27.072 71.645 28.206 71.879 ;
     RECT  42.228 71.845 48.834 71.885 ;
     RECT  57.888 70.061 58.41 71.887 ;
     RECT  0.828 71.609 4.266 71.915 ;
     RECT  26.028 71.879 26.118 71.915 ;
     RECT  30.42 71.483 31.014 71.915 ;
     RECT  114.552 71.761 119.862 71.915 ;
     RECT  99.615 69.899 99.897 71.923 ;
     RECT  100.728 69.529 100.746 71.923 ;
     RECT  107.28 71.069 107.622 71.923 ;
     RECT  111.78 71.717 112.446 71.951 ;
     RECT  40.215 71.347 41.094 71.959 ;
     RECT  53.856 71.581 55.278 71.987 ;
     RECT  50.544 71.609 51.894 72.023 ;
     RECT  6.336 71.653 8.406 72.031 ;
     RECT  70.344 71.213 70.578 72.031 ;
     RECT  106.272 71.177 106.29 72.031 ;
     RECT  107.136 71.923 107.622 72.031 ;
     RECT  110.415 68.945 110.862 72.031 ;
     RECT  110.415 72.031 110.97 72.091 ;
     RECT  99.615 71.923 100.746 72.121 ;
     RECT  98.028 70.295 98.334 72.139 ;
     RECT  103.176 71.339 103.734 72.139 ;
     RECT  40.215 71.959 41.598 72.149 ;
     RECT  42.66 71.885 48.834 72.149 ;
     RECT  54.036 71.987 55.278 72.149 ;
     RECT  110.415 72.091 111.366 72.149 ;
     RECT  0.828 71.915 3.258 72.185 ;
     RECT  110.415 72.149 110.97 72.185 ;
     RECT  105.015 68.144 105.297 72.229 ;
     RECT  110.415 72.185 110.862 72.229 ;
     RECT  67.032 71.725 69.534 72.265 ;
     RECT  70.308 72.031 70.578 72.265 ;
     RECT  103.176 72.139 103.842 72.265 ;
     RECT  99.615 72.121 101.394 72.269 ;
     RECT  67.032 72.265 71.262 72.293 ;
     RECT  57.888 71.887 58.482 72.301 ;
     RECT  61.236 70.979 62.154 72.301 ;
     RECT  106.272 72.031 107.622 72.301 ;
     RECT  104.796 72.229 105.297 72.329 ;
     RECT  5.652 72.031 8.406 72.391 ;
     RECT  11.736 71.221 11.754 72.391 ;
     RECT  9.972 71.681 9.99 72.419 ;
     RECT  40.215 72.149 41.49 72.419 ;
     RECT  63.684 70.951 65.574 72.419 ;
     RECT  103.176 72.265 103.986 72.419 ;
     RECT  112.284 71.951 112.446 72.419 ;
     RECT  67.032 72.293 70.398 72.427 ;
     RECT  97.128 72.229 97.146 72.427 ;
     RECT  98.028 72.139 98.622 72.427 ;
     RECT  114.696 71.915 119.862 72.427 ;
     RECT  3.996 71.915 4.266 72.455 ;
     RECT  103.176 72.419 103.518 72.455 ;
     RECT  112.284 72.419 112.302 72.455 ;
     RECT  113.58 71.725 113.598 72.455 ;
     RECT  54.036 72.149 55.026 72.461 ;
     RECT  5.652 72.391 8.586 72.463 ;
     RECT  10.908 72.391 11.754 72.463 ;
     RECT  66.924 72.427 70.398 72.463 ;
     RECT  38.016 69.593 38.718 72.499 ;
     RECT  57.852 72.301 58.482 72.499 ;
     RECT  5.58 72.463 8.586 72.523 ;
     RECT  66.816 72.463 70.398 72.527 ;
     RECT  36.036 70.445 36.486 72.535 ;
     RECT  38.016 72.499 39.078 72.535 ;
     RECT  57.852 72.499 58.662 72.535 ;
     RECT  10.836 72.463 11.754 72.563 ;
     RECT  68.328 72.527 70.398 72.563 ;
     RECT  11.268 72.563 11.754 72.571 ;
     RECT  5.328 72.523 8.586 72.599 ;
     RECT  54.72 72.461 55.026 72.599 ;
     RECT  7.815 72.599 8.586 72.661 ;
     RECT  36.036 72.535 37.026 72.661 ;
     RECT  37.8 72.535 39.078 72.661 ;
     RECT  11.268 72.571 11.934 72.689 ;
     RECT  40.215 72.419 41.31 72.689 ;
     RECT  45.216 72.149 48.834 72.689 ;
     RECT  50.544 72.023 51.57 72.689 ;
     RECT  40.215 72.689 41.058 72.697 ;
     RECT  109.188 72.031 109.206 72.697 ;
     RECT  114.696 72.427 119.898 72.697 ;
     RECT  0.072 70.565 0.09 72.725 ;
     RECT  5.328 72.599 6.858 72.725 ;
     RECT  101.196 72.269 101.394 72.725 ;
     RECT  57.744 72.535 58.734 72.733 ;
     RECT  60.264 71.213 60.426 72.733 ;
     RECT  61.236 72.301 62.838 72.733 ;
     RECT  109.188 72.697 109.386 72.733 ;
     RECT  45.216 72.689 48.654 72.761 ;
     RECT  30.42 71.915 30.834 72.769 ;
     RECT  5.58 72.725 6.858 72.797 ;
     RECT  13.068 71.581 13.497 72.805 ;
     RECT  76.068 66.515 76.086 72.833 ;
     RECT  30.42 72.769 31.05 72.841 ;
     RECT  33.516 70.681 35.097 72.841 ;
     RECT  109.188 72.733 109.494 72.841 ;
     RECT  110.268 72.229 110.862 72.841 ;
     RECT  6.336 72.797 6.858 72.869 ;
     RECT  36.036 72.661 39.078 72.869 ;
     RECT  42.66 72.149 44.406 72.869 ;
     RECT  54.72 72.599 54.81 72.869 ;
     RECT  60.264 72.733 62.838 72.869 ;
     RECT  71.244 72.293 71.262 72.869 ;
     RECT  13.068 72.805 13.698 72.931 ;
     RECT  30.42 72.841 31.122 72.931 ;
     RECT  57.744 72.733 59.454 72.931 ;
     RECT  60.264 72.869 62.154 72.931 ;
     RECT  93.492 71.117 95.166 72.931 ;
     RECT  97.128 72.427 98.622 72.931 ;
     RECT  18.615 70.529 18.897 72.955 ;
     RECT  7.815 72.661 8.946 72.959 ;
     RECT  11.268 72.689 11.322 72.959 ;
     RECT  27.576 71.879 28.206 72.959 ;
     RECT  37.008 72.869 39.078 72.959 ;
     RECT  42.66 72.869 42.894 72.959 ;
     RECT  97.128 72.931 98.802 72.959 ;
     RECT  7.815 72.959 8.802 72.995 ;
     RECT  72 71.141 72.897 72.995 ;
     RECT  109.188 72.841 110.862 72.995 ;
     RECT  30.42 72.931 31.23 73.039 ;
     RECT  101.376 72.725 101.394 73.039 ;
     RECT  57.744 72.931 62.154 73.067 ;
     RECT  66.816 72.527 67.497 73.067 ;
     RECT  98.604 72.959 98.802 73.067 ;
     RECT  109.188 72.995 109.386 73.075 ;
     RECT  7.815 72.995 8.622 73.103 ;
     RECT  42.66 72.959 42.822 73.103 ;
     RECT  44.028 72.869 44.406 73.103 ;
     RECT  101.376 73.039 101.43 73.103 ;
     RECT  17.316 73.075 17.334 73.111 ;
     RECT  18.615 72.955 19.35 73.111 ;
     RECT  93.456 72.931 95.166 73.111 ;
     RECT  106.056 72.301 107.622 73.111 ;
     RECT  85.572 69.593 85.59 73.139 ;
     RECT  114.552 72.697 119.898 73.139 ;
     RECT  97.128 72.959 97.254 73.201 ;
     RECT  44.028 73.103 44.334 73.229 ;
     RECT  45.216 72.761 48.474 73.229 ;
     RECT  63.684 72.419 65.322 73.229 ;
     RECT  99.615 72.269 100.458 73.229 ;
     RECT  111.96 73.111 111.978 73.229 ;
     RECT  115.272 73.139 119.898 73.229 ;
     RECT  1.404 72.185 3.258 73.265 ;
     RECT  57.744 73.067 62.097 73.265 ;
     RECT  113.04 72.931 113.058 73.265 ;
     RECT  101.412 73.103 101.43 73.301 ;
     RECT  29.415 71.609 29.697 73.309 ;
     RECT  103.212 72.455 103.518 73.309 ;
     RECT  30.42 73.039 31.266 73.345 ;
     RECT  33.12 72.841 35.097 73.345 ;
     RECT  106.056 73.111 107.658 73.345 ;
     RECT  61.632 73.265 62.097 73.373 ;
     RECT  106.02 73.345 107.658 73.373 ;
     RECT  4.176 72.455 4.266 73.381 ;
     RECT  33.084 73.345 35.097 73.381 ;
     RECT  63.684 73.229 64.062 73.381 ;
     RECT  103.068 73.309 103.518 73.381 ;
     RECT  37.08 72.959 39.078 73.409 ;
     RECT  57.744 73.265 60.57 73.409 ;
     RECT  2.304 73.265 3.258 73.471 ;
     RECT  4.176 73.381 4.59 73.471 ;
     RECT  63.144 73.381 64.062 73.499 ;
     RECT  98.604 73.067 98.622 73.499 ;
     RECT  103.068 73.381 103.59 73.499 ;
     RECT  106.02 73.373 107.586 73.499 ;
     RECT  115.272 73.229 119.106 73.499 ;
     RECT  2.304 73.471 4.59 73.507 ;
     RECT  5.58 72.797 5.598 73.507 ;
     RECT  16.56 73.111 17.334 73.507 ;
     RECT  39.924 72.697 41.058 73.535 ;
     RECT  57.744 73.409 58.95 73.535 ;
     RECT  63.144 73.499 63.702 73.535 ;
     RECT  106.02 73.499 107.478 73.535 ;
     RECT  68.328 72.563 69.966 73.571 ;
     RECT  93.456 73.111 95.202 73.579 ;
     RECT  13.068 72.931 14.166 73.615 ;
     RECT  18.615 73.111 19.494 73.615 ;
     RECT  30.42 73.345 31.59 73.615 ;
     RECT  68.328 73.571 69.534 73.643 ;
     RECT  18.216 73.615 19.494 73.651 ;
     RECT  64.836 73.229 65.322 73.651 ;
     RECT  27.576 72.959 27.882 73.679 ;
     RECT  60.264 73.409 60.57 73.679 ;
     RECT  96.948 73.201 97.254 73.679 ;
     RECT  99.615 73.229 100.35 73.679 ;
     RECT  103.248 73.499 103.59 73.679 ;
     RECT  16.524 73.507 17.334 73.741 ;
     RECT  18.216 73.651 20.358 73.741 ;
     RECT  64.836 73.651 65.538 73.741 ;
     RECT  93.456 73.579 95.526 73.741 ;
     RECT  96.948 73.679 97.182 73.741 ;
     RECT  16.524 73.741 20.358 73.769 ;
     RECT  30.42 73.615 31.806 73.769 ;
     RECT  32.58 73.381 35.097 73.769 ;
     RECT  63.324 73.535 63.702 73.769 ;
     RECT  66.888 73.067 67.497 73.769 ;
     RECT  110.124 72.995 110.862 73.777 ;
     RECT  16.524 73.769 20.178 73.805 ;
     RECT  57.744 73.535 58.806 73.805 ;
     RECT  109.152 73.075 109.386 73.805 ;
     RECT  21.888 73.003 21.906 73.813 ;
     RECT  93.456 73.741 95.634 73.813 ;
     RECT  13.068 73.615 14.598 73.841 ;
     RECT  58.608 73.805 58.806 73.841 ;
     RECT  64.836 73.741 66.006 73.841 ;
     RECT  91.764 72.931 91.782 73.841 ;
     RECT  13.215 73.841 14.598 73.849 ;
     RECT  50.544 72.689 51.39 73.849 ;
     RECT  57.744 73.805 57.87 73.849 ;
     RECT  2.304 73.507 5.598 73.877 ;
     RECT  92.52 71.213 92.538 73.885 ;
     RECT  93.456 73.813 95.742 73.885 ;
     RECT  58.644 73.841 58.806 73.913 ;
     RECT  7.815 73.103 8.586 73.921 ;
     RECT  64.908 73.841 66.006 73.921 ;
     RECT  92.52 73.885 95.742 73.921 ;
     RECT  26.028 71.915 26.046 73.949 ;
     RECT  54.72 73.849 54.738 73.949 ;
     RECT  58.644 73.913 58.698 73.949 ;
     RECT  30.42 73.769 31.662 73.997 ;
     RECT  37.296 73.409 39.078 73.997 ;
     RECT  117.396 73.499 119.106 73.997 ;
     RECT  92.52 73.921 95.814 74.005 ;
     RECT  21.636 73.813 21.906 74.011 ;
     RECT  17.244 73.805 20.178 74.039 ;
     RECT  33.12 73.769 35.097 74.039 ;
     RECT  60.408 73.679 60.57 74.039 ;
     RECT  61.776 73.373 62.097 74.039 ;
     RECT  64.908 73.921 66.042 74.039 ;
     RECT  92.34 74.005 95.814 74.039 ;
     RECT  92.34 74.039 92.358 74.045 ;
     RECT  93.564 74.039 95.598 74.045 ;
     RECT  5.22 73.877 5.598 74.047 ;
     RECT  6.336 72.869 6.354 74.047 ;
     RECT  1.404 73.265 1.566 74.075 ;
     RECT  60.408 74.039 60.426 74.075 ;
     RECT  67.14 73.769 67.497 74.075 ;
     RECT  21.636 74.011 22.05 74.083 ;
     RECT  115.272 73.499 116.406 74.083 ;
     RECT  110.124 73.777 111.258 74.093 ;
     RECT  118.584 73.997 119.106 74.093 ;
     RECT  17.244 74.039 18.99 74.111 ;
     RECT  68.328 73.643 69.498 74.111 ;
     RECT  5.22 74.047 6.354 74.119 ;
     RECT  7.416 73.921 8.586 74.119 ;
     RECT  21.636 74.083 22.23 74.119 ;
     RECT  21.636 74.119 23.058 74.155 ;
     RECT  24.015 71.483 24.297 74.155 ;
     RECT  27.576 73.679 27.81 74.155 ;
     RECT  5.22 74.119 8.586 74.183 ;
     RECT  114.12 74.083 116.406 74.189 ;
     RECT  21.636 74.155 24.297 74.191 ;
     RECT  44.244 73.229 44.334 74.191 ;
     RECT  45.216 73.229 46.026 74.191 ;
     RECT  96.66 73.741 97.182 74.191 ;
     RECT  119.844 73.229 119.898 74.219 ;
     RECT  7.815 74.183 8.586 74.281 ;
     RECT  117.396 73.997 117.414 74.285 ;
     RECT  63.576 73.769 63.594 74.309 ;
     RECT  93.564 74.045 95.022 74.309 ;
     RECT  110.268 74.093 111.258 74.309 ;
     RECT  114.12 74.189 116.298 74.309 ;
     RECT  119.088 74.093 119.106 74.309 ;
     RECT  115.596 74.309 116.298 74.333 ;
     RECT  1.404 74.075 1.422 74.345 ;
     RECT  5.22 74.183 7.038 74.345 ;
     RECT  9.72 73.111 9.738 74.345 ;
     RECT  96.516 74.191 97.182 74.345 ;
     RECT  110.268 74.309 111.114 74.345 ;
     RECT  5.328 74.345 7.038 74.381 ;
     RECT  21.636 74.191 24.606 74.381 ;
     RECT  68.364 74.111 69.498 74.381 ;
     RECT  7.815 74.281 8.91 74.389 ;
     RECT  49.932 73.849 51.39 74.389 ;
     RECT  105.015 72.329 105.297 74.389 ;
     RECT  106.092 73.535 106.902 74.389 ;
     RECT  104.904 74.389 106.902 74.417 ;
     RECT  68.544 74.381 69.498 74.429 ;
     RECT  17.244 74.111 18.954 74.453 ;
     RECT  23.724 74.381 24.606 74.461 ;
     RECT  25.344 74.119 25.362 74.461 ;
     RECT  53.316 73.813 53.334 74.461 ;
     RECT  106.524 74.417 106.902 74.461 ;
     RECT  112.5 73.543 112.518 74.461 ;
     RECT  113.328 74.011 113.346 74.461 ;
     RECT  104.904 74.417 105.426 74.489 ;
     RECT  115.704 74.333 116.298 74.489 ;
     RECT  42.732 73.103 42.822 74.551 ;
     RECT  103.248 73.679 103.518 74.551 ;
     RECT  112.5 74.461 113.346 74.551 ;
     RECT  114.12 74.309 114.282 74.551 ;
     RECT  119.808 74.395 119.826 74.573 ;
     RECT  5.328 74.381 6.21 74.579 ;
     RECT  19.908 74.039 20.178 74.579 ;
     RECT  21.636 74.381 22.878 74.579 ;
     RECT  23.724 74.461 25.362 74.579 ;
     RECT  68.94 74.429 69.498 74.579 ;
     RECT  17.244 74.453 18.897 74.615 ;
     RECT  23.724 74.579 24.462 74.621 ;
     RECT  49.932 74.389 51.462 74.623 ;
     RECT  23.796 74.621 24.462 74.651 ;
     RECT  46.8 73.229 48.474 74.651 ;
     RECT  53.316 74.461 53.406 74.651 ;
     RECT  57.636 73.849 57.87 74.651 ;
     RECT  102.6 74.551 103.518 74.651 ;
     RECT  5.328 74.579 5.346 74.669 ;
     RECT  7.815 74.389 9.378 74.687 ;
     RECT  19.908 74.579 20.07 74.687 ;
     RECT  23.796 74.651 24.297 74.687 ;
     RECT  44.244 74.191 46.026 74.695 ;
     RECT  46.8 74.651 48.366 74.695 ;
     RECT  53.316 74.651 53.37 74.695 ;
     RECT  58.644 73.949 58.662 74.723 ;
     RECT  21.636 74.579 22.77 74.731 ;
     RECT  44.244 74.695 48.366 74.731 ;
     RECT  106.524 74.461 107.082 74.731 ;
     RECT  49.932 74.623 51.606 74.759 ;
     RECT  21.168 74.731 22.77 74.821 ;
     RECT  37.656 73.997 39.078 74.821 ;
     RECT  40.215 73.535 41.058 74.821 ;
     RECT  102.888 74.651 103.518 74.821 ;
     RECT  7.815 74.687 8.514 74.849 ;
     RECT  9.288 74.687 9.378 74.849 ;
     RECT  104.904 74.489 105.297 74.849 ;
     RECT  112.5 74.551 114.282 74.849 ;
     RECT  52.992 74.695 53.37 74.857 ;
     RECT  26.928 74.155 27.81 74.893 ;
     RECT  106.524 74.731 107.334 74.893 ;
     RECT  6.084 74.579 6.21 74.909 ;
     RECT  7.815 74.849 8.37 74.909 ;
     RECT  49.932 74.759 51.534 74.909 ;
     RECT  52.344 74.857 53.37 74.909 ;
     RECT  50.76 74.909 51.534 74.921 ;
     RECT  110.268 74.345 110.754 74.929 ;
     RECT  20.988 74.821 22.77 74.957 ;
     RECT  25.272 74.579 25.362 74.957 ;
     RECT  50.832 74.921 51.534 74.957 ;
     RECT  57.852 74.651 57.87 74.957 ;
     RECT  28.764 73.309 29.697 74.965 ;
     RECT  30.42 73.997 31.59 74.965 ;
     RECT  102.888 74.821 103.626 74.965 ;
     RECT  110.052 74.929 110.754 74.993 ;
     RECT  106.524 74.893 107.37 75.001 ;
     RECT  7.02 74.381 7.038 75.029 ;
     RECT  9.36 74.849 9.378 75.029 ;
     RECT  20.988 74.957 22.23 75.029 ;
     RECT  49.932 74.909 49.95 75.091 ;
     RECT  21.492 75.029 22.23 75.119 ;
     RECT  26.604 74.893 27.81 75.119 ;
     RECT  37.656 74.821 41.058 75.119 ;
     RECT  49.644 75.091 49.95 75.119 ;
     RECT  112.5 74.849 114.21 75.119 ;
     RECT  93.564 74.309 94.626 75.155 ;
     RECT  112.5 75.119 112.878 75.155 ;
     RECT  113.616 75.119 114.138 75.155 ;
     RECT  44.208 74.731 48.366 75.163 ;
     RECT  96.948 74.345 97.182 75.163 ;
     RECT  37.656 75.119 38.718 75.191 ;
     RECT  44.1 75.163 48.366 75.191 ;
     RECT  52.992 74.909 53.37 75.191 ;
     RECT  106.524 75.001 107.442 75.191 ;
     RECT  112.68 75.155 112.878 75.191 ;
     RECT  106.524 75.191 106.686 75.197 ;
     RECT  49.644 75.119 49.662 75.199 ;
     RECT  49.608 75.199 49.662 75.2 ;
     RECT  44.1 75.191 45.954 75.227 ;
     RECT  52.992 75.191 53.01 75.227 ;
     RECT  106.596 75.197 106.686 75.227 ;
     RECT  107.424 75.191 107.442 75.227 ;
     RECT  113.616 75.155 114.102 75.227 ;
     RECT  115.704 74.489 116.097 75.227 ;
     RECT  49.608 75.2 49.626 75.235 ;
     RECT  44.1 75.227 44.478 75.263 ;
     RECT  109.152 73.805 109.17 75.271 ;
     RECT  110.052 74.993 110.697 75.271 ;
     RECT  49.284 75.235 49.626 75.299 ;
     RECT  94.215 75.155 94.626 75.389 ;
     RECT  109.152 75.271 110.697 75.389 ;
     RECT  113.94 75.227 114.102 75.389 ;
     RECT  13.215 73.849 14.886 75.397 ;
     RECT  13.215 75.397 15.03 75.425 ;
     RECT  28.764 74.965 31.59 75.425 ;
     RECT  45.36 75.227 45.954 75.425 ;
     RECT  94.215 75.389 94.554 75.425 ;
     RECT  113.94 75.389 113.958 75.425 ;
     RECT  39.456 75.119 40.698 75.437 ;
     RECT  26.928 75.119 27.81 75.469 ;
     RECT  28.764 75.425 31.122 75.469 ;
     RECT  45.36 75.425 45.897 75.497 ;
     RECT  109.116 75.499 109.134 75.539 ;
     RECT  14.292 75.425 15.03 75.541 ;
     RECT  42.732 74.551 43.182 75.541 ;
     RECT  44.208 75.263 44.478 75.569 ;
     RECT  32.868 75.397 32.886 75.631 ;
     RECT  33.66 74.039 35.097 75.631 ;
     RECT  6.444 75.541 6.462 75.659 ;
     RECT  50.832 74.957 51.297 75.659 ;
     RECT  23.832 74.687 24.297 75.667 ;
     RECT  99.615 73.679 99.897 75.667 ;
     RECT  102.888 74.965 104.13 75.667 ;
     RECT  14.292 75.541 15.21 75.695 ;
     RECT  42.732 75.541 43.254 75.695 ;
     RECT  110.052 75.389 110.697 75.695 ;
     RECT  11.304 72.959 11.322 75.703 ;
     RECT  9.9 75.541 10.026 75.731 ;
     RECT  32.868 75.631 35.097 75.731 ;
     RECT  7.815 74.909 8.097 75.739 ;
     RECT  99.252 75.667 99.897 75.739 ;
     RECT  26.928 75.469 31.122 75.767 ;
     RECT  27.576 75.767 31.122 75.773 ;
     RECT  16.452 75.397 16.47 75.775 ;
     RECT  17.244 74.615 17.766 75.775 ;
     RECT  96.948 75.163 97.506 75.775 ;
     RECT  16.452 75.775 17.766 75.803 ;
     RECT  44.352 75.569 44.478 75.803 ;
     RECT  96.948 75.775 97.938 75.803 ;
     RECT  10.08 75.775 10.17 75.811 ;
     RECT  99 75.739 99.897 75.811 ;
     RECT  101.16 75.199 101.178 75.811 ;
     RECT  27.576 75.773 31.086 75.812 ;
     RECT  99 75.811 100.098 75.883 ;
     RECT  101.16 75.811 101.286 75.883 ;
     RECT  102.6 75.667 104.13 75.929 ;
     RECT  99 75.883 101.286 75.937 ;
     RECT  2.304 73.877 4.194 75.965 ;
     RECT  102.744 75.929 104.13 76.037 ;
     RECT  17.1 75.803 17.766 76.081 ;
     RECT  33.66 75.731 35.097 76.081 ;
     RECT  36.036 72.869 36.27 76.081 ;
     RECT  46.8 75.191 48.366 76.081 ;
     RECT  99 75.937 101.358 76.109 ;
     RECT  102.744 76.037 103.374 76.109 ;
     RECT  11.232 75.703 11.322 76.171 ;
     RECT  27.576 75.812 31.05 76.199 ;
     RECT  32.472 75.775 32.49 76.199 ;
     RECT  96.948 75.803 97.146 76.199 ;
     RECT  97.92 75.803 97.938 76.199 ;
     RECT  99 76.109 101.286 76.199 ;
     RECT  102.96 76.109 103.374 76.199 ;
     RECT  104.112 76.037 104.13 76.199 ;
     RECT  39.924 75.437 40.698 76.207 ;
     RECT  7.704 75.739 8.097 76.235 ;
     RECT  44.388 75.803 44.478 76.235 ;
     RECT  96.948 76.199 96.966 76.235 ;
     RECT  103.176 76.199 103.194 76.235 ;
     RECT  38.016 75.191 38.718 76.243 ;
     RECT  44.388 76.235 44.406 76.271 ;
     RECT  99 76.199 100.35 76.309 ;
     RECT  98.964 76.309 100.35 76.349 ;
     RECT  18.615 74.615 18.897 76.351 ;
     RECT  46.8 76.081 48.438 76.351 ;
     RECT  49.284 75.299 49.302 76.351 ;
     RECT  10.08 75.811 10.242 76.397 ;
     RECT  99.615 76.349 100.35 76.397 ;
     RECT  11.232 76.171 12.006 76.459 ;
     RECT  13.215 75.425 13.497 76.459 ;
     RECT  18.615 76.351 19.422 76.469 ;
     RECT  11.232 76.459 13.497 76.505 ;
     RECT  17.1 76.081 17.838 76.505 ;
     RECT  17.352 76.505 17.838 76.507 ;
     RECT  33.66 76.081 36.27 76.541 ;
     RECT  19.872 76.549 19.89 76.621 ;
     RECT  9.252 76.363 9.27 76.699 ;
     RECT  35.964 76.541 36.27 76.739 ;
     RECT  17.352 76.507 17.874 76.775 ;
     RECT  11.232 76.505 12.222 76.783 ;
     RECT  11.016 76.783 12.222 76.811 ;
     RECT  17.352 76.775 17.73 76.811 ;
     RECT  18.615 76.469 18.897 76.855 ;
     RECT  12.204 76.811 12.222 76.883 ;
     RECT  2.34 75.965 4.194 76.891 ;
     RECT  8.928 76.699 9.27 76.919 ;
     RECT  17.352 76.811 17.694 76.919 ;
     RECT  46.8 76.351 49.302 76.919 ;
     RECT  16.56 76.855 16.578 76.925 ;
     RECT  22.212 75.119 22.23 77.017 ;
     RECT  8.928 76.919 9.126 77.045 ;
     RECT  14.292 75.695 15.138 77.045 ;
     RECT  15.012 77.045 15.138 77.089 ;
     RECT  15.012 77.089 15.246 77.117 ;
     RECT  5.76 76.621 5.778 77.161 ;
     RECT  33.66 76.541 35.19 77.189 ;
     RECT  2.34 76.891 4.338 77.359 ;
     RECT  2.34 77.359 4.59 77.431 ;
     RECT  25.344 74.957 25.362 77.515 ;
     RECT  2.34 77.431 4.698 77.549 ;
     RECT  5.76 77.161 6.282 77.557 ;
     RECT  7.815 76.235 8.097 77.557 ;
     RECT  42.732 75.695 42.822 77.585 ;
     RECT  42.804 77.585 42.822 77.593 ;
     RECT  5.724 77.557 6.282 77.629 ;
     RECT  13.215 76.505 13.497 77.629 ;
     RECT  19.872 76.621 20.07 77.629 ;
     RECT  5.544 77.629 6.282 77.657 ;
     RECT  19.872 77.629 20.178 77.701 ;
     RECT  5.544 77.657 5.778 77.729 ;
     RECT  13.215 77.629 13.554 77.791 ;
     RECT  2.34 77.549 4.59 77.855 ;
     RECT  23.328 75.667 24.297 77.899 ;
     RECT  68.94 74.579 69.318 77.935 ;
     RECT  7.056 77.557 8.097 77.971 ;
     RECT  19.872 77.701 20.394 77.971 ;
     RECT  23.292 77.899 24.297 77.971 ;
     RECT  25.344 77.515 25.83 77.971 ;
     RECT  22.212 77.017 22.266 77.999 ;
     RECT  25.092 77.971 25.83 78.089 ;
     RECT  26.748 77.971 26.766 78.089 ;
     RECT  27.576 76.199 30.798 78.089 ;
     RECT  45.504 75.497 45.897 78.097 ;
     RECT  27.576 78.089 27.81 78.125 ;
     RECT  45.504 78.097 45.99 78.133 ;
     RECT  45.432 78.133 45.99 78.139 ;
     RECT  23.184 77.971 24.297 78.169 ;
     RECT  25.092 78.089 25.47 78.169 ;
     RECT  19.872 77.971 21.078 78.197 ;
     RECT  22.248 77.999 22.266 78.197 ;
     RECT  45.432 78.139 46.134 78.197 ;
     RECT  19.872 78.197 20.79 78.331 ;
     RECT  23.184 78.169 25.47 78.331 ;
     RECT  17.352 76.919 17.37 78.359 ;
     RECT  5.76 77.729 5.778 78.395 ;
     RECT  19.8 78.331 20.79 78.403 ;
     RECT  39.816 76.207 40.698 78.403 ;
     RECT  42.804 77.593 43.218 78.403 ;
     RECT  39.708 78.403 40.698 78.439 ;
     RECT  19.728 78.403 20.79 78.475 ;
     RECT  37.296 76.243 38.718 78.503 ;
     RECT  6.804 77.971 8.097 78.511 ;
     RECT  10.224 76.397 10.242 78.511 ;
     RECT  38.304 78.503 38.718 78.511 ;
     RECT  38.304 78.511 38.754 78.629 ;
     RECT  45.504 78.197 46.134 78.629 ;
     RECT  39.636 78.439 40.698 78.637 ;
     RECT  22.536 78.331 25.47 78.665 ;
     RECT  28.764 78.089 30.294 78.665 ;
     RECT  39.564 78.637 40.698 78.665 ;
     RECT  47.052 76.919 49.302 78.665 ;
     RECT  36.036 76.739 36.27 78.673 ;
     RECT  38.7 78.629 38.754 78.673 ;
     RECT  19.692 78.475 20.79 78.701 ;
     RECT  38.7 78.673 38.826 78.709 ;
     RECT  39.564 78.665 40.554 78.709 ;
     RECT  11.016 76.811 11.25 78.781 ;
     RECT  11.016 78.781 11.322 78.899 ;
     RECT  38.7 78.709 40.554 78.899 ;
     RECT  10.224 78.511 10.278 78.943 ;
     RECT  11.016 78.899 11.25 78.943 ;
     RECT  2.415 77.855 4.59 78.955 ;
     RECT  6.084 78.511 8.097 78.971 ;
     RECT  9.828 78.943 11.25 78.971 ;
     RECT  9.828 78.971 11.106 78.979 ;
     RECT  2.415 78.955 4.914 79.051 ;
     RECT  13.176 77.791 13.554 79.051 ;
     RECT  9.612 78.979 11.106 79.141 ;
     RECT  9.54 79.141 11.106 79.169 ;
     RECT  38.7 78.899 38.826 79.169 ;
     RECT  39.564 78.899 40.554 79.169 ;
     RECT  6.84 78.971 8.097 79.205 ;
     RECT  6.876 79.205 8.097 79.213 ;
     RECT  12.06 79.051 12.078 79.241 ;
     RECT  13.104 79.051 13.554 79.249 ;
     RECT  15.228 77.117 15.246 79.249 ;
     RECT  18.54 76.855 18.897 79.249 ;
     RECT  27.576 78.125 27.594 79.249 ;
     RECT  28.8 78.665 30.294 79.249 ;
     RECT  2.415 79.051 5.202 79.277 ;
     RECT  9.54 79.169 11.034 79.277 ;
     RECT  49.284 78.665 49.302 79.277 ;
     RECT  5.184 79.277 5.202 79.285 ;
     RECT  6.084 78.971 6.102 79.285 ;
     RECT  13.068 79.249 13.554 79.285 ;
     RECT  45.615 78.629 46.134 79.285 ;
     RECT  14.688 79.249 15.246 79.291 ;
     RECT  28.8 79.249 30.366 79.321 ;
     RECT  42.804 78.403 43.362 79.321 ;
     RECT  6.876 79.213 8.298 79.439 ;
     RECT  12.996 79.285 13.554 79.439 ;
     RECT  14.4 79.291 15.246 79.439 ;
     RECT  13.068 79.439 13.554 79.447 ;
     RECT  42.804 79.321 43.938 79.447 ;
     RECT  6.876 79.439 8.097 79.475 ;
     RECT  13.068 79.447 13.626 79.483 ;
     RECT  28.8 79.321 30.546 79.483 ;
     RECT  2.415 79.277 4.41 79.511 ;
     RECT  9.54 79.277 10.926 79.511 ;
     RECT  17.964 79.249 18.897 79.511 ;
     RECT  27.54 79.249 27.594 79.511 ;
     RECT  42.768 79.447 43.938 79.511 ;
     RECT  28.8 79.483 30.798 79.519 ;
     RECT  27.576 79.511 27.594 79.547 ;
     RECT  16.668 79.483 16.686 79.555 ;
     RECT  5.184 79.285 6.102 79.583 ;
     RECT  9.684 79.511 9.702 79.583 ;
     RECT  42.768 79.511 43.398 79.583 ;
     RECT  22.608 78.665 25.47 79.591 ;
     RECT  36.036 78.673 36.342 79.591 ;
     RECT  45.615 79.285 46.206 79.591 ;
     RECT  47.052 78.665 48.402 79.591 ;
     RECT  5.184 79.583 5.202 79.619 ;
     RECT  10.836 79.511 10.926 79.619 ;
     RECT  14.688 79.439 15.246 79.619 ;
     RECT  13.068 79.483 13.806 79.709 ;
     RECT  14.724 79.619 15.246 79.709 ;
     RECT  28.8 79.519 31.302 79.709 ;
     RECT  14.724 79.709 15.138 79.745 ;
     RECT  16.668 79.555 16.83 79.745 ;
     RECT  13.068 79.709 13.662 79.781 ;
     RECT  16.812 79.745 16.83 79.781 ;
     RECT  41.976 79.555 41.994 79.789 ;
     RECT  42.768 79.583 43.362 79.789 ;
     RECT  103.212 79.591 103.23 79.805 ;
     RECT  41.976 79.789 43.362 79.817 ;
     RECT  33.66 77.189 35.097 79.819 ;
     RECT  18.108 79.511 18.897 79.825 ;
     RECT  19.728 78.701 20.79 79.825 ;
     RECT  41.976 79.817 43.254 79.825 ;
     RECT  18.108 79.825 20.79 79.951 ;
     RECT  14.832 79.745 15.138 79.979 ;
     RECT  45.615 79.591 48.402 79.979 ;
     RECT  39.564 79.169 40.497 79.987 ;
     RECT  41.472 79.825 43.254 79.987 ;
     RECT  101.988 79.243 102.006 79.997 ;
     RECT  33.624 79.819 35.097 80.015 ;
     RECT  18.108 79.951 21.222 80.059 ;
     RECT  14.904 79.979 15.138 80.123 ;
     RECT  28.8 79.709 30.366 80.123 ;
     RECT  47.052 79.979 48.402 80.131 ;
     RECT  18.108 80.059 21.294 80.249 ;
     RECT  47.052 80.131 48.438 80.249 ;
     RECT  18.324 80.249 21.294 80.285 ;
     RECT  33.66 80.015 35.097 80.293 ;
     RECT  33.66 80.293 35.118 80.321 ;
     RECT  39.564 79.987 43.254 80.357 ;
     RECT  18.615 80.285 21.294 80.365 ;
     RECT  22.608 79.591 25.938 80.365 ;
     RECT  37.296 78.503 37.314 80.401 ;
     RECT  38.7 79.169 38.718 80.401 ;
     RECT  39.564 80.357 40.554 80.401 ;
     RECT  37.296 80.401 37.386 80.519 ;
     RECT  18.615 80.365 21.726 80.527 ;
     RECT  22.536 80.365 25.938 80.527 ;
     RECT  18.615 80.527 25.938 80.555 ;
     RECT  37.368 80.519 37.386 80.555 ;
     RECT  38.7 80.401 40.554 80.555 ;
     RECT  33.696 80.321 35.118 80.599 ;
     RECT  35.964 79.591 36.342 80.599 ;
     RECT  38.7 80.555 39.186 80.663 ;
     RECT  41.4 80.357 43.254 80.663 ;
     RECT  41.4 80.663 42.138 80.789 ;
     RECT  20.016 80.555 25.938 80.825 ;
     RECT  41.4 80.789 42.03 80.825 ;
     RECT  20.016 80.825 21.834 80.861 ;
     RECT  20.016 80.861 21.726 80.897 ;
     RECT  41.4 80.825 41.922 80.897 ;
     RECT  2.415 79.511 3.69 80.941 ;
     RECT  6.084 79.583 6.102 80.941 ;
     RECT  6.876 79.475 6.894 80.941 ;
     RECT  20.016 80.897 21.438 80.969 ;
     RECT  33.696 80.599 36.342 80.969 ;
     RECT  2.415 80.941 3.978 81.059 ;
     RECT  20.016 80.969 21.294 81.131 ;
     RECT  6.084 80.941 6.894 81.139 ;
     RECT  2.415 81.059 3.69 81.203 ;
     RECT  4.536 81.067 4.554 81.211 ;
     RECT  5.904 81.139 6.93 81.211 ;
     RECT  4.536 81.211 6.93 81.329 ;
     RECT  5.148 81.329 6.93 81.365 ;
     RECT  47.052 80.249 48.294 81.365 ;
     RECT  13.14 79.781 13.662 81.437 ;
     RECT  5.904 81.365 6.93 81.445 ;
     RECT  7.815 79.475 8.097 81.445 ;
     RECT  2.415 81.203 3.15 81.473 ;
     RECT  15.12 80.123 15.138 81.481 ;
     RECT  28.8 80.123 30.33 81.509 ;
     RECT  39.168 80.663 39.186 81.571 ;
     RECT  47.556 81.365 48.294 81.599 ;
     RECT  38.952 81.571 39.186 81.607 ;
     RECT  39.924 80.555 40.554 81.607 ;
     RECT  47.556 81.599 48.006 81.635 ;
     RECT  35.964 80.969 36.342 81.671 ;
     RECT  38.952 81.607 40.554 81.671 ;
     RECT  39.168 81.671 40.554 81.707 ;
     RECT  15.12 81.481 15.318 81.715 ;
     RECT  28.908 81.509 30.33 81.751 ;
     RECT  47.556 81.635 47.574 81.779 ;
     RECT  14.832 81.715 15.318 81.869 ;
     RECT  28.908 81.751 30.438 81.869 ;
     RECT  39.528 81.707 40.554 81.869 ;
     RECT  42.876 80.663 43.254 81.869 ;
     RECT  16.38 81.835 16.398 81.875 ;
     RECT  5.148 81.365 5.166 81.905 ;
     RECT  20.016 81.131 21.222 81.913 ;
     RECT  5.904 81.445 8.097 81.949 ;
     RECT  10.836 79.619 10.854 82.021 ;
     RECT  5.904 81.949 8.73 82.061 ;
     RECT  39.528 81.869 40.497 82.061 ;
     RECT  13.14 81.437 13.59 82.139 ;
     RECT  42.912 81.869 43.254 82.139 ;
     RECT  2.415 81.473 3.114 82.175 ;
     RECT  39.564 82.061 40.497 82.175 ;
     RECT  10.836 82.021 11.25 82.219 ;
     RECT  6.876 82.061 8.73 82.291 ;
     RECT  9.54 82.219 9.558 82.291 ;
     RECT  10.836 82.219 11.394 82.291 ;
     RECT  28.908 81.869 30.402 82.291 ;
     RECT  6.876 82.291 11.862 82.319 ;
     RECT  3.888 82.291 3.906 82.445 ;
     RECT  7.596 82.319 11.862 82.445 ;
     RECT  36.036 81.671 36.342 82.445 ;
     RECT  7.704 82.445 9.702 82.517 ;
     RECT  5.904 82.061 6.102 82.525 ;
     RECT  5.868 82.525 6.102 82.553 ;
     RECT  36.144 82.445 36.342 82.561 ;
     RECT  4.32 82.561 4.338 82.651 ;
     RECT  5.868 82.553 5.922 82.651 ;
     RECT  13.215 82.139 13.59 82.651 ;
     RECT  9.54 82.517 9.702 82.679 ;
     RECT  10.476 82.445 11.502 82.679 ;
     RECT  7.704 82.517 8.658 82.733 ;
     RECT  9.54 82.679 9.558 82.733 ;
     RECT  4.32 82.651 4.41 82.751 ;
     RECT  5.364 82.651 5.922 82.787 ;
     RECT  14.976 81.869 15.318 82.795 ;
     RECT  42.948 82.139 43.254 82.795 ;
     RECT  12.312 82.525 12.33 82.823 ;
     RECT  4.356 82.751 4.41 82.831 ;
     RECT  5.364 82.787 5.382 82.831 ;
     RECT  4.356 82.831 5.382 82.859 ;
     RECT  10.476 82.679 11.394 82.859 ;
     RECT  16.668 82.381 16.686 82.891 ;
     RECT  42.948 82.795 43.29 82.939 ;
     RECT  4.356 82.859 5.274 82.949 ;
     RECT  4.356 82.949 4.374 82.985 ;
     RECT  7.815 82.733 8.658 82.985 ;
     RECT  42.48 82.939 43.29 82.985 ;
     RECT  13.215 82.651 13.734 82.993 ;
     RECT  14.724 82.795 15.318 82.993 ;
     RECT  16.632 82.891 16.686 83.029 ;
     RECT  17.568 80.905 17.586 83.029 ;
     RECT  10.836 82.859 11.394 83.093 ;
     RECT  16.632 83.029 17.586 83.101 ;
     RECT  42.876 82.985 43.29 83.101 ;
     RECT  16.596 83.101 17.586 83.191 ;
     RECT  42.876 83.101 43.398 83.219 ;
     RECT  16.524 83.191 17.586 83.227 ;
     RECT  39.996 82.175 40.497 83.227 ;
     RECT  22.572 80.825 25.938 83.263 ;
     RECT  16.524 83.227 17.73 83.299 ;
     RECT  22.248 83.263 25.938 83.299 ;
     RECT  33.696 80.969 35.097 83.299 ;
     RECT  37.404 83.227 37.422 83.299 ;
     RECT  11.376 83.093 11.394 83.327 ;
     RECT  16.452 83.299 17.766 83.335 ;
     RECT  36.144 82.561 36.378 83.371 ;
     RECT  37.224 83.299 37.422 83.371 ;
     RECT  42.876 83.219 43.254 83.399 ;
     RECT  33.696 83.299 35.154 83.461 ;
     RECT  16.38 83.335 17.766 83.489 ;
     RECT  36 83.371 37.422 83.489 ;
     RECT  38.196 82.291 38.214 83.497 ;
     RECT  39.924 83.227 40.497 83.497 ;
     RECT  41.4 80.897 41.526 83.497 ;
     RECT  13.215 82.993 15.318 83.525 ;
     RECT  33.696 83.461 35.19 83.525 ;
     RECT  38.196 83.497 38.79 83.525 ;
     RECT  16.452 83.489 17.766 83.533 ;
     RECT  18.615 80.555 18.897 83.533 ;
     RECT  16.452 83.533 18.897 83.561 ;
     RECT  38.772 83.525 38.79 83.597 ;
     RECT  34.308 83.525 35.19 83.605 ;
     RECT  36 83.489 37.278 83.605 ;
     RECT  14.544 83.525 15.318 83.669 ;
     RECT  22.248 83.299 26.262 83.669 ;
     RECT  34.308 83.605 37.278 83.669 ;
     RECT  20.016 81.913 21.366 83.731 ;
     RECT  22.248 83.669 22.266 83.731 ;
     RECT  23.292 83.669 26.262 83.731 ;
     RECT  28.8 82.291 30.402 83.767 ;
     RECT  31.284 79.709 31.302 83.767 ;
     RECT  14.544 83.669 14.85 83.795 ;
     RECT  19.944 83.731 21.366 83.803 ;
     RECT  39.924 83.497 41.526 83.839 ;
     RECT  19.944 83.803 21.402 83.867 ;
     RECT  20.088 83.867 21.402 83.899 ;
     RECT  39.924 83.839 41.598 83.903 ;
     RECT  28.8 83.767 31.302 84.001 ;
     RECT  32.94 83.911 32.958 84.029 ;
     RECT  40.215 83.903 41.598 84.029 ;
     RECT  28.62 84.001 31.302 84.037 ;
     RECT  14.544 83.795 14.814 84.065 ;
     RECT  28.62 84.037 32.022 84.065 ;
     RECT  32.004 84.065 32.022 84.077 ;
     RECT  20.088 83.899 21.438 84.145 ;
     RECT  22.176 83.731 22.266 84.145 ;
     RECT  28.62 84.065 31.158 84.173 ;
     RECT  14.688 84.065 14.814 84.209 ;
     RECT  34.308 83.669 35.478 84.221 ;
     RECT  40.215 84.029 40.626 84.221 ;
     RECT  13.215 83.525 13.734 84.299 ;
     RECT  20.088 84.145 22.266 84.299 ;
     RECT  28.62 84.173 30.654 84.299 ;
     RECT  34.815 84.221 35.478 84.317 ;
     RECT  14.796 84.209 14.814 84.335 ;
     RECT  28.62 84.299 30.366 84.335 ;
     RECT  17.136 83.561 18.897 84.343 ;
     RECT  23.292 83.731 26.55 84.407 ;
     RECT  17.064 84.343 18.897 84.443 ;
     RECT  22.176 84.299 22.266 84.451 ;
     RECT  20.7 84.299 21.402 84.569 ;
     RECT  22.176 84.451 22.446 84.569 ;
     RECT  36.504 83.669 37.278 84.569 ;
     RECT  20.7 84.569 21.366 84.605 ;
     RECT  22.428 84.569 22.446 84.605 ;
     RECT  25.92 84.407 26.55 84.605 ;
     RECT  36.504 84.569 36.522 84.605 ;
     RECT  28.62 84.335 29.697 84.613 ;
     RECT  22.5 84.613 22.518 84.713 ;
     RECT  26.676 84.613 26.694 84.749 ;
     RECT  24.012 84.407 24.894 84.839 ;
     RECT  17.568 84.443 18.897 84.875 ;
     RECT  21.168 84.605 21.366 84.875 ;
     RECT  27.936 84.613 29.697 84.875 ;
     RECT  24.012 84.839 24.297 84.893 ;
     RECT  21.168 84.875 21.33 84.947 ;
     RECT  27.936 84.875 27.954 84.983 ;
     RECT  21.168 84.947 21.186 85.019 ;
     RECT  17.64 84.875 17.802 85.379 ;
     RECT  17.64 85.379 17.658 85.415 ;
     RECT  28.8 84.875 29.697 85.415 ;
     RECT  28.872 85.415 29.697 85.685 ;
     RECT  66.42 113.515 66.438 113.729 ;
     RECT  65.304 74.039 65.322 113.909 ;
     RECT  67.215 74.075 67.497 115.123 ;
     RECT  67.215 115.123 68.094 115.591 ;
     RECT  68.94 77.935 69.39 115.591 ;
     RECT  67.215 115.591 69.39 115.655 ;
     RECT  68.256 115.655 69.39 116.333 ;
     RECT  2.415 82.175 2.697 117.467 ;
     RECT  7.815 82.985 8.097 117.467 ;
     RECT  13.215 84.299 13.497 117.467 ;
     RECT  18.615 84.875 18.897 117.467 ;
     RECT  24.015 84.893 24.297 117.467 ;
     RECT  29.415 85.685 29.697 117.467 ;
     RECT  34.815 84.317 35.097 117.467 ;
     RECT  40.215 84.221 40.497 117.467 ;
     RECT  45.615 79.979 45.897 117.467 ;
     RECT  51.015 75.659 51.297 117.467 ;
     RECT  56.415 70.907 56.697 117.467 ;
     RECT  61.815 74.039 62.097 117.467 ;
     RECT  67.215 115.655 67.497 117.467 ;
     RECT  72.615 72.995 72.897 117.467 ;
     RECT  78.015 70.541 78.297 117.467 ;
     RECT  83.415 67.325 83.697 117.467 ;
     RECT  88.815 69.989 89.097 117.467 ;
     RECT  94.215 75.425 94.497 117.467 ;
     RECT  99.615 76.397 99.897 117.467 ;
     RECT  105.015 74.849 105.297 117.467 ;
     RECT  110.415 75.695 110.697 117.467 ;
     RECT  115.815 75.227 116.097 117.467 ;
     RECT  2.415 117.467 2.505 117.737 ;
     RECT  7.815 117.467 7.905 117.737 ;
     RECT  13.215 117.467 13.305 117.737 ;
     RECT  18.615 117.467 18.705 117.737 ;
     RECT  24.015 117.467 24.105 117.737 ;
     RECT  29.415 117.467 29.505 117.737 ;
     RECT  34.815 117.467 34.905 117.737 ;
     RECT  40.215 117.467 40.305 117.737 ;
     RECT  45.615 117.467 45.705 117.737 ;
     RECT  51.015 117.467 51.105 117.737 ;
     RECT  56.415 117.467 56.505 117.737 ;
     RECT  61.815 117.467 61.905 117.737 ;
     RECT  67.215 117.467 67.305 117.737 ;
     RECT  72.615 117.467 72.705 117.737 ;
     RECT  78.015 117.467 78.105 117.737 ;
     RECT  83.415 117.467 83.505 117.737 ;
     RECT  88.815 117.467 88.905 117.737 ;
     RECT  94.215 117.467 94.305 117.737 ;
     RECT  99.615 117.467 99.705 117.737 ;
     RECT  105.015 117.467 105.105 117.737 ;
     RECT  110.415 117.467 110.505 117.737 ;
     RECT  115.815 117.467 115.905 117.737 ;
     RECT  68.94 116.333 69.39 119.165 ;
     RECT  69.3 119.165 69.39 119.837 ;
     RECT  69.3 119.837 69.318 119.885 ;
    LAYER M4 ;
     RECT  0.06 60.912 0.133 69.192 ;
     RECT  0.037 58.704 0.179 58.728 ;
     RECT  0.085 51.408 2.408 51.432 ;
     RECT  0.037 52.464 2.408 52.488 ;
     RECT  0.133 60.912 2.408 69.288 ;
     RECT  2.408 2.148 2.512 117.732 ;
     RECT  2.512 2.418 2.704 117.462 ;
     RECT  2.704 63.792 2.765 65.448 ;
     RECT  2.765 63.792 2.801 65.208 ;
     RECT  2.704 66.48 2.819 69.288 ;
     RECT  2.801 63.792 2.837 64.968 ;
     RECT  2.819 66.864 3.341 69.288 ;
     RECT  2.837 63.792 3.413 64.632 ;
     RECT  3.341 66.864 4.061 68.712 ;
     RECT  3.413 64.032 4.097 64.056 ;
     RECT  2.704 52.464 4.277 52.488 ;
     RECT  4.309 77.568 4.481 77.592 ;
     RECT  4.412 57.456 4.499 57.48 ;
     RECT  2.704 61.488 4.529 61.512 ;
     RECT  4.061 66.864 4.529 68.136 ;
     RECT  4.345 82.8 4.547 82.824 ;
     RECT  4.481 77.568 4.565 77.976 ;
     RECT  2.704 51.408 4.637 51.432 ;
     RECT  4.885 78.96 4.969 78.984 ;
     RECT  4.529 67.008 5.209 68.136 ;
     RECT  5.209 67.008 5.213 68.376 ;
     RECT  5.18 55.536 5.267 55.56 ;
     RECT  5.213 68.352 5.699 68.376 ;
     RECT  5.317 72.528 5.699 72.552 ;
     RECT  5.317 74.64 5.699 74.664 ;
     RECT  4.565 77.568 5.753 77.592 ;
     RECT  5.713 61.44 5.825 61.464 ;
     RECT  6.044 63.792 6.131 63.816 ;
     RECT  6.044 74.88 6.131 74.904 ;
     RECT  5.213 67.008 6.221 67.272 ;
     RECT  6.085 82.032 6.221 82.056 ;
     RECT  6.14 52.176 6.227 52.2 ;
     RECT  6.721 58.08 6.805 58.104 ;
     RECT  6.221 67.008 7.801 67.032 ;
     RECT  7.045 52.464 7.808 52.488 ;
     RECT  7.429 58.128 7.808 58.152 ;
     RECT  7.292 65.328 7.808 65.352 ;
     RECT  7.801 67.008 7.808 67.32 ;
     RECT  7.333 68.928 7.808 68.952 ;
     RECT  6.829 71.472 7.808 71.496 ;
     RECT  7.381 72.96 7.808 72.984 ;
     RECT  7.141 77.808 7.808 77.832 ;
     RECT  7.237 79.248 7.808 79.272 ;
     RECT  7.669 82.704 7.808 82.728 ;
     RECT  7.808 2.148 7.912 117.732 ;
     RECT  7.912 2.418 8.104 117.462 ;
     RECT  8.104 54.576 8.243 54.6 ;
     RECT  8.104 67.296 8.243 67.704 ;
     RECT  8.104 61.2 8.332 61.224 ;
     RECT  8.104 74.88 8.381 74.904 ;
     RECT  8.104 72.96 8.813 72.984 ;
     RECT  8.104 76.704 8.957 77.016 ;
     RECT  8.957 76.704 8.963 76.728 ;
     RECT  9.109 63.216 9.389 63.24 ;
     RECT  9.109 51.6 9.457 51.624 ;
     RECT  9.457 51.6 9.497 51.864 ;
     RECT  9.5 82.704 9.587 82.728 ;
     RECT  8.104 58.128 9.605 58.152 ;
     RECT  9.497 51.84 9.637 51.864 ;
     RECT  8.243 67.68 9.713 67.704 ;
     RECT  9.74 56.4 9.827 56.424 ;
     RECT  9.884 66.624 9.971 66.648 ;
     RECT  9.241 76.368 10.253 76.392 ;
     RECT  10.141 69.504 10.259 69.528 ;
     RECT  9.637 51.84 10.361 52.248 ;
     RECT  10.753 64.368 11.005 64.392 ;
     RECT  11.005 63.888 11.189 64.392 ;
     RECT  11.221 53.088 11.305 53.112 ;
     RECT  11.276 56.4 11.363 56.424 ;
     RECT  11.285 82.656 11.369 82.68 ;
     RECT  11.189 63.888 11.411 63.912 ;
     RECT  10.321 69.648 11.413 69.864 ;
     RECT  11.468 60.864 11.555 60.888 ;
     RECT  11.413 69.6 11.725 69.864 ;
     RECT  11.701 48.96 11.788 48.984 ;
     RECT  11.725 69.6 11.873 70.008 ;
     RECT  11.761 72.624 11.987 72.648 ;
     RECT  12.697 47.808 13.208 47.832 ;
     RECT  10.361 51.84 13.208 51.864 ;
     RECT  12.956 57.024 13.208 57.048 ;
     RECT  13.093 58.656 13.208 58.68 ;
     RECT  12.524 61.776 13.208 61.8 ;
     RECT  12.769 67.296 13.208 67.32 ;
     RECT  11.873 69.696 13.208 70.008 ;
     RECT  11.989 76.464 13.208 76.488 ;
     RECT  13.208 2.148 13.312 117.732 ;
     RECT  13.312 2.418 13.504 117.462 ;
     RECT  13.504 58.704 13.637 58.728 ;
     RECT  13.504 54.576 13.9 54.6 ;
     RECT  13.504 51.312 14.141 51.912 ;
     RECT  14.141 51.312 14.243 51.336 ;
     RECT  13.504 67.296 14.291 67.32 ;
     RECT  13.504 59.856 14.321 59.88 ;
     RECT  13.504 69.744 14.485 69.864 ;
     RECT  14.485 63.792 14.572 63.816 ;
     RECT  14.725 66.528 14.741 66.552 ;
     RECT  13.504 79.296 14.789 79.32 ;
     RECT  14.485 69.744 14.819 70.008 ;
     RECT  14.741 66.432 14.825 66.552 ;
     RECT  14.821 81.744 14.905 81.864 ;
     RECT  14.905 81.744 14.963 81.768 ;
     RECT  14.819 69.744 15.437 69.864 ;
     RECT  15.397 65.664 15.653 65.784 ;
     RECT  16.021 47.856 16.108 47.88 ;
     RECT  16.364 81.84 16.451 81.864 ;
     RECT  16.405 64.08 16.492 64.104 ;
     RECT  15.973 50.688 16.547 50.712 ;
     RECT  16.549 76.896 16.633 76.92 ;
     RECT  16.597 82.896 16.684 82.92 ;
     RECT  16.549 73.488 16.805 73.512 ;
     RECT  16.549 52.512 16.913 52.536 ;
     RECT  17.077 66.864 17.341 66.888 ;
     RECT  15.437 69.84 17.377 69.864 ;
     RECT  17.477 46.704 17.561 46.728 ;
     RECT  17.377 69.84 17.605 70.008 ;
     RECT  17.233 74.016 17.633 74.04 ;
     RECT  17.737 63.936 18.313 63.96 ;
     RECT  18.313 63.888 18.469 63.96 ;
     RECT  17.605 69.84 18.529 70.056 ;
     RECT  18.469 63.888 18.608 64.104 ;
     RECT  17.341 66.864 18.608 67.128 ;
     RECT  18.529 69.792 18.608 70.056 ;
     RECT  17.521 76.512 18.608 76.536 ;
     RECT  18.449 80.256 18.608 80.28 ;
     RECT  17.161 83.616 18.608 83.64 ;
     RECT  17.605 85.344 18.608 85.368 ;
     RECT  18.608 2.148 18.712 117.732 ;
     RECT  18.712 2.418 18.904 117.462 ;
     RECT  18.904 69.744 19.145 70.008 ;
     RECT  18.904 72.96 19.405 72.984 ;
     RECT  18.904 56.016 19.757 56.04 ;
     RECT  19.145 69.84 19.793 70.008 ;
     RECT  20.113 78 20.197 78.024 ;
     RECT  20.204 80.784 20.291 80.808 ;
     RECT  20.533 84.576 20.617 84.6 ;
     RECT  20.617 83.904 20.729 84.6 ;
     RECT  20.761 67.968 21.089 67.992 ;
     RECT  21.109 64.416 21.196 64.44 ;
     RECT  21.253 50.976 21.377 51.336 ;
     RECT  21.377 50.976 21.395 51.048 ;
     RECT  20.729 83.904 21.449 83.928 ;
     RECT  19.793 69.84 21.517 69.864 ;
     RECT  21.517 69.84 21.637 70.392 ;
     RECT  21.637 47.76 21.685 47.784 ;
     RECT  21.685 47.664 21.724 47.784 ;
     RECT  21.637 69.84 21.724 70.68 ;
     RECT  21.395 50.976 21.744 51 ;
     RECT  21.724 47.664 21.772 47.688 ;
     RECT  21.661 74.256 21.841 74.28 ;
     RECT  21.841 74.256 21.953 74.616 ;
     RECT  21.637 80.784 22.133 80.808 ;
     RECT  21.953 74.544 22.211 74.616 ;
     RECT  22.201 62.016 22.633 62.04 ;
     RECT  21.724 69.84 22.777 70.392 ;
     RECT  22.777 69.84 22.789 70.584 ;
     RECT  22.633 61.584 22.853 62.04 ;
     RECT  22.211 74.544 22.853 74.568 ;
     RECT  22.789 69.84 22.876 70.728 ;
     RECT  22.993 50.592 23.42 50.616 ;
     RECT  23.42 50.304 24.008 50.616 ;
     RECT  23.281 56.496 24.008 56.52 ;
     RECT  23.569 60.672 24.008 60.936 ;
     RECT  22.853 61.968 24.008 62.04 ;
     RECT  22.921 63.312 24.008 63.336 ;
     RECT  22.876 69.84 24.008 70.584 ;
     RECT  23.713 74.592 24.008 74.616 ;
     RECT  24.001 84.864 24.008 84.888 ;
     RECT  24.008 2.148 24.112 117.732 ;
     RECT  24.112 2.418 24.304 117.462 ;
     RECT  24.304 74.304 24.329 74.616 ;
     RECT  24.329 74.304 24.419 74.376 ;
     RECT  24.304 84.864 24.419 84.888 ;
     RECT  24.419 74.304 24.473 74.328 ;
     RECT  24.304 65.904 24.803 65.928 ;
     RECT  24.304 68.928 24.803 69.864 ;
     RECT  24.304 64.368 25.229 64.392 ;
     RECT  25.292 83.472 25.379 83.496 ;
     RECT  24.304 61.488 25.667 61.512 ;
     RECT  25.909 67.68 25.964 67.704 ;
     RECT  25.964 67.68 26.021 67.8 ;
     RECT  26.005 64.272 26.092 64.296 ;
     RECT  24.304 55.008 26.093 55.032 ;
     RECT  25.669 71.856 26.129 71.88 ;
     RECT  25.801 48.384 26.195 48.408 ;
     RECT  26.108 50.976 26.195 51 ;
     RECT  25.801 77.52 26.195 77.544 ;
     RECT  26.021 67.776 26.345 67.8 ;
     RECT  26.377 57.072 26.669 57.096 ;
     RECT  26.773 52.512 26.885 52.536 ;
     RECT  26.773 68.016 27.029 68.04 ;
     RECT  24.803 69.84 27.745 69.864 ;
     RECT  27.745 69.216 27.853 69.864 ;
     RECT  27.877 75.936 27.964 75.96 ;
     RECT  27.925 61.872 28.009 61.896 ;
     RECT  27.853 69.12 28.604 69.864 ;
     RECT  29.041 79.248 29.269 79.272 ;
     RECT  28.604 68.256 29.408 69.864 ;
     RECT  28.885 78.048 29.408 78.072 ;
     RECT  29.269 79.248 29.408 79.752 ;
     RECT  29.029 82.032 29.408 82.056 ;
     RECT  28.837 85.632 29.408 85.656 ;
     RECT  29.408 2.148 29.512 117.732 ;
     RECT  29.512 2.418 29.704 117.462 ;
     RECT  29.704 63.552 29.891 63.576 ;
     RECT  29.704 68.976 30.413 70.2 ;
     RECT  29.704 65.184 30.419 65.256 ;
     RECT  29.704 61.968 30.449 61.992 ;
     RECT  30.419 65.232 30.629 65.256 ;
     RECT  29.704 79.488 30.809 79.512 ;
     RECT  30.413 68.976 30.841 69.864 ;
     RECT  29.704 75.984 30.844 76.008 ;
     RECT  29.704 47.808 30.953 47.832 ;
     RECT  30.913 75.744 31.133 75.768 ;
     RECT  30.841 68.928 31.418 69.864 ;
     RECT  31.418 68.928 31.601 69.816 ;
     RECT  31.621 73.968 31.708 73.992 ;
     RECT  31.601 68.976 31.889 69.816 ;
     RECT  31.957 84.048 32.044 84.072 ;
     RECT  33.073 73.488 33.635 73.512 ;
     RECT  33.613 79.824 33.697 79.848 ;
     RECT  34.297 68.16 34.333 68.184 ;
     RECT  33.613 57.936 34.808 57.96 ;
     RECT  33.836 66.912 34.808 66.936 ;
     RECT  34.333 67.92 34.808 68.184 ;
     RECT  31.889 69.792 34.808 69.816 ;
     RECT  33.829 73.536 34.808 73.56 ;
     RECT  33.757 75.408 34.808 75.432 ;
     RECT  34.261 84.192 34.808 84.216 ;
     RECT  34.808 2.148 34.912 117.732 ;
     RECT  34.912 2.418 35.104 117.462 ;
     RECT  35.104 68.208 35.219 68.232 ;
     RECT  35.104 76.848 35.219 76.872 ;
     RECT  35.104 53.52 35.417 53.544 ;
     RECT  35.104 69.792 35.459 70.44 ;
     RECT  35.104 84.288 35.533 84.312 ;
     RECT  36.449 84.576 36.533 84.6 ;
     RECT  36.781 64.56 36.929 64.584 ;
     RECT  36.956 84.192 37.043 84.216 ;
     RECT  37.045 73.488 37.237 73.512 ;
     RECT  37.237 73.488 37.325 73.992 ;
     RECT  37.325 73.488 38.761 73.512 ;
     RECT  38.761 73.488 38.819 73.752 ;
     RECT  38.819 73.728 38.845 73.752 ;
     RECT  38.509 60.912 38.909 60.936 ;
     RECT  38.257 67.968 39.161 67.992 ;
     RECT  39.404 75.408 39.445 75.432 ;
     RECT  39.337 46.656 40.208 46.68 ;
     RECT  39.589 49.152 40.208 49.176 ;
     RECT  39.877 51.36 40.208 51.384 ;
     RECT  35.459 69.792 40.208 69.816 ;
     RECT  39.445 75.216 40.208 75.432 ;
     RECT  38.761 78.912 40.208 78.936 ;
     RECT  39.5 82.032 40.208 82.056 ;
     RECT  40.208 2.148 40.312 117.732 ;
     RECT  40.312 2.418 40.504 117.462 ;
     RECT  40.504 84.192 40.643 84.216 ;
     RECT  40.504 75.168 40.673 75.192 ;
     RECT  40.504 51.36 40.817 51.768 ;
     RECT  40.504 46.752 41.573 46.776 ;
     RECT  41.713 54.336 42.179 54.36 ;
     RECT  42.188 71.856 42.275 71.88 ;
     RECT  42.421 82.944 42.509 82.968 ;
     RECT  40.817 51.36 42.757 51.384 ;
     RECT  42.757 79.152 42.977 79.176 ;
     RECT  42.757 51.36 43.193 51.672 ;
     RECT  43.189 57.6 43.331 58.104 ;
     RECT  43.261 54.624 43.585 54.648 ;
     RECT  43.585 54.624 43.733 54.696 ;
     RECT  43.868 52.416 43.955 52.44 ;
     RECT  44.089 56.448 44.173 56.472 ;
     RECT  44.149 45.168 44.237 45.192 ;
     RECT  43.909 71.808 44.309 71.832 ;
     RECT  44.017 46.224 44.453 46.248 ;
     RECT  43.331 57.6 44.453 57.624 ;
     RECT  44.413 52.992 44.497 53.016 ;
     RECT  43.733 54.624 44.869 54.648 ;
     RECT  43.193 51.36 44.917 51.384 ;
     RECT  45.157 49.344 45.608 49.368 ;
     RECT  44.917 51.36 45.608 51.624 ;
     RECT  44.869 54.576 45.608 54.648 ;
     RECT  40.504 69.792 45.608 69.816 ;
     RECT  45.356 75.072 45.608 75.096 ;
     RECT  45.421 78.144 45.608 78.168 ;
     RECT  45.608 2.148 45.712 117.732 ;
     RECT  45.712 2.418 45.904 117.462 ;
     RECT  45.904 45.168 46.019 45.192 ;
     RECT  45.904 56.688 46.019 56.712 ;
     RECT  45.904 78.144 46.037 78.408 ;
     RECT  45.904 58.128 46.109 58.152 ;
     RECT  46.037 78.144 46.145 78.168 ;
     RECT  45.904 79.92 46.259 79.944 ;
     RECT  45.904 72.288 46.657 72.312 ;
     RECT  45.904 74.928 46.901 74.952 ;
     RECT  47.041 61.728 47.261 61.752 ;
     RECT  47.185 63.168 47.315 63.192 ;
     RECT  47.317 53.04 47.585 53.064 ;
     RECT  47.749 65.376 47.836 65.4 ;
     RECT  47.689 71.904 47.909 71.928 ;
     RECT  47.948 81.6 48.035 81.624 ;
     RECT  47.893 54.768 48.053 54.792 ;
     RECT  48.301 48.48 48.467 48.504 ;
     RECT  48.373 57.84 48.467 57.864 ;
     RECT  48.733 44.976 48.995 45 ;
     RECT  48.908 78.048 48.995 78.072 ;
     RECT  49.057 51.84 49.313 51.864 ;
     RECT  45.904 69.792 49.561 69.816 ;
     RECT  49.525 63.312 49.669 63.336 ;
     RECT  49.561 68.832 49.817 69.816 ;
     RECT  49.669 63.264 50.204 63.336 ;
     RECT  50.101 60.096 50.341 60.12 ;
     RECT  50.204 63.264 50.533 63.528 ;
     RECT  50.533 74.88 50.569 74.904 ;
     RECT  50.533 51.984 50.749 52.008 ;
     RECT  50.569 74.64 50.821 74.904 ;
     RECT  50.713 47.424 50.869 47.448 ;
     RECT  50.869 46.896 51.008 47.448 ;
     RECT  50.749 51.936 51.008 52.008 ;
     RECT  50.461 56.256 51.008 56.28 ;
     RECT  50.341 60.096 51.008 60.984 ;
     RECT  50.533 63.264 51.008 63.816 ;
     RECT  49.817 69.792 51.008 69.816 ;
     RECT  50.849 71.76 51.008 71.784 ;
     RECT  50.821 73.536 51.008 74.904 ;
     RECT  51.008 2.148 51.112 117.732 ;
     RECT  51.112 2.418 51.304 117.462 ;
     RECT  51.304 51.936 51.401 52.008 ;
     RECT  51.304 63.264 51.437 63.816 ;
     RECT  51.401 51.984 51.581 52.008 ;
     RECT  51.304 47.424 51.833 47.448 ;
     RECT  51.304 56.064 52.307 56.088 ;
     RECT  51.304 59.808 52.307 59.832 ;
     RECT  51.437 63.792 52.333 63.816 ;
     RECT  51.304 74.88 52.396 74.904 ;
     RECT  52.297 52.032 52.451 52.056 ;
     RECT  52.333 63.792 52.481 63.912 ;
     RECT  52.481 63.792 52.661 63.816 ;
     RECT  51.304 69.792 52.837 70.632 ;
     RECT  52.837 68.928 52.924 70.632 ;
     RECT  53.372 49.872 53.459 49.896 ;
     RECT  53.269 63.312 53.669 63.336 ;
     RECT  53.557 53.088 53.957 53.112 ;
     RECT  53.989 72.432 54.076 72.456 ;
     RECT  54.284 67.2 54.371 67.224 ;
     RECT  54.133 57.264 54.389 57.288 ;
     RECT  54.349 47.712 54.677 47.736 ;
     RECT  52.924 69.792 54.889 70.632 ;
     RECT  54.709 60 55.145 60.024 ;
     RECT  55.093 46.8 55.18 46.824 ;
     RECT  55.501 63.792 55.933 63.816 ;
     RECT  55.933 63.792 56.077 64.392 ;
     RECT  56.077 63.792 56.257 64.44 ;
     RECT  56.005 49.152 56.408 49.176 ;
     RECT  56.257 63.792 56.408 64.632 ;
     RECT  56.053 65.904 56.408 65.928 ;
     RECT  54.889 69.216 56.408 70.632 ;
     RECT  56.408 2.148 56.512 117.732 ;
     RECT  56.512 2.418 56.704 117.462 ;
     RECT  56.704 47.808 57.521 48.12 ;
     RECT  57.521 48.096 57.532 48.12 ;
     RECT  58.46 46.896 58.547 46.92 ;
     RECT  58.693 46.944 59.075 47.832 ;
     RECT  59.075 46.944 59.357 46.968 ;
     RECT  60.353 73.584 60.437 73.608 ;
     RECT  56.704 69.792 61.808 70.632 ;
     RECT  61.649 72.288 61.808 72.312 ;
     RECT  61.808 2.148 61.912 117.732 ;
     RECT  61.912 2.418 62.104 117.462 ;
     RECT  62.104 69.792 62.525 70.968 ;
     RECT  62.525 70.944 62.569 70.968 ;
     RECT  63.745 71.136 63.932 71.16 ;
     RECT  63.932 71.088 64.019 71.16 ;
     RECT  64.885 73.968 64.972 73.992 ;
     RECT  64.019 71.136 65.189 71.16 ;
     RECT  62.525 69.792 67.208 69.816 ;
     RECT  66.409 113.52 67.208 113.544 ;
     RECT  67.208 2.148 67.312 117.732 ;
     RECT  67.312 2.418 67.504 117.462 ;
     RECT  67.504 69.792 67.619 70.584 ;
     RECT  67.619 69.792 68.141 69.816 ;
     RECT  67.504 74.352 68.533 74.376 ;
     RECT  67.504 72.24 68.965 72.264 ;
     RECT  68.927 119.136 69.033 119.16 ;
     RECT  68.965 71.856 69.077 72.264 ;
     RECT  67.504 116.304 69.203 116.328 ;
     RECT  69.245 119.808 69.329 119.88 ;
     RECT  69.329 119.808 69.401 119.832 ;
     RECT  69.433 69.696 69.539 69.72 ;
     RECT  70.076 47.04 70.163 47.064 ;
     RECT  70.22 43.824 70.307 43.848 ;
     RECT  71.629 23.088 72.608 23.112 ;
     RECT  69.077 72.24 72.608 72.264 ;
     RECT  68.533 74.352 72.608 74.424 ;
     RECT  72.608 2.148 72.712 117.732 ;
     RECT  72.712 2.418 72.904 117.462 ;
     RECT  72.904 15.312 73.523 15.336 ;
     RECT  72.904 16.512 73.619 16.536 ;
     RECT  74.012 12.528 74.099 12.552 ;
     RECT  74.293 18.432 74.675 18.456 ;
     RECT  74.828 37.44 74.915 37.464 ;
     RECT  75.157 23.04 75.244 23.064 ;
     RECT  75.5 28.272 75.587 28.296 ;
     RECT  75.517 32.544 75.601 32.568 ;
     RECT  75.301 34.272 75.827 34.296 ;
     RECT  75.769 25.728 75.853 25.752 ;
     RECT  75.788 24.048 75.875 24.072 ;
     RECT  75.625 55.728 75.884 55.752 ;
     RECT  75.836 12.912 75.923 12.936 ;
     RECT  75.884 55.584 75.971 55.752 ;
     RECT  75.971 55.728 75.989 55.752 ;
     RECT  75.193 0.048 76.057 0.072 ;
     RECT  75.98 19.68 76.067 19.704 ;
     RECT  76.021 27.072 76.403 27.096 ;
     RECT  76.057 51.216 76.421 51.24 ;
     RECT  76.508 63.504 76.595 63.528 ;
     RECT  76.741 16.512 76.828 16.536 ;
     RECT  76.877 60.912 76.961 60.936 ;
     RECT  77.845 16.512 78.008 16.536 ;
     RECT  77.653 30.96 78.008 30.984 ;
     RECT  72.904 72.24 78.008 72.264 ;
     RECT  72.904 74.352 78.008 74.424 ;
     RECT  78.008 2.148 78.112 117.732 ;
     RECT  78.112 2.418 78.304 117.462 ;
     RECT  78.304 66.432 78.419 66.456 ;
     RECT  78.304 26.784 78.509 27.096 ;
     RECT  78.304 33.936 78.604 33.96 ;
     RECT  78.304 35.328 78.611 35.448 ;
     RECT  78.304 9.264 78.659 9.288 ;
     RECT  78.304 58.944 78.659 58.968 ;
     RECT  78.304 60.816 78.659 61.032 ;
     RECT  78.304 31.248 78.689 31.272 ;
     RECT  78.611 35.328 78.707 35.352 ;
     RECT  78.659 61.008 78.707 61.032 ;
     RECT  76.057 0.048 79.117 0.12 ;
     RECT  78.793 1.104 79.117 1.128 ;
     RECT  78.304 37.728 79.193 37.752 ;
     RECT  78.304 21.12 79.229 21.144 ;
     RECT  78.304 13.488 79.235 13.512 ;
     RECT  78.304 23.952 79.237 23.976 ;
     RECT  78.304 11.616 79.331 11.64 ;
     RECT  78.509 26.784 79.409 26.952 ;
     RECT  78.304 70.512 79.441 70.536 ;
     RECT  79.409 26.832 79.481 26.952 ;
     RECT  79.441 21.648 79.525 21.672 ;
     RECT  79.477 7.2 79.541 7.224 ;
     RECT  79.441 22.8 79.553 22.824 ;
     RECT  79.525 55.68 79.612 55.704 ;
     RECT  79.541 7.2 79.625 7.368 ;
     RECT  79.481 26.928 79.625 26.952 ;
     RECT  79.405 31.296 79.811 31.32 ;
     RECT  79.793 34.944 79.837 34.968 ;
     RECT  79.837 34.848 79.877 34.968 ;
     RECT  79.625 7.2 79.945 7.224 ;
     RECT  79.877 34.848 79.955 34.872 ;
     RECT  79.868 60.96 79.955 60.984 ;
     RECT  79.945 6.864 80.057 7.224 ;
     RECT  80.057 7.2 80.093 7.224 ;
     RECT  80.012 14.784 80.099 14.808 ;
     RECT  80.389 27.984 80.633 28.008 ;
     RECT  80.629 16.896 80.665 16.92 ;
     RECT  80.593 10.752 80.677 10.776 ;
     RECT  80.665 16.896 80.716 17.64 ;
     RECT  80.716 16.992 80.771 17.64 ;
     RECT  80.869 10.32 80.956 10.344 ;
     RECT  80.917 58.656 81.004 58.68 ;
     RECT  79.117 0.048 81.107 1.128 ;
     RECT  81.025 2.88 81.385 2.904 ;
     RECT  81.413 8.496 81.497 8.52 ;
     RECT  81.413 34.896 81.497 34.92 ;
     RECT  81.5 1.68 81.587 1.704 ;
     RECT  81.596 11.616 81.683 11.64 ;
     RECT  81.385 2.88 81.829 2.952 ;
     RECT  81.836 29.424 81.889 29.448 ;
     RECT  81.889 29.232 81.923 29.448 ;
     RECT  81.829 2.88 81.925 3.432 ;
     RECT  81.877 32.16 81.964 32.184 ;
     RECT  81.107 0.048 82.067 0.552 ;
     RECT  80.771 17.616 82.069 17.64 ;
     RECT  81.997 66.72 82.081 66.744 ;
     RECT  82.069 17.616 82.109 18.168 ;
     RECT  81.961 35.184 82.109 35.208 ;
     RECT  81.923 29.232 82.145 29.256 ;
     RECT  82.067 0.048 82.163 0.504 ;
     RECT  82.105 38.736 82.189 38.76 ;
     RECT  82.117 22.704 82.204 22.728 ;
     RECT  81.889 11.472 82.253 11.496 ;
     RECT  82.069 46.8 82.565 46.824 ;
     RECT  81.925 2.88 83.113 3.48 ;
     RECT  82.501 14.832 83.221 14.856 ;
     RECT  82.163 0.048 83.249 0.216 ;
     RECT  82.609 1.728 83.249 1.752 ;
     RECT  83.221 11.568 83.293 11.592 ;
     RECT  83.249 0.048 83.333 1.752 ;
     RECT  83.333 1.2 83.365 1.752 ;
     RECT  83.113 2.88 83.365 4.008 ;
     RECT  83.365 1.2 83.408 4.008 ;
     RECT  82.825 7.392 83.408 7.416 ;
     RECT  83.221 8.496 83.408 8.52 ;
     RECT  83.293 11.472 83.408 11.592 ;
     RECT  83.221 14.784 83.408 14.856 ;
     RECT  82.109 18.144 83.408 18.168 ;
     RECT  83.113 23.376 83.408 23.4 ;
     RECT  82.213 25.728 83.408 25.752 ;
     RECT  82.693 31.92 83.408 31.944 ;
     RECT  82.565 46.8 83.408 47.352 ;
     RECT  83.269 58.512 83.408 58.536 ;
     RECT  83.269 64.176 83.408 64.2 ;
     RECT  79.441 70.368 83.408 70.536 ;
     RECT  78.304 72.24 83.408 72.264 ;
     RECT  78.304 74.352 83.408 74.424 ;
     RECT  83.408 1.2 83.512 117.732 ;
     RECT  83.512 1.2 83.585 117.462 ;
     RECT  83.585 2.016 83.603 117.462 ;
     RECT  83.603 2.256 83.704 117.462 ;
     RECT  83.704 8.256 83.729 8.28 ;
     RECT  83.704 2.256 83.765 3.048 ;
     RECT  83.765 2.304 83.795 3.048 ;
     RECT  83.333 0.048 83.891 0.216 ;
     RECT  83.795 3.024 83.909 3.048 ;
     RECT  83.891 0.048 83.981 0.168 ;
     RECT  83.981 0.096 84.025 0.168 ;
     RECT  84.025 0.096 84.097 0.12 ;
     RECT  83.704 21.408 84.125 22.488 ;
     RECT  84.125 21.408 84.131 22.152 ;
     RECT  83.704 61.776 84.557 61.8 ;
     RECT  83.704 58.128 84.652 58.152 ;
     RECT  83.704 26.688 84.707 26.712 ;
     RECT  83.704 42.432 84.773 42.456 ;
     RECT  83.704 18.192 84.892 18.216 ;
     RECT  84.805 33.024 84.892 33.048 ;
     RECT  83.704 11.28 84.947 12.024 ;
     RECT  84.913 30.288 85.093 30.312 ;
     RECT  84.947 11.28 85.169 11.304 ;
     RECT  85.093 29.52 85.189 30.312 ;
     RECT  85.189 29.184 85.235 30.312 ;
     RECT  85.235 29.184 85.277 29.544 ;
     RECT  85.196 38.688 85.283 38.712 ;
     RECT  85.196 42.384 85.283 42.408 ;
     RECT  85.277 29.52 85.349 29.544 ;
     RECT  85.525 37.2 85.612 37.224 ;
     RECT  85.621 24.912 85.709 24.936 ;
     RECT  85.765 65.52 85.853 65.544 ;
     RECT  85.82 21.888 85.907 21.912 ;
     RECT  85.964 7.776 86.051 7.8 ;
     RECT  83.704 70.368 86.425 70.536 ;
     RECT  86.425 70.176 86.627 70.536 ;
     RECT  87.061 68.352 87.149 68.376 ;
     RECT  87.253 62.64 87.337 62.664 ;
     RECT  87.205 58.224 87.437 58.248 ;
     RECT  88.225 58.512 88.261 58.536 ;
     RECT  88.261 58.512 88.808 58.632 ;
     RECT  87.781 63.84 88.808 63.864 ;
     RECT  88.316 66.432 88.808 66.456 ;
     RECT  86.627 70.368 88.808 70.536 ;
     RECT  83.704 72.24 88.808 72.264 ;
     RECT  83.704 74.352 88.808 74.424 ;
     RECT  88.808 2.148 88.912 117.732 ;
     RECT  88.912 2.418 89.104 117.462 ;
     RECT  89.104 69.936 89.309 70.536 ;
     RECT  89.104 67.728 90.313 67.8 ;
     RECT  90.313 67.488 90.353 67.8 ;
     RECT  90.353 67.488 90.673 67.56 ;
     RECT  89.309 70.368 92.012 70.536 ;
     RECT  92.012 70.368 92.099 71.064 ;
     RECT  89.104 74.352 92.3 74.424 ;
     RECT  92.3 74.016 92.387 74.424 ;
     RECT  92.099 70.368 93.125 70.728 ;
     RECT  90.673 67.296 93.197 67.56 ;
     RECT  92.387 74.352 93.553 74.424 ;
     RECT  93.733 66.144 94.208 66.168 ;
     RECT  93.197 67.296 94.208 67.32 ;
     RECT  93.125 70.368 94.208 70.536 ;
     RECT  89.104 72.24 94.208 72.264 ;
     RECT  93.553 74.352 94.208 74.76 ;
     RECT  94.208 2.148 94.312 117.732 ;
     RECT  94.312 2.418 94.504 117.462 ;
     RECT  94.504 70.368 95.219 71.112 ;
     RECT  94.504 74.352 95.564 74.424 ;
     RECT  95.564 74.016 95.651 74.424 ;
     RECT  96.86 64.896 96.947 64.92 ;
     RECT  96.893 75.888 96.977 75.912 ;
     RECT  94.504 72.24 97.477 72.264 ;
     RECT  97.477 72.24 97.661 72.456 ;
     RECT  95.219 70.368 98.377 70.536 ;
     RECT  97.661 72.24 98.593 72.264 ;
     RECT  98.089 68.928 98.627 68.952 ;
     RECT  98.521 64.896 98.629 64.92 ;
     RECT  98.593 72.144 98.633 72.264 ;
     RECT  98.629 64.608 99.608 64.92 ;
     RECT  94.504 67.248 99.608 67.272 ;
     RECT  98.377 70.032 99.608 70.536 ;
     RECT  98.633 72.144 99.608 72.168 ;
     RECT  95.651 74.352 99.608 74.424 ;
     RECT  98.924 76.32 99.608 76.344 ;
     RECT  99.608 2.148 99.712 117.732 ;
     RECT  99.712 2.418 99.904 117.462 ;
     RECT  99.904 67.296 100.019 67.704 ;
     RECT  99.904 69.84 100.019 70.536 ;
     RECT  99.904 72.144 100.289 72.456 ;
     RECT  99.904 75.888 100.403 76.392 ;
     RECT  100.403 75.888 100.541 76.104 ;
     RECT  100.541 76.08 100.649 76.104 ;
     RECT  100.289 72.144 100.721 72.264 ;
     RECT  100.94 65.088 101.027 65.112 ;
     RECT  101.933 79.248 101.948 79.272 ;
     RECT  101.948 79.248 102.017 79.992 ;
     RECT  102.017 79.968 102.035 79.992 ;
     RECT  102.133 68.592 102.22 68.616 ;
     RECT  100.019 67.44 102.557 67.464 ;
     RECT  103.157 79.776 103.241 79.8 ;
     RECT  99.904 74.352 103.34 74.424 ;
     RECT  103.34 74.352 103.427 74.904 ;
     RECT  103.165 76.176 103.427 76.2 ;
     RECT  100.019 70.368 103.484 70.536 ;
     RECT  103.484 70.368 103.571 71.112 ;
     RECT  102.445 64.992 103.717 65.016 ;
     RECT  100.721 72.24 103.772 72.264 ;
     RECT  103.772 72.144 103.859 72.264 ;
     RECT  103.717 64.608 105.008 65.016 ;
     RECT  103.571 70.368 105.008 70.536 ;
     RECT  103.859 72.24 105.008 72.264 ;
     RECT  103.427 74.352 105.008 74.424 ;
     RECT  105.008 2.148 105.112 117.732 ;
     RECT  105.112 2.418 105.304 117.462 ;
     RECT  105.304 68.112 106.019 68.136 ;
     RECT  105.304 72.24 106.508 72.264 ;
     RECT  105.304 74.352 106.513 74.424 ;
     RECT  106.508 72.24 106.595 72.984 ;
     RECT  106.513 74.352 106.697 75.192 ;
     RECT  107.036 65.712 107.123 65.736 ;
     RECT  105.304 70.368 107.461 70.536 ;
     RECT  107.461 70.368 107.548 71.112 ;
     RECT  108.181 68.88 108.268 68.904 ;
     RECT  107.548 70.368 108.853 70.536 ;
     RECT  108.86 65.712 108.947 65.736 ;
     RECT  109.093 75.504 109.18 75.528 ;
     RECT  106.595 72.24 109.388 72.264 ;
     RECT  106.697 74.352 110.069 74.424 ;
     RECT  108.853 69.456 110.245 70.536 ;
     RECT  110.245 68.88 110.293 70.536 ;
     RECT  110.293 68.784 110.408 70.536 ;
     RECT  109.388 72.24 110.408 72.984 ;
     RECT  110.069 74.064 110.408 74.424 ;
     RECT  110.408 2.148 110.512 117.732 ;
     RECT  110.512 2.418 110.704 117.462 ;
     RECT  110.704 72.096 111.395 72.264 ;
     RECT  110.704 65.712 111.733 65.736 ;
     RECT  111.733 65.52 111.779 65.736 ;
     RECT  111.779 65.52 112.277 65.544 ;
     RECT  112.549 68.352 112.636 68.376 ;
     RECT  110.704 74.352 112.981 74.424 ;
     RECT  112.981 74.352 113.068 74.664 ;
     RECT  113.173 69.168 113.26 69.192 ;
     RECT  111.395 72.24 113.413 72.264 ;
     RECT  113.413 71.808 113.609 72.264 ;
     RECT  113.609 72.24 115.297 72.264 ;
     RECT  110.704 70.368 115.585 70.536 ;
     RECT  113.068 74.352 115.585 74.424 ;
     RECT  115.585 70.368 115.808 70.872 ;
     RECT  115.297 72.144 115.808 72.264 ;
     RECT  115.585 74.304 115.808 74.424 ;
     RECT  115.808 2.148 115.912 117.732 ;
     RECT  115.912 2.418 116.104 117.462 ;
     RECT  116.104 70.368 116.162 74.472 ;
     RECT  116.162 70.416 117.421 74.472 ;
     RECT  117.421 70.32 119.797 74.472 ;
     RECT  119.797 70.32 119.964 74.568 ;
    LAYER M5 ;
     RECT  80.88 0.016 84.072 0.131 ;
     RECT  80.976 0.131 83.976 0.179 ;
     RECT  80.976 0.179 83.88 0.227 ;
     RECT  80.976 0.227 83.784 1.139 ;
     RECT  81.168 1.139 83.784 2.339 ;
     RECT  2.4 2.137 2.52 2.407 ;
     RECT  7.8 2.137 7.92 2.407 ;
     RECT  13.2 2.137 13.32 2.407 ;
     RECT  18.6 2.137 18.72 2.407 ;
     RECT  24 2.137 24.12 2.407 ;
     RECT  29.4 2.137 29.52 2.407 ;
     RECT  34.8 2.137 34.92 2.407 ;
     RECT  40.2 2.137 40.32 2.407 ;
     RECT  45.6 2.137 45.72 2.407 ;
     RECT  51 2.137 51.12 2.407 ;
     RECT  56.4 2.137 56.52 2.407 ;
     RECT  61.8 2.137 61.92 2.407 ;
     RECT  67.2 2.137 67.32 2.407 ;
     RECT  72.6 2.137 72.72 2.407 ;
     RECT  78 2.137 78.12 2.407 ;
     RECT  88.8 2.137 88.92 2.407 ;
     RECT  94.2 2.137 94.32 2.407 ;
     RECT  99.6 2.137 99.72 2.407 ;
     RECT  105 2.137 105.12 2.407 ;
     RECT  110.4 2.137 110.52 2.407 ;
     RECT  115.8 2.137 115.92 2.407 ;
     RECT  81.168 2.339 83.712 2.915 ;
     RECT  81.456 2.915 83.712 2.963 ;
     RECT  81.84 2.963 83.712 3.443 ;
     RECT  81.936 3.443 83.712 3.491 ;
     RECT  79.584 7.333 79.608 7.417 ;
     RECT  86.016 7.765 86.04 7.851 ;
     RECT  81.456 8.485 81.48 8.747 ;
     RECT  78 2.407 78.312 9.253 ;
     RECT  78 9.253 78.648 9.337 ;
     RECT  82.704 3.491 83.712 10.549 ;
     RECT  80.88 10.293 80.904 10.603 ;
     RECT  80.64 10.741 80.664 10.825 ;
     RECT  82.704 10.549 84.648 11.269 ;
     RECT  82.704 11.269 84.936 11.315 ;
     RECT  79.296 11.573 79.32 11.661 ;
     RECT  81.648 11.573 81.672 11.661 ;
     RECT  84.912 11.315 84.936 12.035 ;
     RECT  74.064 12.517 74.088 12.843 ;
     RECT  78 9.337 78.312 13.045 ;
     RECT  75.888 12.789 75.912 13.099 ;
     RECT  78 13.045 79.224 13.523 ;
     RECT  80.064 14.739 80.088 14.827 ;
     RECT  72.6 2.407 72.912 15.301 ;
     RECT  72.6 15.301 73.512 15.403 ;
     RECT  72.6 15.403 72.912 16.467 ;
     RECT  78 13.523 78.312 16.467 ;
     RECT  72.6 16.467 73.608 16.555 ;
     RECT  76.752 16.467 76.776 16.555 ;
     RECT  77.856 16.467 78.312 16.555 ;
     RECT  80.64 16.821 80.664 16.931 ;
     RECT  80.736 16.981 80.76 17.067 ;
     RECT  82.704 11.315 83.712 18.133 ;
     RECT  82.608 18.133 83.712 18.219 ;
     RECT  84.816 18.165 84.84 18.253 ;
     RECT  74.64 18.421 74.664 18.505 ;
     RECT  76.032 19.509 76.056 19.755 ;
     RECT  78 16.555 78.312 21.109 ;
     RECT  78 21.109 78.696 21.193 ;
     RECT  82.704 18.219 83.712 21.397 ;
     RECT  79.488 21.599 79.512 21.683 ;
     RECT  85.872 21.813 85.896 21.923 ;
     RECT  82.704 21.397 84.12 22.163 ;
     RECT  82.704 22.163 83.832 22.537 ;
     RECT  82.704 22.537 83.712 22.581 ;
     RECT  82.128 22.581 83.712 22.8 ;
     RECT  72.6 16.555 72.912 23.029 ;
     RECT  75.168 22.995 75.192 23.083 ;
     RECT  71.808 23.029 72.912 23.123 ;
     RECT  78 21.193 78.312 23.903 ;
     RECT  78 23.903 79.224 23.987 ;
     RECT  75.84 23.989 75.864 24.083 ;
     RECT  85.632 24.885 85.656 24.973 ;
     RECT  82.704 22.8 83.712 25.717 ;
     RECT  75.792 25.717 75.816 25.801 ;
     RECT  82.608 25.717 83.712 25.801 ;
     RECT  82.704 25.801 83.712 26.677 ;
     RECT  82.704 26.677 84.696 26.795 ;
     RECT  78 23.987 78.312 27.027 ;
     RECT  78 27.027 78.456 27.115 ;
     RECT  76.368 27.061 76.392 27.145 ;
     RECT  80.4 27.935 80.424 28.019 ;
     RECT  75.552 28.243 75.576 28.331 ;
     RECT  82.704 26.795 83.712 29.365 ;
     RECT  81.888 29.365 83.712 29.459 ;
     RECT  85.2 29.109 85.224 30.323 ;
     RECT  78 27.115 78.312 30.931 ;
     RECT  77.664 30.931 78.312 31.019 ;
     RECT  79.776 31.285 79.8 31.369 ;
     RECT  82.704 29.459 83.712 31.955 ;
     RECT  81.888 32.117 81.912 32.299 ;
     RECT  75.552 32.495 75.576 32.579 ;
     RECT  84.816 32.979 84.84 33.067 ;
     RECT  78 31.019 78.312 33.925 ;
     RECT  75.792 34.223 75.816 34.307 ;
     RECT  78 33.925 78.552 34.805 ;
     RECT  79.824 34.677 79.848 34.805 ;
     RECT  81.456 34.741 81.48 34.931 ;
     RECT  79.824 34.805 79.944 34.979 ;
     RECT  78 34.805 78.696 35.363 ;
     RECT  78 35.363 78.6 35.755 ;
     RECT  79.92 34.979 79.944 35.755 ;
     RECT  85.536 37.189 85.56 37.291 ;
     RECT  78 35.755 78.312 37.621 ;
     RECT  74.88 37.429 74.904 37.675 ;
     RECT  78 37.621 78.792 37.763 ;
     RECT  85.248 38.677 85.272 38.763 ;
     RECT  82.128 38.687 82.152 38.771 ;
     RECT  85.248 42.165 85.272 42.419 ;
     RECT  83.4 31.955 83.712 42.421 ;
     RECT  83.4 42.421 84.408 42.505 ;
     RECT  70.272 43.795 70.296 43.883 ;
     RECT  48.96 44.965 48.984 45.049 ;
     RECT  45.6 2.407 45.912 45.139 ;
     RECT  44.16 45.139 44.184 45.227 ;
     RECT  45.6 45.139 46.008 45.227 ;
     RECT  40.2 2.407 40.512 46.645 ;
     RECT  39.36 46.645 40.512 46.729 ;
     RECT  17.52 46.675 17.544 46.763 ;
     RECT  82.08 46.751 82.104 46.835 ;
     RECT  51 2.407 51.312 46.867 ;
     RECT  59.232 46.773 59.256 46.867 ;
     RECT  50.88 46.867 51.312 46.955 ;
     RECT  55.104 46.789 55.128 46.955 ;
     RECT  58.512 46.867 59.256 46.955 ;
     RECT  58.704 46.955 59.256 46.979 ;
     RECT  70.128 46.995 70.152 47.083 ;
     RECT  83.4 42.505 83.712 47.221 ;
     RECT  82.608 47.221 83.712 47.403 ;
     RECT  21.696 47.541 21.72 47.699 ;
     RECT  56.4 2.407 56.712 47.733 ;
     RECT  13.2 2.407 13.512 47.797 ;
     RECT  58.704 46.979 59.064 47.843 ;
     RECT  21.648 47.749 21.672 47.851 ;
     RECT  59.04 47.843 59.064 47.851 ;
     RECT  12.72 47.797 13.512 47.881 ;
     RECT  16.032 47.797 16.056 47.891 ;
     RECT  56.4 47.733 57.48 48.141 ;
     RECT  26.16 48.373 26.184 48.457 ;
     RECT  48.432 48.431 48.456 48.515 ;
     RECT  11.712 48.915 11.736 49.003 ;
     RECT  40.2 46.729 40.512 49.077 ;
     RECT  56.4 48.141 56.712 49.077 ;
     RECT  39.6 49.077 40.512 49.187 ;
     RECT  56.016 49.077 56.712 49.187 ;
     RECT  45.6 45.227 45.912 49.299 ;
     RECT  45.168 49.299 45.912 49.387 ;
     RECT  53.424 49.861 53.448 49.963 ;
     RECT  24 2.407 24.312 50.259 ;
     RECT  16.512 50.643 16.536 50.677 ;
     RECT  15.984 50.677 16.536 50.731 ;
     RECT  23.472 50.259 24.312 50.731 ;
     RECT  21.648 50.677 21.672 50.965 ;
     RECT  13.2 47.881 13.512 50.997 ;
     RECT  40.2 49.187 40.512 50.997 ;
     RECT  45.6 49.387 45.912 50.997 ;
     RECT  21.264 50.965 21.672 51.011 ;
     RECT  15.984 50.731 16.008 51.051 ;
     RECT  26.16 50.965 26.184 51.051 ;
     RECT  21.264 51.011 21.384 51.085 ;
     RECT  13.2 50.997 14.232 51.347 ;
     RECT  21.264 51.085 21.288 51.347 ;
     RECT  39.888 50.997 40.512 51.395 ;
     RECT  9.12 50.997 9.144 51.635 ;
     RECT  44.976 50.997 45.912 51.635 ;
     RECT  13.2 51.347 13.512 51.829 ;
     RECT  13.104 51.829 13.512 51.947 ;
     RECT  52.416 52.021 52.44 52.105 ;
     RECT  6.192 52.149 6.216 52.237 ;
     RECT  0.096 51.397 0.12 52.453 ;
     RECT  43.92 52.371 43.944 52.459 ;
     RECT  16.56 52.463 16.584 52.547 ;
     RECT  26.784 52.463 26.808 52.547 ;
     RECT  44.448 52.981 44.472 53.065 ;
     RECT  47.328 53.029 47.352 53.113 ;
     RECT  11.232 53.039 11.256 53.123 ;
     RECT  53.568 53.039 53.592 53.123 ;
     RECT  45.6 51.635 45.912 54.325 ;
     RECT  42.144 54.325 42.168 54.409 ;
     RECT  13.2 51.947 13.512 54.517 ;
     RECT  7.8 2.407 8.112 54.565 ;
     RECT  13.2 54.517 13.848 54.611 ;
     RECT  44.88 54.325 45.912 54.611 ;
     RECT  7.8 54.565 8.232 54.649 ;
     RECT  47.904 54.709 47.928 54.803 ;
     RECT  5.232 55.507 5.256 55.595 ;
     RECT  75.936 55.573 75.96 55.659 ;
     RECT  79.536 55.605 79.56 55.715 ;
     RECT  51 46.955 51.312 56.019 ;
     RECT  51 56.019 52.296 56.107 ;
     RECT  13.2 54.611 13.512 56.373 ;
     RECT  45.6 54.611 45.912 56.373 ;
     RECT  9.792 56.373 9.816 56.461 ;
     RECT  11.328 56.373 11.352 56.461 ;
     RECT  44.112 56.309 44.136 56.483 ;
     RECT  45.6 56.373 46.008 56.723 ;
     RECT  13.008 56.373 13.512 57.059 ;
     RECT  54.144 57.253 54.168 57.337 ;
     RECT  4.464 57.427 4.488 57.515 ;
     RECT  48.432 57.829 48.456 57.913 ;
     RECT  6.768 58.031 6.792 58.037 ;
     RECT  7.8 54.649 8.112 58.037 ;
     RECT  45.6 56.723 45.912 58.101 ;
     RECT  6.768 58.037 8.112 58.115 ;
     RECT  83.4 47.403 83.712 58.117 ;
     RECT  43.296 58.069 43.32 58.155 ;
     RECT  7.44 58.115 8.112 58.163 ;
     RECT  45.6 58.101 46.056 58.189 ;
     RECT  87.216 58.165 87.24 58.259 ;
     RECT  83.4 58.117 84.6 58.501 ;
     RECT  13.2 57.059 13.512 58.645 ;
     RECT  83.28 58.501 84.6 58.667 ;
     RECT  0.048 52.453 0.12 58.693 ;
     RECT  80.928 58.613 80.952 58.701 ;
     RECT  13.104 58.645 13.512 58.731 ;
     RECT  0.048 58.693 0.168 58.739 ;
     RECT  78 37.763 78.312 58.933 ;
     RECT  78 58.933 78.648 59.017 ;
     RECT  51 56.107 51.312 59.797 ;
     RECT  13.2 58.731 13.512 59.807 ;
     RECT  13.2 59.807 14.28 59.891 ;
     RECT  51 59.797 52.296 60.011 ;
     RECT  54.72 59.951 54.744 60.035 ;
     RECT  51 60.011 51.312 60.051 ;
     RECT  50.112 60.051 51.312 60.139 ;
     RECT  78 59.017 78.312 60.767 ;
     RECT  11.52 60.819 11.544 60.907 ;
     RECT  78 60.767 78.648 60.917 ;
     RECT  76.896 60.901 76.92 60.985 ;
     RECT  50.352 60.139 51.312 61.005 ;
     RECT  79.92 60.917 79.944 61.005 ;
     RECT  78 60.917 78.696 61.043 ;
     RECT  7.8 58.163 8.112 61.189 ;
     RECT  7.8 61.189 8.28 61.291 ;
     RECT  0.096 58.739 0.168 61.427 ;
     RECT  25.632 61.477 25.656 61.561 ;
     RECT  13.2 59.891 13.512 61.765 ;
     RECT  83.4 58.667 83.712 61.765 ;
     RECT  12.576 61.765 13.512 61.867 ;
     RECT  83.4 61.765 84.504 61.867 ;
     RECT  27.936 61.813 27.96 61.907 ;
     RECT  87.792 61.813 87.816 62.629 ;
     RECT  87.264 62.629 87.816 62.763 ;
     RECT  0.144 61.427 0.168 62.963 ;
     RECT  9.12 63.157 9.144 63.251 ;
     RECT  47.28 63.157 47.304 63.339 ;
     RECT  51 61.005 51.312 63.477 ;
     RECT  29.4 2.407 29.712 63.507 ;
     RECT  50.256 63.477 51.312 63.565 ;
     RECT  76.56 63.477 76.584 63.565 ;
     RECT  29.4 63.507 29.88 63.595 ;
     RECT  56.4 49.187 56.712 63.781 ;
     RECT  87.792 62.763 87.816 63.829 ;
     RECT  88.8 2.407 89.112 63.829 ;
     RECT  6.096 63.763 6.12 63.851 ;
     RECT  55.824 63.781 56.712 63.865 ;
     RECT  87.792 63.829 89.112 63.875 ;
     RECT  11.376 63.839 11.4 63.923 ;
     RECT  18.6 2.407 18.912 64.053 ;
     RECT  14.496 63.781 14.52 64.107 ;
     RECT  16.416 64.053 16.44 64.141 ;
     RECT  18.48 64.053 18.912 64.141 ;
     RECT  83.4 61.867 83.712 64.147 ;
     RECT  83.28 64.147 83.712 64.235 ;
     RECT  26.016 64.245 26.04 64.333 ;
     RECT  88.368 63.875 89.112 64.427 ;
     RECT  21.12 64.053 21.144 64.451 ;
     RECT  99.6 2.407 99.912 64.597 ;
     RECT  103.728 64.597 103.752 64.683 ;
     RECT  96.912 64.851 96.936 64.939 ;
     RECT  98.64 64.597 99.912 64.939 ;
     RECT  100.992 65.013 101.016 65.123 ;
     RECT  29.4 63.595 29.712 65.173 ;
     RECT  29.4 65.173 30.408 65.259 ;
     RECT  7.8 61.291 8.112 65.269 ;
     RECT  7.344 65.269 8.112 65.363 ;
     RECT  47.76 65.333 47.784 65.421 ;
     RECT  85.776 65.461 85.8 65.555 ;
     RECT  15.456 65.525 15.48 65.653 ;
     RECT  110.4 2.407 110.712 65.683 ;
     RECT  111.744 65.509 111.768 65.683 ;
     RECT  0.192 65.509 0.216 65.699 ;
     RECT  110.4 65.683 111.768 65.747 ;
     RECT  107.088 65.683 107.112 65.771 ;
     RECT  108.912 65.683 108.936 65.771 ;
     RECT  110.4 65.747 111.576 65.771 ;
     RECT  15.408 65.653 15.48 65.795 ;
     RECT  56.4 63.865 56.712 65.845 ;
     RECT  24 50.731 24.312 65.875 ;
     RECT  56.064 65.845 56.712 65.939 ;
     RECT  24 65.875 24.792 65.963 ;
     RECT  94.2 2.407 94.512 66.095 ;
     RECT  93.984 66.095 94.512 66.179 ;
     RECT  88.8 64.427 89.112 66.357 ;
     RECT  78 61.043 78.312 66.387 ;
     RECT  14.784 66.357 14.808 66.467 ;
     RECT  88.368 66.357 89.112 66.467 ;
     RECT  2.4 2.407 2.712 66.469 ;
     RECT  78 66.387 78.408 66.475 ;
     RECT  9.936 66.579 9.96 66.667 ;
     RECT  82.032 66.677 82.056 66.765 ;
     RECT  14.736 66.517 14.76 66.859 ;
     RECT  17.088 66.805 17.112 66.899 ;
     RECT  34.8 2.407 35.112 66.901 ;
     RECT  33.888 66.901 35.112 66.987 ;
     RECT  7.8 65.363 8.112 67.189 ;
     RECT  13.2 61.867 13.512 67.189 ;
     RECT  88.8 66.467 89.112 67.189 ;
     RECT  99.6 64.939 99.912 67.189 ;
     RECT  54.336 67.155 54.36 67.243 ;
     RECT  7.8 67.189 8.232 67.331 ;
     RECT  13.2 67.189 14.28 67.331 ;
     RECT  2.4 66.469 2.808 67.475 ;
     RECT  100.992 67.125 101.016 67.475 ;
     RECT  9.648 67.189 9.672 67.715 ;
     RECT  88.8 67.189 89.208 67.717 ;
     RECT  25.92 67.189 25.944 67.765 ;
     RECT  105 2.407 105.312 68.063 ;
     RECT  25.92 67.765 26.232 68.139 ;
     RECT  88.8 67.717 90.072 68.139 ;
     RECT  92.112 67.525 92.136 68.139 ;
     RECT  105 68.063 106.008 68.147 ;
     RECT  29.4 65.259 29.712 68.149 ;
     RECT  34.8 66.987 35.112 68.179 ;
     RECT  26.208 68.139 26.232 68.203 ;
     RECT  34.8 68.179 35.208 68.267 ;
     RECT  28.656 68.149 29.712 68.331 ;
     RECT  87.072 68.307 87.096 68.395 ;
     RECT  5.664 68.341 5.688 68.425 ;
     RECT  99.6 67.189 100.008 68.459 ;
     RECT  102.144 67.429 102.168 68.627 ;
     RECT  110.4 65.771 110.712 68.773 ;
     RECT  110.304 68.773 110.712 68.853 ;
     RECT  7.8 67.331 8.112 68.883 ;
     RECT  24 65.963 24.312 68.883 ;
     RECT  112.56 68.341 112.584 68.917 ;
     RECT  108.192 68.853 108.216 68.941 ;
     RECT  7.344 68.883 8.112 68.971 ;
     RECT  24 68.883 24.792 68.971 ;
     RECT  52.848 68.883 52.872 68.971 ;
     RECT  112.56 68.917 113.208 68.971 ;
     RECT  98.592 68.917 98.616 69.001 ;
     RECT  113.184 68.971 113.208 69.203 ;
     RECT  56.4 65.939 56.712 69.215 ;
     RECT  55.872 69.215 56.712 69.299 ;
     RECT  109.44 68.853 110.712 69.407 ;
     RECT  108.864 69.407 110.712 69.491 ;
     RECT  109.44 69.491 110.712 69.547 ;
     RECT  10.224 69.493 10.248 69.611 ;
     RECT  11.424 69.551 11.448 69.635 ;
     RECT  88.8 68.139 89.112 69.685 ;
     RECT  69.504 69.685 69.528 69.769 ;
     RECT  99.6 68.459 99.912 69.829 ;
     RECT  99.6 69.829 100.008 69.931 ;
     RECT  88.8 69.685 89.256 69.971 ;
     RECT  14.496 69.941 14.52 69.973 ;
     RECT  18.6 64.141 18.912 69.973 ;
     RECT  18.6 69.973 19.416 70.005 ;
     RECT  14.496 69.973 14.808 70.029 ;
     RECT  14.784 70.029 14.808 70.059 ;
     RECT  17.616 70.005 19.416 70.059 ;
     RECT  17.616 70.059 18.912 70.093 ;
     RECT  29.4 68.331 29.712 70.127 ;
     RECT  51 63.565 51.312 70.133 ;
     RECT  29.4 70.127 30.264 70.211 ;
     RECT  86.592 70.127 86.616 70.211 ;
     RECT  34.8 68.267 35.112 70.405 ;
     RECT  34.8 70.405 35.448 70.507 ;
     RECT  67.2 2.407 67.512 70.549 ;
     RECT  67.2 70.549 67.608 70.635 ;
     RECT  21.648 70.517 21.672 70.699 ;
     RECT  51 70.133 51.432 70.699 ;
     RECT  22.8 70.517 22.824 70.739 ;
     RECT  61.8 2.407 62.112 70.933 ;
     RECT  94.2 66.179 94.512 70.965 ;
     RECT  61.8 70.933 62.52 71.019 ;
     RECT  92.064 70.965 92.088 71.075 ;
     RECT  94.2 70.965 95.208 71.147 ;
     RECT  103.536 71.059 103.56 71.147 ;
     RECT  107.472 71.059 107.496 71.147 ;
     RECT  63.984 70.965 64.008 71.275 ;
     RECT  7.8 68.971 8.112 71.443 ;
     RECT  6.864 71.443 8.112 71.531 ;
     RECT  51 70.699 51.312 71.711 ;
     RECT  50.88 71.711 51.312 71.795 ;
     RECT  25.68 71.797 25.704 71.891 ;
     RECT  68.976 71.797 69 71.891 ;
     RECT  42.24 71.827 42.264 71.915 ;
     RECT  43.92 71.797 43.944 71.915 ;
     RECT  110.4 69.547 110.712 72.053 ;
     RECT  113.424 71.797 113.448 72.107 ;
     RECT  103.824 72.117 103.848 72.205 ;
     RECT  45.6 58.189 45.912 72.277 ;
     RECT  61.8 71.019 62.112 72.277 ;
     RECT  110.4 72.053 111.384 72.309 ;
     RECT  45.6 72.277 46.632 72.363 ;
     RECT  61.68 72.277 62.112 72.363 ;
     RECT  109.44 72.309 111.384 72.363 ;
     RECT  99.6 69.931 99.912 72.373 ;
     RECT  54 72.373 54.024 72.467 ;
     RECT  97.488 72.373 97.512 72.467 ;
     RECT  99.6 72.373 100.008 72.467 ;
     RECT  7.8 71.531 8.112 72.501 ;
     RECT  5.664 72.479 5.688 72.563 ;
     RECT  18.6 70.093 18.912 72.565 ;
     RECT  11.952 72.565 11.976 72.659 ;
     RECT  7.392 72.501 8.112 72.995 ;
     RECT  18.6 72.565 19.368 72.995 ;
     RECT  106.56 72.565 106.584 72.995 ;
     RECT  109.44 72.363 110.712 72.995 ;
     RECT  51 71.795 51.312 73.525 ;
     RECT  33.6 73.477 33.624 73.579 ;
     RECT  37.056 73.477 37.08 73.579 ;
     RECT  60.384 73.525 60.408 73.619 ;
     RECT  16.56 73.477 16.584 73.643 ;
     RECT  38.784 73.477 38.808 73.763 ;
     RECT  64.896 73.909 64.92 74.003 ;
     RECT  110.4 72.995 110.712 74.015 ;
     RECT  31.632 73.939 31.656 74.027 ;
     RECT  37.248 73.781 37.272 74.027 ;
     RECT  92.352 74.005 92.376 74.091 ;
     RECT  95.616 74.005 95.64 74.091 ;
     RECT  110.112 74.015 110.712 74.099 ;
     RECT  24 68.971 24.312 74.323 ;
     RECT  22.176 74.581 22.2 74.667 ;
     RECT  24 74.323 24.408 74.667 ;
     RECT  112.992 74.591 113.016 74.675 ;
     RECT  94.2 71.147 94.512 74.677 ;
     RECT  93.6 74.677 94.512 74.771 ;
     RECT  5.664 74.629 5.688 74.835 ;
     RECT  7.8 72.995 8.112 74.835 ;
     RECT  45.6 72.363 45.912 74.869 ;
     RECT  5.664 74.835 6.12 74.923 ;
     RECT  7.8 74.835 8.328 74.923 ;
     RECT  50.832 73.525 51.312 74.923 ;
     RECT  52.32 74.835 52.344 74.923 ;
     RECT  45.408 74.869 45.912 75.107 ;
     RECT  40.2 51.395 40.512 75.381 ;
     RECT  39.456 75.381 40.512 75.469 ;
     RECT  109.104 75.445 109.128 75.539 ;
     RECT  96.912 75.829 96.936 75.923 ;
     RECT  29.4 70.211 29.712 75.957 ;
     RECT  27.888 75.925 27.912 76.011 ;
     RECT  29.4 75.957 30.696 76.045 ;
     RECT  99.6 72.467 99.912 76.309 ;
     RECT  98.976 76.309 99.912 76.341 ;
     RECT  98.976 76.341 100.392 76.395 ;
     RECT  103.392 74.869 103.416 76.395 ;
     RECT  13.2 67.331 13.512 76.405 ;
     RECT  99.6 76.395 100.392 76.429 ;
     RECT  12.48 76.405 13.512 76.453 ;
     RECT  12 76.453 13.512 76.499 ;
     RECT  10.08 76.357 10.104 76.523 ;
     RECT  12 76.499 12.024 76.537 ;
     RECT  7.8 74.923 8.112 76.661 ;
     RECT  7.8 76.661 8.952 76.749 ;
     RECT  34.8 70.507 35.112 76.837 ;
     RECT  16.56 76.885 16.584 76.971 ;
     RECT  34.8 76.837 35.208 76.971 ;
     RECT  7.8 76.749 8.904 77.035 ;
     RECT  26.16 77.471 26.184 77.555 ;
     RECT  7.8 77.035 8.112 77.749 ;
     RECT  7.152 77.749 8.112 77.843 ;
     RECT  29.4 76.045 29.712 78.005 ;
     RECT  4.512 77.941 4.536 78.025 ;
     RECT  20.16 77.989 20.184 78.073 ;
     RECT  28.896 78.005 29.712 78.093 ;
     RECT  48.96 78.005 48.984 78.093 ;
     RECT  40.2 75.469 40.512 78.901 ;
     RECT  39.312 78.901 40.512 78.985 ;
     RECT  4.896 78.901 4.92 78.995 ;
     RECT  7.8 77.843 8.112 79.199 ;
     RECT  42.768 79.141 42.792 79.225 ;
     RECT  29.4 78.093 29.712 79.237 ;
     RECT  7.248 79.199 8.112 79.283 ;
     RECT  101.952 79.199 101.976 79.283 ;
     RECT  29.28 79.237 29.712 79.787 ;
     RECT  45.6 75.107 45.912 79.797 ;
     RECT  33.648 79.775 33.672 79.859 ;
     RECT  103.2 79.765 103.224 79.915 ;
     RECT  45.6 79.797 46.248 79.955 ;
     RECT  102 79.861 102.024 80.043 ;
     RECT  18.6 72.995 18.912 80.245 ;
     RECT  18.48 80.245 18.912 80.329 ;
     RECT  21.648 80.735 21.672 80.819 ;
     RECT  20.256 80.245 20.28 80.845 ;
     RECT  48 81.525 48.024 81.635 ;
     RECT  14.928 81.653 14.952 81.829 ;
     RECT  14.832 81.829 14.952 81.835 ;
     RECT  16.416 81.781 16.44 81.875 ;
     RECT  14.832 81.835 14.856 81.913 ;
     RECT  29.4 79.787 29.712 82.003 ;
     RECT  40.2 78.985 40.512 82.003 ;
     RECT  29.04 82.003 29.712 82.091 ;
     RECT  39.552 82.003 40.512 82.091 ;
     RECT  6.096 82.021 6.12 82.105 ;
     RECT  7.8 79.283 8.112 82.677 ;
     RECT  11.328 82.645 11.352 82.731 ;
     RECT  4.416 82.677 4.44 82.741 ;
     RECT  7.68 82.677 8.112 82.765 ;
     RECT  9.552 82.677 9.576 82.765 ;
     RECT  4.416 82.741 4.536 82.835 ;
     RECT  16.608 82.869 16.632 82.957 ;
     RECT  42.432 82.899 42.456 82.987 ;
     RECT  25.344 83.381 25.368 83.507 ;
     RECT  34.8 76.971 35.112 84.181 ;
     RECT  40.2 82.091 40.512 84.181 ;
     RECT  34.272 84.181 35.112 84.277 ;
     RECT  31.968 84.037 31.992 84.331 ;
     RECT  34.272 84.277 35.496 84.331 ;
     RECT  37.008 84.181 37.032 84.331 ;
     RECT  40.2 84.181 40.632 84.331 ;
     RECT  34.8 84.331 35.496 84.361 ;
     RECT  24 74.667 24.312 84.597 ;
     RECT  20.544 84.527 20.568 84.611 ;
     RECT  36.48 84.565 36.504 84.651 ;
     RECT  18.6 80.329 18.912 84.853 ;
     RECT  24 84.597 24.408 84.899 ;
     RECT  17.616 84.853 18.912 85.379 ;
     RECT  29.4 82.091 29.712 85.557 ;
     RECT  28.848 85.557 29.712 85.667 ;
     RECT  67.2 70.635 67.512 113.461 ;
     RECT  66.432 113.461 67.512 113.555 ;
     RECT  2.4 67.475 2.712 117.473 ;
     RECT  7.8 82.765 8.112 117.473 ;
     RECT  13.2 76.499 13.512 117.473 ;
     RECT  18.6 85.379 18.912 117.473 ;
     RECT  24 84.899 24.312 117.473 ;
     RECT  29.4 85.667 29.712 117.473 ;
     RECT  34.8 84.361 35.112 117.473 ;
     RECT  40.2 84.331 40.512 117.473 ;
     RECT  45.6 79.955 45.912 117.473 ;
     RECT  51 74.923 51.312 117.473 ;
     RECT  56.4 69.299 56.712 117.473 ;
     RECT  61.8 72.363 62.112 117.473 ;
     RECT  67.2 113.555 67.512 117.473 ;
     RECT  72.6 23.123 72.912 117.473 ;
     RECT  78 66.475 78.312 117.473 ;
     RECT  83.4 64.235 83.712 117.473 ;
     RECT  88.8 69.971 89.112 117.473 ;
     RECT  94.2 74.771 94.512 117.473 ;
     RECT  99.6 76.429 99.912 117.473 ;
     RECT  105 68.147 105.312 117.473 ;
     RECT  110.4 74.099 110.712 117.473 ;
     RECT  115.8 2.407 116.112 117.473 ;
     RECT  2.4 117.473 2.52 117.743 ;
     RECT  7.8 117.473 7.92 117.743 ;
     RECT  13.2 117.473 13.32 117.743 ;
     RECT  18.6 117.473 18.72 117.743 ;
     RECT  24 117.473 24.12 117.743 ;
     RECT  29.4 117.473 29.52 117.743 ;
     RECT  34.8 117.473 34.92 117.743 ;
     RECT  40.2 117.473 40.32 117.743 ;
     RECT  45.6 117.473 45.72 117.743 ;
     RECT  51 117.473 51.12 117.743 ;
     RECT  56.4 117.473 56.52 117.743 ;
     RECT  61.8 117.473 61.92 117.743 ;
     RECT  67.2 117.473 67.32 117.743 ;
     RECT  72.6 117.473 72.72 117.743 ;
     RECT  78 117.473 78.12 117.743 ;
     RECT  83.4 117.473 83.52 117.743 ;
     RECT  88.8 117.473 88.92 117.743 ;
     RECT  94.2 117.473 94.32 117.743 ;
     RECT  99.6 117.473 99.72 117.743 ;
     RECT  105 117.473 105.12 117.743 ;
     RECT  110.4 117.473 110.52 117.743 ;
     RECT  115.8 117.473 115.92 117.743 ;
     RECT  69.168 116.293 69.192 119.125 ;
     RECT  68.976 119.125 69.192 119.797 ;
     RECT  68.976 119.797 69.384 119.952 ;
     RECT  64.992 119.797 65.016 119.979 ;
    LAYER M6 ;
     RECT  2.16 83.529 4.405 84.201 ;
     RECT  2.16 56.529 4.453 57.201 ;
     RECT  2.16 78.129 4.501 78.801 ;
     RECT  4.501 77.952 4.885 78.801 ;
     RECT  4.885 77.952 4.917 78.944 ;
     RECT  4.917 77.76 4.971 78.944 ;
     RECT  4.453 56.529 5.221 57.504 ;
     RECT  2.16 67.329 5.653 68.001 ;
     RECT  2.16 72.729 5.653 73.401 ;
     RECT  5.221 55.552 5.685 57.504 ;
     RECT  5.685 54.592 5.739 58.08 ;
     RECT  4.405 82.688 6.062 84.201 ;
     RECT  2.16 61.929 6.085 62.601 ;
     RECT  6.062 82.048 6.131 84.201 ;
     RECT  2.16 51.129 6.181 51.801 ;
     RECT  6.181 51.129 6.197 52.192 ;
     RECT  6.197 51.008 6.251 52.192 ;
     RECT  5.653 72.512 6.837 73.401 ;
     RECT  4.971 77.76 6.837 78.801 ;
     RECT  5.653 67.329 7.093 68.384 ;
     RECT  6.837 71.488 7.147 73.401 ;
     RECT  6.837 76.992 7.214 78.801 ;
     RECT  7.214 76.992 7.283 79.264 ;
     RECT  6.085 61.929 7.349 63.84 ;
     RECT  7.093 67.329 7.379 68.96 ;
     RECT  7.349 61.248 7.403 63.84 ;
     RECT  7.333 65.28 7.403 65.312 ;
     RECT  7.379 67.329 7.403 68.384 ;
     RECT  7.147 72.512 7.427 73.401 ;
     RECT  5.739 56.529 7.475 58.08 ;
     RECT  7.403 67.329 8.197 68.001 ;
     RECT  5.739 54.592 8.243 54.624 ;
     RECT  7.403 61.248 8.291 63.2 ;
     RECT  5.653 74.88 8.875 74.912 ;
     RECT  7.283 76.992 8.915 78.801 ;
     RECT  6.131 82.688 8.949 84.201 ;
     RECT  8.917 76.672 9.003 76.704 ;
     RECT  6.251 51.008 9.155 51.801 ;
     RECT  8.291 61.929 9.155 63.2 ;
     RECT  7.475 56.529 9.762 57.201 ;
     RECT  9.155 51.129 9.781 51.801 ;
     RECT  9.762 56.384 9.835 57.201 ;
     RECT  8.949 65.664 9.925 65.696 ;
     RECT  8.197 67.2 9.925 68.001 ;
     RECT  9.925 65.664 10.219 68.001 ;
     RECT  9.781 51.129 11.221 52.192 ;
     RECT  11.221 51.129 11.307 53.088 ;
     RECT  9.835 56.529 11.317 57.201 ;
     RECT  8.949 81.856 11.317 84.201 ;
     RECT  9.155 61.929 11.365 62.601 ;
     RECT  11.317 81.664 11.386 84.201 ;
     RECT  10.213 69.568 11.459 69.6 ;
     RECT  11.365 61.929 11.509 63.904 ;
     RECT  11.253 48.96 11.747 48.992 ;
     RECT  7.427 72.729 11.941 73.401 ;
     RECT  10.069 76.48 12.035 76.512 ;
     RECT  11.941 72.576 12.469 73.401 ;
     RECT  12.469 72.576 12.523 73.632 ;
     RECT  12.45 76.416 12.523 76.448 ;
     RECT  11.509 60.864 12.651 63.904 ;
     RECT  13.093 58.688 13.365 58.72 ;
     RECT  11.317 56.384 13.419 57.201 ;
     RECT  13.365 58.688 13.419 59.872 ;
     RECT  13.109 54.528 13.859 54.56 ;
     RECT  11.307 51.129 14.197 52.192 ;
     RECT  10.219 67.329 14.245 68.001 ;
     RECT  13.419 59.84 14.291 59.872 ;
     RECT  12.651 61.929 14.485 63.904 ;
     RECT  10.219 65.664 14.517 65.696 ;
     RECT  14.245 67.2 14.517 68.001 ;
     RECT  14.485 61.929 14.531 64.096 ;
     RECT  14.485 69.952 14.571 69.984 ;
     RECT  14.517 65.664 14.773 68.001 ;
     RECT  11.386 81.664 14.867 81.888 ;
     RECT  14.867 81.664 14.963 81.824 ;
     RECT  14.773 65.536 15.491 68.001 ;
     RECT  14.197 51.008 16.501 52.192 ;
     RECT  8.915 78.129 16.549 78.801 ;
     RECT  14.963 81.792 16.565 81.824 ;
     RECT  11.386 83.529 16.565 84.201 ;
     RECT  16.501 50.688 16.57 52.512 ;
     RECT  16.57 51.008 16.595 52.512 ;
     RECT  12.523 72.729 16.595 73.632 ;
     RECT  16.549 76.928 16.619 78.801 ;
     RECT  16.565 81.792 16.619 84.896 ;
     RECT  16.619 82.88 16.643 84.896 ;
     RECT  15.491 66.816 17.123 68.001 ;
     RECT  2.16 45.729 17.509 46.401 ;
     RECT  12.709 47.808 17.509 47.84 ;
     RECT  17.509 45.729 17.579 47.84 ;
     RECT  16.643 83.529 17.651 84.896 ;
     RECT  16.595 72.729 19.31 73.401 ;
     RECT  14.773 70.016 19.317 70.048 ;
     RECT  19.31 72.576 19.379 73.401 ;
     RECT  19.317 70.016 19.427 70.688 ;
     RECT  16.619 78.129 20.149 78.801 ;
     RECT  20.149 78.016 20.218 78.801 ;
     RECT  16.565 80.256 20.245 80.288 ;
     RECT  20.245 80.256 20.291 80.8 ;
     RECT  17.651 83.529 20.579 84.576 ;
     RECT  14.531 64.064 21.155 64.096 ;
     RECT  17.579 45.729 21.365 47.584 ;
     RECT  16.595 51.008 21.621 52.192 ;
     RECT  21.621 51.008 21.637 52.448 ;
     RECT  19.427 70.656 21.637 70.688 ;
     RECT  21.365 45.729 21.683 47.84 ;
     RECT  21.637 70.528 21.683 70.688 ;
     RECT  20.291 80.768 21.683 80.8 ;
     RECT  19.379 72.729 22.165 73.401 ;
     RECT  21.683 45.729 22.197 47.584 ;
     RECT  22.197 45.184 22.251 47.584 ;
     RECT  21.637 50.688 23.461 52.448 ;
     RECT  20.579 83.529 24.373 84.201 ;
     RECT  22.165 72.729 24.419 74.656 ;
     RECT  17.123 67.329 24.738 68.001 ;
     RECT  21.683 70.528 24.757 70.56 ;
     RECT  24.419 72.729 24.757 74.4 ;
     RECT  24.738 67.329 24.811 68.96 ;
     RECT  24.757 70.528 24.811 74.4 ;
     RECT  24.373 83.529 25.314 84.64 ;
     RECT  25.314 83.392 25.387 84.64 ;
     RECT  14.531 61.929 25.621 62.601 ;
     RECT  24.811 71.808 25.715 74.4 ;
     RECT  24.757 65.92 25.909 65.952 ;
     RECT  24.811 67.329 25.909 68.128 ;
     RECT  25.715 72.729 25.963 74.4 ;
     RECT  20.218 78.129 26.037 78.801 ;
     RECT  25.621 61.504 26.091 62.601 ;
     RECT  26.005 64.256 26.091 64.288 ;
     RECT  25.909 65.92 26.091 68.128 ;
     RECT  26.037 78.016 26.149 78.801 ;
     RECT  23.461 50.304 26.165 52.448 ;
     RECT  26.091 67.329 26.197 68.128 ;
     RECT  26.149 48.384 26.219 48.416 ;
     RECT  26.165 50.304 26.219 52.512 ;
     RECT  26.149 77.504 26.219 78.801 ;
     RECT  26.219 51.129 26.819 52.512 ;
     RECT  26.091 61.824 27.971 62.601 ;
     RECT  26.197 67.329 28.645 68.192 ;
     RECT  25.387 83.529 28.837 84.64 ;
     RECT  28.837 83.529 28.907 85.6 ;
     RECT  26.219 78.016 29.269 78.801 ;
     RECT  29.269 78.016 29.355 79.776 ;
     RECT  29.029 82.048 29.355 82.08 ;
     RECT  27.971 61.929 29.845 62.601 ;
     RECT  30.197 70.144 30.275 70.176 ;
     RECT  29.845 61.929 30.443 63.584 ;
     RECT  30.373 65.216 30.443 65.248 ;
     RECT  28.645 67.329 30.443 68.32 ;
     RECT  25.963 72.729 30.901 73.401 ;
     RECT  25.909 75.968 30.955 76 ;
     RECT  30.901 72.729 31.667 74.016 ;
     RECT  31.667 72.729 33.589 73.401 ;
     RECT  29.355 78.016 33.637 78.801 ;
     RECT  33.637 78.016 33.653 79.84 ;
     RECT  33.653 76.928 33.707 79.84 ;
     RECT  30.443 67.329 33.877 68.001 ;
     RECT  33.877 66.944 33.909 68.001 ;
     RECT  33.909 66.944 33.963 68.256 ;
     RECT  33.707 76.928 35.219 78.801 ;
     RECT  33.963 67.329 35.499 68.256 ;
     RECT  35.413 70.464 35.499 70.496 ;
     RECT  33.589 72.729 35.573 73.568 ;
     RECT  35.219 77.504 35.627 78.801 ;
     RECT  28.907 83.529 36.515 84.64 ;
     RECT  35.573 72.729 37.283 74.016 ;
     RECT  35.627 78.129 39.301 78.801 ;
     RECT  22.251 45.184 39.349 46.401 ;
     RECT  37.283 72.729 39.349 73.824 ;
     RECT  39.349 45.184 39.418 46.688 ;
     RECT  39.445 75.392 39.531 75.424 ;
     RECT  39.301 78.129 39.531 78.944 ;
     RECT  26.819 51.129 39.854 52.448 ;
     RECT  39.349 49.088 39.915 49.12 ;
     RECT  39.854 51.008 39.923 52.448 ;
     RECT  39.541 82.048 40.437 82.08 ;
     RECT  36.515 83.529 40.437 84.32 ;
     RECT  40.437 82.048 40.491 84.32 ;
     RECT  40.491 82.944 40.643 84.32 ;
     RECT  39.531 78.129 42.485 78.801 ;
     RECT  40.643 82.944 42.539 84.201 ;
     RECT  42.485 78.129 42.803 79.2 ;
     RECT  13.419 56.529 43.285 57.201 ;
     RECT  39.349 71.872 43.955 73.824 ;
     RECT  43.285 56.529 44.078 58.144 ;
     RECT  39.418 45.184 44.085 46.401 ;
     RECT  44.078 56.32 44.147 58.144 ;
     RECT  39.923 51.129 44.437 52.448 ;
     RECT  44.437 51.129 44.523 53.024 ;
     RECT  44.523 51.129 44.965 52.448 ;
     RECT  42.133 54.336 44.971 54.368 ;
     RECT  45.045 49.344 45.203 49.376 ;
     RECT  43.955 72.729 45.397 73.824 ;
     RECT  44.147 56.529 45.685 58.144 ;
     RECT  44.965 51.008 45.739 52.448 ;
     RECT  44.085 45.184 45.877 46.816 ;
     RECT  45.739 51.008 45.931 51.936 ;
     RECT  45.877 45.184 46.019 47.84 ;
     RECT  45.685 56.384 46.019 58.144 ;
     RECT  46.019 56.529 46.067 58.144 ;
     RECT  42.803 78.129 46.213 78.801 ;
     RECT  45.397 72.729 46.574 74.912 ;
     RECT  46.574 72.32 46.643 74.912 ;
     RECT  30.443 61.929 47.269 62.601 ;
     RECT  45.931 51.008 47.285 51.801 ;
     RECT  47.285 51.008 47.339 53.088 ;
     RECT  47.339 51.129 47.595 53.088 ;
     RECT  47.733 65.344 47.806 65.376 ;
     RECT  47.541 54.72 47.939 54.752 ;
     RECT  47.97 81.536 48.043 81.568 ;
     RECT  46.019 45.729 48.421 47.84 ;
     RECT  46.067 56.529 48.421 57.201 ;
     RECT  46.213 78.129 48.93 79.84 ;
     RECT  48.421 45.729 48.949 48.48 ;
     RECT  48.949 44.992 49.003 48.48 ;
     RECT  48.93 78.016 49.003 79.84 ;
     RECT  49.003 44.992 49.018 47.84 ;
     RECT  45.685 60.544 50.101 60.576 ;
     RECT  47.269 61.929 50.245 63.328 ;
     RECT  50.101 60.096 50.293 60.576 ;
     RECT  50.245 61.929 50.293 63.52 ;
     RECT  50.293 60.096 50.347 63.52 ;
     RECT  46.643 72.729 50.869 74.912 ;
     RECT  50.869 71.744 50.915 74.912 ;
     RECT  50.915 71.744 50.933 73.568 ;
     RECT  50.933 70.656 50.987 73.568 ;
     RECT  50.987 70.656 50.997 73.401 ;
     RECT  50.347 60.096 51.051 62.601 ;
     RECT  50.997 70.144 51.443 73.401 ;
     RECT  48.421 56.529 52.261 57.888 ;
     RECT  51.051 60.096 52.261 60.128 ;
     RECT  52.261 56.064 52.331 57.888 ;
     RECT  52.261 59.968 52.331 60.128 ;
     RECT  50.915 74.88 52.355 74.912 ;
     RECT  47.595 51.129 52.405 51.801 ;
     RECT  35.499 67.329 52.725 68.001 ;
     RECT  51.443 71.744 53.035 73.401 ;
     RECT  52.405 51.129 53.045 52.064 ;
     RECT  53.045 51.129 53.413 53.088 ;
     RECT  53.413 49.92 53.483 53.088 ;
     RECT  53.483 51.129 53.603 53.088 ;
     RECT  53.035 72.384 54.035 73.401 ;
     RECT  52.331 56.529 54.179 57.312 ;
     RECT  52.725 67.329 54.306 69.28 ;
     RECT  54.306 67.2 54.379 69.28 ;
     RECT  52.331 59.968 54.755 60 ;
     RECT  51.051 61.929 55.813 62.601 ;
     RECT  54.379 67.329 55.907 69.28 ;
     RECT  49.018 45.729 55.989 47.84 ;
     RECT  55.813 61.929 56.043 63.84 ;
     RECT  55.989 45.729 56.062 49.12 ;
     RECT  54.035 72.729 56.117 73.401 ;
     RECT  55.989 65.856 56.171 65.888 ;
     RECT  56.062 45.729 57.491 48.096 ;
     RECT  57.491 45.729 59.029 47.776 ;
     RECT  56.117 72.064 60.341 73.401 ;
     RECT  60.341 72.064 60.395 73.568 ;
     RECT  60.395 72.32 60.419 73.568 ;
     RECT  60.419 72.32 61.715 73.401 ;
     RECT  62.485 70.976 63.973 71.008 ;
     RECT  63.973 70.976 64.019 71.264 ;
     RECT  61.715 72.729 64.866 73.401 ;
     RECT  64.866 72.729 64.939 73.952 ;
     RECT  58.485 119.936 64.981 119.968 ;
     RECT  64.981 119.808 65.027 119.968 ;
     RECT  49.003 78.129 66.421 78.801 ;
     RECT  66.421 113.472 66.49 113.504 ;
     RECT  64.019 71.232 67.509 71.264 ;
     RECT  64.939 72.729 67.509 73.401 ;
     RECT  67.509 70.592 67.619 73.401 ;
     RECT  67.619 71.808 69.011 73.401 ;
     RECT  65.027 119.808 69.107 119.84 ;
     RECT  70.242 43.84 70.315 43.872 ;
     RECT  59.029 45.729 70.315 47.84 ;
     RECT  2.16 24.129 71.797 24.801 ;
     RECT  73.477 15.36 73.573 15.392 ;
     RECT  73.573 15.36 73.643 16.544 ;
     RECT  2.16 13.329 74.053 14.001 ;
     RECT  2.16 18.729 74.629 19.401 ;
     RECT  2.16 29.529 75.541 30.201 ;
     RECT  75.541 28.288 75.573 30.201 ;
     RECT  75.573 28.288 75.627 31.008 ;
     RECT  75.541 32.512 75.627 32.544 ;
     RECT  71.797 23.04 75.781 24.801 ;
     RECT  2.16 34.929 75.781 35.601 ;
     RECT  75.781 23.04 75.883 25.76 ;
     RECT  74.053 12.8 75.923 14.001 ;
     RECT  54.179 56.529 75.925 57.201 ;
     RECT  74.629 18.432 75.957 19.401 ;
     RECT  75.957 18.432 76.002 19.552 ;
     RECT  76.002 18.432 76.011 19.744 ;
     RECT  76.011 18.729 76.075 19.744 ;
     RECT  56.043 61.929 76.549 62.601 ;
     RECT  76.549 61.929 76.885 63.52 ;
     RECT  75.627 29.529 77.699 31.008 ;
     RECT  55.907 67.329 78.069 68.001 ;
     RECT  76.885 60.928 78.123 63.52 ;
     RECT  69.493 69.696 78.123 69.728 ;
     RECT  75.781 34.24 78.133 35.601 ;
     RECT  78.069 66.432 78.419 68.001 ;
     RECT  74.869 37.632 78.517 37.664 ;
     RECT  78.133 34.24 78.563 35.744 ;
     RECT  2.16 7.929 78.613 8.601 ;
     RECT  78.123 60.928 78.613 62.601 ;
     RECT  76.021 21.12 78.707 21.152 ;
     RECT  78.517 37.632 78.707 37.728 ;
     RECT  78.707 37.632 78.803 37.664 ;
     RECT  75.883 24.129 79.189 25.76 ;
     RECT  78.613 7.929 79.285 9.312 ;
     RECT  79.266 11.584 79.285 11.616 ;
     RECT  79.285 7.929 79.339 11.616 ;
     RECT  75.923 13.056 79.339 14.001 ;
     RECT  79.189 23.936 79.531 25.76 ;
     RECT  79.339 7.929 79.541 10.336 ;
     RECT  79.477 21.632 79.546 22.624 ;
     RECT  79.541 7.36 79.595 10.336 ;
     RECT  79.595 7.36 79.619 8.601 ;
     RECT  77.699 29.529 79.765 30.201 ;
     RECT  78.563 34.688 79.859 35.744 ;
     RECT  79.531 24.129 79.861 25.76 ;
     RECT  76.357 27.072 79.861 27.104 ;
     RECT  79.859 34.816 79.955 35.744 ;
     RECT  79.339 13.329 80.038 14.001 ;
     RECT  79.861 24.129 80.043 27.104 ;
     RECT  75.957 16.512 80.053 16.544 ;
     RECT  79.546 22.464 80.053 22.624 ;
     RECT  78.613 58.944 80.053 58.976 ;
     RECT  80.053 16.512 80.107 16.864 ;
     RECT  80.043 24.129 80.107 25.696 ;
     RECT  75.925 55.616 80.107 57.201 ;
     RECT  80.053 58.624 80.107 58.976 ;
     RECT  80.043 27.072 80.366 27.104 ;
     RECT  80.366 27.072 80.427 28 ;
     RECT  80.427 27.968 80.435 28 ;
     RECT  79.595 10.304 80.629 10.336 ;
     RECT  80.107 16.832 80.629 16.864 ;
     RECT  80.629 16.832 80.675 17.056 ;
     RECT  80.675 17.024 80.811 17.056 ;
     RECT  80.053 22.464 80.811 22.752 ;
     RECT  80.629 10.304 80.915 10.784 ;
     RECT  79.619 7.929 81.445 8.601 ;
     RECT  79.955 34.816 81.445 35.601 ;
     RECT  81.445 34.752 81.579 35.601 ;
     RECT  80.915 10.56 81.637 10.784 ;
     RECT  79.765 29.529 81.845 31.328 ;
     RECT  81.525 33.024 81.845 33.056 ;
     RECT  81.845 29.529 81.877 33.056 ;
     RECT  81.877 29.376 81.899 33.056 ;
     RECT  81.899 32.128 81.923 33.056 ;
     RECT  81.899 29.376 81.963 30.201 ;
     RECT  81.923 32.256 81.963 33.056 ;
     RECT  78.419 67.329 82.021 68.001 ;
     RECT  78.613 60.8 82.101 62.601 ;
     RECT  80.811 22.464 82.117 22.624 ;
     RECT  81.579 34.816 82.411 35.601 ;
     RECT  70.315 45.729 82.549 46.816 ;
     RECT  76.075 18.729 82.597 19.401 ;
     RECT  80.107 24.129 82.597 24.801 ;
     RECT  82.549 45.729 82.643 47.392 ;
     RECT  82.643 45.729 82.667 47.264 ;
     RECT  82.597 0.192 83.171 0.224 ;
     RECT  81.445 7.929 83.267 8.736 ;
     RECT  81.637 10.56 83.267 11.616 ;
     RECT  80.038 13.329 83.267 14.816 ;
     RECT  83.253 64.192 83.691 64.224 ;
     RECT  82.117 22.464 84.085 22.752 ;
     RECT  82.597 24.129 84.405 25.76 ;
     RECT  82.357 42.432 84.419 42.464 ;
     RECT  84.085 21.824 84.459 22.752 ;
     RECT  84.405 24.129 84.459 26.784 ;
     RECT  80.107 58.624 84.611 58.656 ;
     RECT  83.267 10.56 84.659 10.592 ;
     RECT  81.963 29.529 84.661 30.201 ;
     RECT  84.459 26.752 84.715 26.784 ;
     RECT  82.597 18.176 84.851 19.401 ;
     RECT  81.963 33.024 84.851 33.056 ;
     RECT  2.16 40.329 85.109 41.001 ;
     RECT  80.107 56.529 85.109 57.201 ;
     RECT  84.661 29.12 85.235 30.201 ;
     RECT  82.117 38.72 85.291 38.752 ;
     RECT  85.109 40.329 85.291 42.208 ;
     RECT  85.237 37.248 85.571 37.28 ;
     RECT  84.459 24.129 85.667 24.928 ;
     RECT  82.021 66.688 85.749 68.001 ;
     RECT  85.749 65.472 85.803 68.001 ;
     RECT  85.803 65.472 85.822 65.504 ;
     RECT  83.267 7.929 85.986 8.601 ;
     RECT  85.986 7.808 86.059 8.601 ;
     RECT  84.459 21.824 86.059 21.856 ;
     RECT  85.749 69.696 86.562 69.728 ;
     RECT  85.803 67.329 86.581 68.001 ;
     RECT  86.562 69.696 86.635 70.176 ;
     RECT  85.109 56.529 87.251 58.208 ;
     RECT  82.101 60.672 87.253 62.601 ;
     RECT  87.253 60.672 87.787 62.752 ;
     RECT  86.581 67.329 88.357 68.384 ;
     RECT  88.357 64.384 88.427 64.416 ;
     RECT  88.357 66.368 88.683 68.384 ;
     RECT  87.787 60.672 89.003 62.601 ;
     RECT  88.683 67.2 89.219 68.128 ;
     RECT  69.011 72.729 89.589 73.401 ;
     RECT  86.635 69.696 89.643 69.728 ;
     RECT  89.219 67.329 90.083 68.128 ;
     RECT  90.083 67.329 92.078 68.001 ;
     RECT  92.078 67.329 92.147 68.128 ;
     RECT  89.589 72.729 93.589 74.08 ;
     RECT  93.589 72.729 93.675 74.72 ;
     RECT  92.147 67.329 93.973 68.001 ;
     RECT  93.973 66.112 94.005 68.001 ;
     RECT  94.005 64.896 94.059 68.001 ;
     RECT  92.043 70.976 95.173 71.008 ;
     RECT  95.173 70.976 95.219 71.136 ;
     RECT  95.219 71.104 95.221 71.136 ;
     RECT  93.675 72.729 95.221 74.08 ;
     RECT  95.221 71.104 95.275 74.08 ;
     RECT  95.275 72.384 95.659 74.08 ;
     RECT  95.605 75.84 96.947 75.872 ;
     RECT  95.659 72.384 97.523 73.401 ;
     RECT  94.059 67.329 98.581 68.001 ;
     RECT  94.059 64.896 98.629 64.928 ;
     RECT  98.629 64.64 98.675 64.928 ;
     RECT  98.581 67.329 99.829 68.96 ;
     RECT  97.523 72.729 99.829 73.401 ;
     RECT  99.829 67.329 99.883 69.92 ;
     RECT  99.883 67.329 99.973 68.448 ;
     RECT  99.973 67.2 100.019 68.448 ;
     RECT  99.883 69.888 100.019 69.92 ;
     RECT  99.829 72.384 100.019 73.401 ;
     RECT  98.675 64.64 100.962 64.672 ;
     RECT  100.019 67.2 100.981 68.001 ;
     RECT  100.962 64.64 101.035 65.056 ;
     RECT  100.981 67.136 101.05 68.001 ;
     RECT  101.05 67.2 101.547 68.001 ;
     RECT  66.421 78.129 102.035 80.032 ;
     RECT  98.965 76.352 103.381 76.384 ;
     RECT  103.381 75.456 103.595 76.384 ;
     RECT  102.035 78.129 103.595 79.904 ;
     RECT  101.035 64.64 103.763 64.672 ;
     RECT  103.525 71.104 103.813 71.136 ;
     RECT  100.019 72.729 103.813 73.401 ;
     RECT  103.813 71.104 103.915 73.401 ;
     RECT  101.547 67.329 105.973 68.001 ;
     RECT  103.915 72.729 106.53 73.401 ;
     RECT  106.53 72.576 106.603 73.401 ;
     RECT  105.973 67.329 107.189 68.128 ;
     RECT  101.493 69.44 107.189 69.472 ;
     RECT  107.189 67.329 109.41 69.472 ;
     RECT  103.915 71.104 109.414 71.136 ;
     RECT  106.603 72.729 109.414 73.401 ;
     RECT  109.41 67.329 109.483 69.536 ;
     RECT  109.414 71.104 109.483 73.401 ;
     RECT  109.483 72.32 110.069 73.401 ;
     RECT  103.595 75.456 110.069 75.488 ;
     RECT  110.069 72.32 110.123 75.488 ;
     RECT  110.123 72.32 111.349 74.656 ;
     RECT  107.077 65.728 111.587 65.76 ;
     RECT  111.349 72.064 113.027 74.656 ;
     RECT  109.483 67.329 113.219 68.96 ;
     RECT  113.027 72.064 113.459 73.401 ;
     RECT  2.16 2.529 117.828 3.201 ;
     RECT  86.059 7.929 117.828 8.601 ;
     RECT  83.267 13.329 117.828 14.001 ;
     RECT  84.851 18.729 117.828 19.401 ;
     RECT  85.667 24.129 117.828 24.801 ;
     RECT  85.235 29.529 117.828 30.201 ;
     RECT  82.411 34.929 117.828 35.601 ;
     RECT  85.291 40.329 117.828 41.001 ;
     RECT  82.667 45.729 117.828 46.401 ;
     RECT  53.603 51.129 117.828 51.801 ;
     RECT  87.251 56.529 117.828 57.201 ;
     RECT  89.003 61.929 117.828 62.601 ;
     RECT  113.219 67.329 117.828 68.001 ;
     RECT  113.459 72.729 117.828 73.401 ;
     RECT  103.595 78.129 117.828 78.801 ;
     RECT  42.539 83.529 117.828 84.201 ;
     RECT  2.16 88.929 117.828 89.601 ;
     RECT  2.16 94.329 117.828 95.001 ;
     RECT  2.16 99.729 117.828 100.401 ;
     RECT  2.16 105.129 117.828 105.801 ;
     RECT  2.16 110.529 117.828 111.201 ;
     RECT  2.16 115.929 117.828 116.601 ;
    LAYER M7 ;
     RECT  79.552 7.349 79.584 10.293 ;
     RECT  79.296 10.293 79.584 10.347 ;
     RECT  79.296 10.347 79.328 13.099 ;
     RECT  80.64 10.741 80.672 14.773 ;
     RECT  82.048 11.573 82.08 14.827 ;
     RECT  80.064 14.773 80.672 16.875 ;
     RECT  80.64 16.875 80.672 17.013 ;
     RECT  80.64 17.013 80.8 17.067 ;
     RECT  75.968 16.501 76 19.563 ;
     RECT  76.032 19.701 76.064 21.163 ;
     RECT  80.768 17.067 80.8 21.621 ;
     RECT  86.016 7.797 86.048 21.867 ;
     RECT  79.488 21.621 80.8 22.763 ;
     RECT  73.6 15.349 73.632 23.083 ;
     RECT  79.488 22.763 80.096 23.979 ;
     RECT  75.84 23.029 75.872 24.043 ;
     RECT  80.064 23.979 80.096 25.653 ;
     RECT  79.872 25.653 80.096 25.718 ;
     RECT  84.416 21.813 84.448 26.741 ;
     RECT  84.416 26.741 84.704 26.795 ;
     RECT  79.872 25.718 80.032 27.061 ;
     RECT  79.872 27.061 80.416 28.011 ;
     RECT  84.672 26.795 84.704 29.163 ;
     RECT  81.92 29.365 81.952 31.285 ;
     RECT  75.584 28.277 75.616 32.555 ;
     RECT  81.856 31.285 81.952 33.013 ;
     RECT  81.536 33.013 81.952 33.067 ;
     RECT  79.872 28.011 79.904 34.677 ;
     RECT  81.536 33.067 81.568 34.795 ;
     RECT  79.808 34.677 79.904 34.859 ;
     RECT  78.144 34.229 78.176 35.701 ;
     RECT  78.144 35.701 78.56 35.755 ;
     RECT  79.872 34.859 79.904 35.755 ;
     RECT  78.528 35.755 78.56 37.739 ;
     RECT  85.248 37.237 85.28 42.165 ;
     RECT  85.12 42.165 85.28 42.219 ;
     RECT  82.368 34.805 82.4 42.421 ;
     RECT  82.368 42.421 82.656 42.475 ;
     RECT  82.624 42.475 82.656 47.275 ;
     RECT  22.208 45.173 22.24 47.595 ;
     RECT  17.536 46.709 17.568 47.851 ;
     RECT  70.272 43.829 70.304 47.851 ;
     RECT  48.96 44.981 48.992 48.491 ;
     RECT  39.36 46.645 39.392 49.077 ;
     RECT  39.36 49.077 39.904 49.131 ;
     RECT  56 46.901 56.032 49.131 ;
     RECT  44.096 46.773 44.128 49.333 ;
     RECT  45.888 47.797 45.92 49.333 ;
     RECT  39.872 49.131 39.904 51.051 ;
     RECT  44.096 49.333 45.92 51.051 ;
     RECT  45.696 51.051 45.92 51.947 ;
     RECT  53.44 46.901 53.472 52.021 ;
     RECT  53.056 52.021 53.472 52.075 ;
     RECT  21.376 47.797 21.408 52.149 ;
     RECT  21.376 52.149 21.664 52.203 ;
     RECT  21.632 52.203 21.664 52.459 ;
     RECT  16.512 50.677 16.544 52.523 ;
     RECT  26.176 48.373 26.208 52.523 ;
     RECT  44.096 51.051 44.128 52.981 ;
     RECT  45.696 51.947 45.728 52.981 ;
     RECT  47.296 50.997 47.328 53.045 ;
     RECT  11.264 48.949 11.296 53.099 ;
     RECT  47.296 53.045 47.584 53.099 ;
     RECT  53.056 52.075 53.088 53.099 ;
     RECT  13.12 51.893 13.152 54.517 ;
     RECT  13.12 54.517 13.408 54.571 ;
     RECT  6.208 50.997 6.24 54.581 ;
     RECT  5.696 54.581 6.24 54.635 ;
     RECT  47.552 53.099 47.584 54.763 ;
     RECT  44.096 52.981 45.728 56.363 ;
     RECT  13.376 54.571 13.408 56.427 ;
     RECT  5.696 54.635 5.728 58.091 ;
     RECT  44.928 56.363 45.728 58.155 ;
     RECT  85.12 42.219 85.152 58.219 ;
     RECT  13.376 58.677 13.408 59.883 ;
     RECT  52.288 56.053 52.32 60.139 ;
     RECT  45.696 58.155 45.728 60.587 ;
     RECT  82.56 47.349 82.592 60.661 ;
     RECT  82.112 60.661 82.592 60.715 ;
     RECT  50.304 60.085 50.336 60.725 ;
     RECT  82.112 60.715 82.144 60.843 ;
     RECT  80.064 55.605 80.096 60.971 ;
     RECT  88.96 60.661 88.992 61.813 ;
     RECT  87.744 61.813 88.992 62.763 ;
     RECT  50.304 60.725 51.04 63.531 ;
     RECT  12.608 60.853 12.64 63.915 ;
     RECT  83.648 61.813 83.68 64.181 ;
     RECT  83.264 64.181 83.68 64.235 ;
     RECT  88.96 62.763 88.992 64.373 ;
     RECT  47.744 63.285 47.776 65.387 ;
     RECT  9.792 52.149 9.824 65.653 ;
     RECT  56 63.797 56.032 65.845 ;
     RECT  56 65.845 56.16 65.899 ;
     RECT  94.016 64.885 94.048 66.155 ;
     RECT  14.784 64.053 14.816 66.357 ;
     RECT  14.528 66.357 14.816 66.411 ;
     RECT  88.384 64.373 88.992 66.411 ;
     RECT  8.96 65.653 9.824 66.613 ;
     RECT  83.264 64.235 83.296 66.731 ;
     RECT  100.992 64.629 101.024 67.179 ;
     RECT  8.96 66.613 10.208 67.243 ;
     RECT  88.64 66.411 88.992 67.243 ;
     RECT  26.048 61.493 26.08 68.085 ;
     RECT  33.92 66.933 33.952 68.267 ;
     RECT  30.4 63.541 30.432 68.277 ;
     RECT  30.208 68.277 30.432 68.331 ;
     RECT  7.36 61.237 7.392 68.341 ;
     RECT  85.76 65.461 85.792 68.341 ;
     RECT  7.104 68.341 7.392 68.395 ;
     RECT  88.64 67.243 88.672 68.395 ;
     RECT  107.2 65.717 107.232 68.907 ;
     RECT  52.736 68.917 52.768 69.237 ;
     RECT  52.736 69.237 53.024 69.291 ;
     RECT  54.336 67.189 54.368 69.291 ;
     RECT  101.504 67.189 101.536 69.429 ;
     RECT  101.504 69.429 101.984 69.483 ;
     RECT  78.08 60.917 78.112 69.739 ;
     RECT  85.76 68.341 86.624 69.739 ;
     RECT  14.528 66.411 14.56 69.995 ;
     RECT  30.208 68.331 30.24 70.187 ;
     RECT  51.008 63.531 51.04 70.187 ;
     RECT  86.592 69.739 86.624 70.187 ;
     RECT  92.096 68.085 92.128 71.019 ;
     RECT  7.104 68.395 7.136 71.477 ;
     RECT  6.848 71.477 7.136 71.531 ;
     RECT  24.768 68.085 26.08 71.851 ;
     RECT  67.52 70.581 67.552 71.851 ;
     RECT  56.128 65.899 56.16 72.107 ;
     RECT  103.872 71.093 103.904 72.171 ;
     RECT  109.44 69.493 109.472 72.363 ;
     RECT  52.992 69.291 53.024 72.427 ;
     RECT  95.232 71.093 95.264 72.427 ;
     RECT  99.84 68.405 99.872 72.427 ;
     RECT  6.848 71.531 6.88 72.555 ;
     RECT  19.328 70.645 19.36 72.619 ;
     RECT  106.56 71.093 106.592 72.619 ;
     RECT  35.456 68.213 35.488 73.525 ;
     RECT  39.36 71.861 39.392 73.525 ;
     RECT  34.176 73.525 35.488 73.579 ;
     RECT  39.36 73.525 39.52 73.579 ;
     RECT  50.944 70.645 50.976 73.579 ;
     RECT  60.352 72.053 60.384 73.579 ;
     RECT  64.896 71.221 64.928 73.963 ;
     RECT  89.6 69.685 89.632 74.091 ;
     RECT  26.048 71.851 26.08 74.357 ;
     RECT  93.632 74.037 93.664 74.731 ;
     RECT  8.96 67.243 8.992 74.869 ;
     RECT  46.592 72.309 46.624 74.923 ;
     RECT  110.08 74.037 110.112 75.499 ;
     RECT  95.616 74.037 95.648 75.883 ;
     RECT  25.92 74.357 26.08 75.957 ;
     RECT  25.92 75.957 26.208 76.011 ;
     RECT  30.912 73.973 30.944 76.011 ;
     RECT  12.48 72.565 12.512 76.459 ;
     RECT  34.176 73.579 34.208 76.917 ;
     RECT  33.664 76.917 34.208 76.971 ;
     RECT  8.832 74.869 8.992 77.035 ;
     RECT  35.584 73.973 35.616 77.493 ;
     RECT  26.048 76.011 26.208 77.547 ;
     RECT  35.456 77.493 35.616 77.547 ;
     RECT  6.848 76.981 6.88 77.749 ;
     RECT  6.848 77.749 7.264 77.803 ;
     RECT  26.048 77.547 26.08 78.059 ;
     RECT  4.928 77.749 4.96 78.955 ;
     RECT  39.488 73.579 39.52 78.955 ;
     RECT  7.232 77.803 7.264 79.275 ;
     RECT  101.952 69.483 101.984 79.275 ;
     RECT  48.96 74.869 48.992 79.797 ;
     RECT  33.664 76.971 33.696 79.851 ;
     RECT  48 79.797 48.992 79.851 ;
     RECT  103.552 76.341 103.584 79.915 ;
     RECT  20.16 78.005 20.192 80.299 ;
     RECT  48 79.851 48.032 81.579 ;
     RECT  8.96 77.035 8.992 81.899 ;
     RECT  11.328 81.653 11.36 82.731 ;
     RECT  6.08 82.037 6.112 82.795 ;
     RECT  42.496 79.157 42.528 82.987 ;
     RECT  29.312 79.733 29.344 84.331 ;
     RECT  35.456 77.547 35.488 84.331 ;
     RECT  40.448 82.037 40.48 84.331 ;
     RECT  16.576 76.917 16.608 84.533 ;
     RECT  25.344 83.381 25.376 84.651 ;
     RECT  16.576 84.533 17.632 84.907 ;
     RECT  28.864 84.597 28.896 85.611 ;
     RECT  66.432 79.989 66.464 113.515 ;
     RECT  58.496 46.901 58.528 119.979 ;
  END
END ot_hgi_att_row_sources_p
END LIBRARY
